# Copyright lowRISC contributors (OpenTitan project).
# Licensed under the Apache License, Version 2.0, see LICENSE for details.
# SPDX-License-Identifier: Apache-2.0
#
# This file was derived by lowRISC contributors (OpenTitan project) from the
# IHP Open PDK SRAM abstract RM_IHPSG13_1P_8192x32_c4.lef
# (https://github.com/IHP-GmbH/IHP-Open-PDK, ihp-sg13g2/libs.ref/sg13g2_sram/lef).
# It is a synthetic abstract, not an IHP release: the macro size and pins come
# from the Liberty view, the pin shapes, power straps and antenna values from
# the IHP abstract. IHP's original notice follows:
#
#   Copyright 2023 IHP PDK Authors
#
#   Licensed under the Apache License, Version 2.0 (the "License");
#   you may not use this file except in compliance with the License.
#   You may obtain a copy of the License at
#
#      https://www.apache.org/licenses/LICENSE-2.0
#
#   Unless required by applicable law or agreed to in writing, software
#   distributed under the License is distributed on an "AS IS" BASIS,
#   WITHOUT WARRANTIES OR CONDITIONS OF ANY KIND, either express or implied.
#   See the License for the specific language governing permissions and
#   limitations under the License.
#
#   Generated on Mon Apr  7 14:15:46 2025
#
# Generated by gen_synthetic_lef.py from the Liberty view. Do not edit.
# Synthetic abstract: no physical layout exists behind this macro.

VERSION 5.7 ;
BUSBITCHARS "[]" ;
DIVIDERCHAR "/" ;

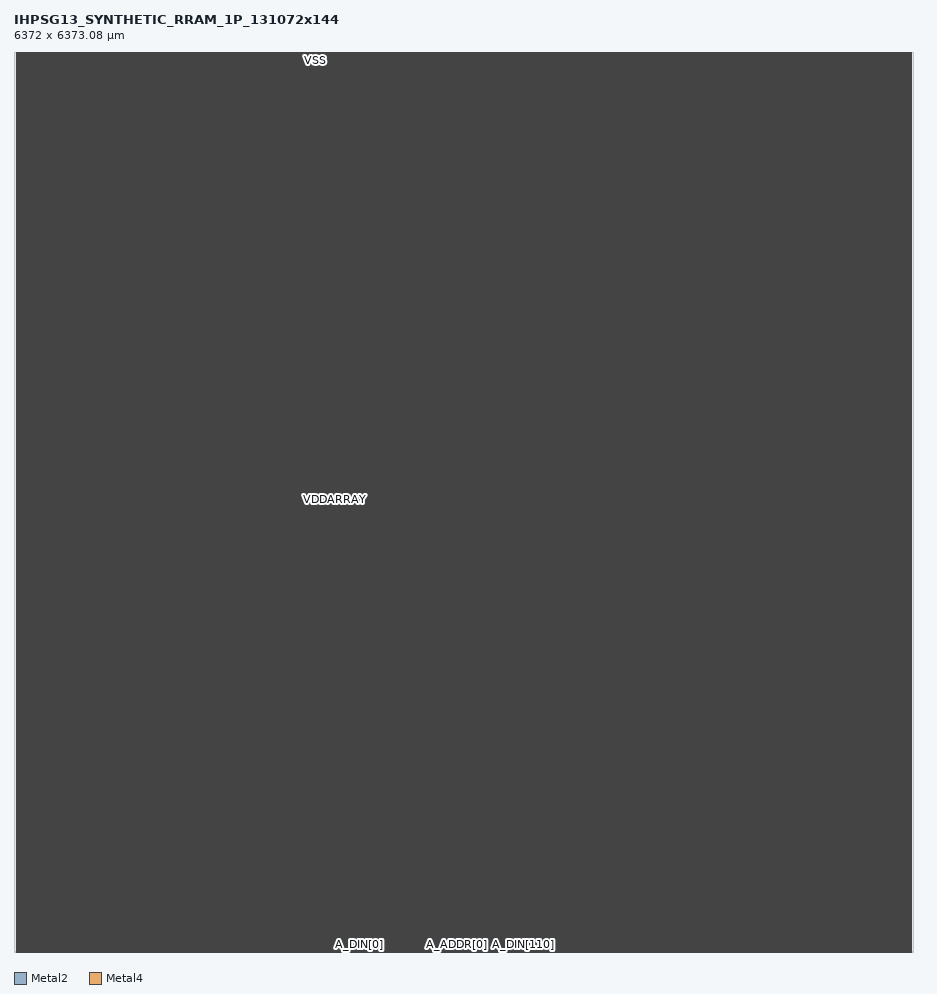
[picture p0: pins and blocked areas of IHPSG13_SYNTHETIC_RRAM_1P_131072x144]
MACRO IHPSG13_SYNTHETIC_RRAM_1P_131072x144
  CLASS BLOCK ;
  ORIGIN 0 0 ;
  FOREIGN IHPSG13_SYNTHETIC_RRAM_1P_131072x144 0 0 ;
  SIZE 6372 BY 6373.08 ;
  SYMMETRY X Y R90 ;
  PIN A_DIN[0]
    DIRECTION INPUT ;
    USE SIGNAL ;
    ANTENNAMODEL OXIDE1 ;
      ANTENNAGATEAREA 0.20085 LAYER Metal2 ;
    PORT
      LAYER Metal2 ;
        RECT 2444.03 0 2444.29 0.26 ;
    END
  END A_DIN[0]
  PIN A_DOUT[0]
    DIRECTION OUTPUT ;
    USE SIGNAL ;
    ANTENNADIFFAREA 0.988 LAYER Metal2 ;
    PORT
      LAYER Metal2 ;
        RECT 2448.83 0 2449.09 0.26 ;
    END
  END A_DOUT[0]
  PIN A_DIN[1]
    DIRECTION INPUT ;
    USE SIGNAL ;
    ANTENNAMODEL OXIDE1 ;
      ANTENNAGATEAREA 0.20085 LAYER Metal2 ;
    PORT
      LAYER Metal2 ;
        RECT 2453.63 0 2453.89 0.26 ;
    END
  END A_DIN[1]
  PIN A_DOUT[1]
    DIRECTION OUTPUT ;
    USE SIGNAL ;
    ANTENNADIFFAREA 0.988 LAYER Metal2 ;
    PORT
      LAYER Metal2 ;
        RECT 2458.43 0 2458.69 0.26 ;
    END
  END A_DOUT[1]
  PIN A_DIN[2]
    DIRECTION INPUT ;
    USE SIGNAL ;
    ANTENNAMODEL OXIDE1 ;
      ANTENNAGATEAREA 0.20085 LAYER Metal2 ;
    PORT
      LAYER Metal2 ;
        RECT 2463.23 0 2463.49 0.26 ;
    END
  END A_DIN[2]
  PIN A_DOUT[2]
    DIRECTION OUTPUT ;
    USE SIGNAL ;
    ANTENNADIFFAREA 0.988 LAYER Metal2 ;
    PORT
      LAYER Metal2 ;
        RECT 2468.03 0 2468.29 0.26 ;
    END
  END A_DOUT[2]
  PIN A_DIN[3]
    DIRECTION INPUT ;
    USE SIGNAL ;
    ANTENNAMODEL OXIDE1 ;
      ANTENNAGATEAREA 0.20085 LAYER Metal2 ;
    PORT
      LAYER Metal2 ;
        RECT 2472.83 0 2473.09 0.26 ;
    END
  END A_DIN[3]
  PIN A_DOUT[3]
    DIRECTION OUTPUT ;
    USE SIGNAL ;
    ANTENNADIFFAREA 0.988 LAYER Metal2 ;
    PORT
      LAYER Metal2 ;
        RECT 2477.63 0 2477.89 0.26 ;
    END
  END A_DOUT[3]
  PIN A_DIN[4]
    DIRECTION INPUT ;
    USE SIGNAL ;
    ANTENNAMODEL OXIDE1 ;
      ANTENNAGATEAREA 0.20085 LAYER Metal2 ;
    PORT
      LAYER Metal2 ;
        RECT 2482.43 0 2482.69 0.26 ;
    END
  END A_DIN[4]
  PIN A_DOUT[4]
    DIRECTION OUTPUT ;
    USE SIGNAL ;
    ANTENNADIFFAREA 0.988 LAYER Metal2 ;
    PORT
      LAYER Metal2 ;
        RECT 2487.23 0 2487.49 0.26 ;
    END
  END A_DOUT[4]
  PIN A_DIN[5]
    DIRECTION INPUT ;
    USE SIGNAL ;
    ANTENNAMODEL OXIDE1 ;
      ANTENNAGATEAREA 0.20085 LAYER Metal2 ;
    PORT
      LAYER Metal2 ;
        RECT 2492.03 0 2492.29 0.26 ;
    END
  END A_DIN[5]
  PIN A_DOUT[5]
    DIRECTION OUTPUT ;
    USE SIGNAL ;
    ANTENNADIFFAREA 0.988 LAYER Metal2 ;
    PORT
      LAYER Metal2 ;
        RECT 2496.83 0 2497.09 0.26 ;
    END
  END A_DOUT[5]
  PIN A_DIN[6]
    DIRECTION INPUT ;
    USE SIGNAL ;
    ANTENNAMODEL OXIDE1 ;
      ANTENNAGATEAREA 0.20085 LAYER Metal2 ;
    PORT
      LAYER Metal2 ;
        RECT 2501.63 0 2501.89 0.26 ;
    END
  END A_DIN[6]
  PIN A_DOUT[6]
    DIRECTION OUTPUT ;
    USE SIGNAL ;
    ANTENNADIFFAREA 0.988 LAYER Metal2 ;
    PORT
      LAYER Metal2 ;
        RECT 2506.43 0 2506.69 0.26 ;
    END
  END A_DOUT[6]
  PIN A_DIN[7]
    DIRECTION INPUT ;
    USE SIGNAL ;
    ANTENNAMODEL OXIDE1 ;
      ANTENNAGATEAREA 0.20085 LAYER Metal2 ;
    PORT
      LAYER Metal2 ;
        RECT 2511.23 0 2511.49 0.26 ;
    END
  END A_DIN[7]
  PIN A_DOUT[7]
    DIRECTION OUTPUT ;
    USE SIGNAL ;
    ANTENNADIFFAREA 0.988 LAYER Metal2 ;
    PORT
      LAYER Metal2 ;
        RECT 2516.03 0 2516.29 0.26 ;
    END
  END A_DOUT[7]
  PIN A_DIN[8]
    DIRECTION INPUT ;
    USE SIGNAL ;
    ANTENNAMODEL OXIDE1 ;
      ANTENNAGATEAREA 0.20085 LAYER Metal2 ;
    PORT
      LAYER Metal2 ;
        RECT 2520.83 0 2521.09 0.26 ;
    END
  END A_DIN[8]
  PIN A_DOUT[8]
    DIRECTION OUTPUT ;
    USE SIGNAL ;
    ANTENNADIFFAREA 0.988 LAYER Metal2 ;
    PORT
      LAYER Metal2 ;
        RECT 2525.63 0 2525.89 0.26 ;
    END
  END A_DOUT[8]
  PIN A_DIN[9]
    DIRECTION INPUT ;
    USE SIGNAL ;
    ANTENNAMODEL OXIDE1 ;
      ANTENNAGATEAREA 0.20085 LAYER Metal2 ;
    PORT
      LAYER Metal2 ;
        RECT 2530.43 0 2530.69 0.26 ;
    END
  END A_DIN[9]
  PIN A_DOUT[9]
    DIRECTION OUTPUT ;
    USE SIGNAL ;
    ANTENNADIFFAREA 0.988 LAYER Metal2 ;
    PORT
      LAYER Metal2 ;
        RECT 2535.23 0 2535.49 0.26 ;
    END
  END A_DOUT[9]
  PIN A_DIN[10]
    DIRECTION INPUT ;
    USE SIGNAL ;
    ANTENNAMODEL OXIDE1 ;
      ANTENNAGATEAREA 0.20085 LAYER Metal2 ;
    PORT
      LAYER Metal2 ;
        RECT 2540.03 0 2540.29 0.26 ;
    END
  END A_DIN[10]
  PIN A_DOUT[10]
    DIRECTION OUTPUT ;
    USE SIGNAL ;
    ANTENNADIFFAREA 0.988 LAYER Metal2 ;
    PORT
      LAYER Metal2 ;
        RECT 2544.83 0 2545.09 0.26 ;
    END
  END A_DOUT[10]
  PIN A_DIN[11]
    DIRECTION INPUT ;
    USE SIGNAL ;
    ANTENNAMODEL OXIDE1 ;
      ANTENNAGATEAREA 0.20085 LAYER Metal2 ;
    PORT
      LAYER Metal2 ;
        RECT 2549.63 0 2549.89 0.26 ;
    END
  END A_DIN[11]
  PIN A_DOUT[11]
    DIRECTION OUTPUT ;
    USE SIGNAL ;
    ANTENNADIFFAREA 0.988 LAYER Metal2 ;
    PORT
      LAYER Metal2 ;
        RECT 2554.43 0 2554.69 0.26 ;
    END
  END A_DOUT[11]
  PIN A_DIN[12]
    DIRECTION INPUT ;
    USE SIGNAL ;
    ANTENNAMODEL OXIDE1 ;
      ANTENNAGATEAREA 0.20085 LAYER Metal2 ;
    PORT
      LAYER Metal2 ;
        RECT 2559.23 0 2559.49 0.26 ;
    END
  END A_DIN[12]
  PIN A_DOUT[12]
    DIRECTION OUTPUT ;
    USE SIGNAL ;
    ANTENNADIFFAREA 0.988 LAYER Metal2 ;
    PORT
      LAYER Metal2 ;
        RECT 2564.03 0 2564.29 0.26 ;
    END
  END A_DOUT[12]
  PIN A_DIN[13]
    DIRECTION INPUT ;
    USE SIGNAL ;
    ANTENNAMODEL OXIDE1 ;
      ANTENNAGATEAREA 0.20085 LAYER Metal2 ;
    PORT
      LAYER Metal2 ;
        RECT 2568.83 0 2569.09 0.26 ;
    END
  END A_DIN[13]
  PIN A_DOUT[13]
    DIRECTION OUTPUT ;
    USE SIGNAL ;
    ANTENNADIFFAREA 0.988 LAYER Metal2 ;
    PORT
      LAYER Metal2 ;
        RECT 2573.63 0 2573.89 0.26 ;
    END
  END A_DOUT[13]
  PIN A_DIN[14]
    DIRECTION INPUT ;
    USE SIGNAL ;
    ANTENNAMODEL OXIDE1 ;
      ANTENNAGATEAREA 0.20085 LAYER Metal2 ;
    PORT
      LAYER Metal2 ;
        RECT 2578.43 0 2578.69 0.26 ;
    END
  END A_DIN[14]
  PIN A_DOUT[14]
    DIRECTION OUTPUT ;
    USE SIGNAL ;
    ANTENNADIFFAREA 0.988 LAYER Metal2 ;
    PORT
      LAYER Metal2 ;
        RECT 2583.23 0 2583.49 0.26 ;
    END
  END A_DOUT[14]
  PIN A_DIN[15]
    DIRECTION INPUT ;
    USE SIGNAL ;
    ANTENNAMODEL OXIDE1 ;
      ANTENNAGATEAREA 0.20085 LAYER Metal2 ;
    PORT
      LAYER Metal2 ;
        RECT 2588.03 0 2588.29 0.26 ;
    END
  END A_DIN[15]
  PIN A_DOUT[15]
    DIRECTION OUTPUT ;
    USE SIGNAL ;
    ANTENNADIFFAREA 0.988 LAYER Metal2 ;
    PORT
      LAYER Metal2 ;
        RECT 2592.83 0 2593.09 0.26 ;
    END
  END A_DOUT[15]
  PIN A_DIN[16]
    DIRECTION INPUT ;
    USE SIGNAL ;
    ANTENNAMODEL OXIDE1 ;
      ANTENNAGATEAREA 0.20085 LAYER Metal2 ;
    PORT
      LAYER Metal2 ;
        RECT 2597.63 0 2597.89 0.26 ;
    END
  END A_DIN[16]
  PIN A_DOUT[16]
    DIRECTION OUTPUT ;
    USE SIGNAL ;
    ANTENNADIFFAREA 0.988 LAYER Metal2 ;
    PORT
      LAYER Metal2 ;
        RECT 2602.43 0 2602.69 0.26 ;
    END
  END A_DOUT[16]
  PIN A_DIN[17]
    DIRECTION INPUT ;
    USE SIGNAL ;
    ANTENNAMODEL OXIDE1 ;
      ANTENNAGATEAREA 0.20085 LAYER Metal2 ;
    PORT
      LAYER Metal2 ;
        RECT 2607.23 0 2607.49 0.26 ;
    END
  END A_DIN[17]
  PIN A_DOUT[17]
    DIRECTION OUTPUT ;
    USE SIGNAL ;
    ANTENNADIFFAREA 0.988 LAYER Metal2 ;
    PORT
      LAYER Metal2 ;
        RECT 2612.03 0 2612.29 0.26 ;
    END
  END A_DOUT[17]
  PIN A_DIN[18]
    DIRECTION INPUT ;
    USE SIGNAL ;
    ANTENNAMODEL OXIDE1 ;
      ANTENNAGATEAREA 0.20085 LAYER Metal2 ;
    PORT
      LAYER Metal2 ;
        RECT 2616.83 0 2617.09 0.26 ;
    END
  END A_DIN[18]
  PIN A_DOUT[18]
    DIRECTION OUTPUT ;
    USE SIGNAL ;
    ANTENNADIFFAREA 0.988 LAYER Metal2 ;
    PORT
      LAYER Metal2 ;
        RECT 2621.63 0 2621.89 0.26 ;
    END
  END A_DOUT[18]
  PIN A_DIN[19]
    DIRECTION INPUT ;
    USE SIGNAL ;
    ANTENNAMODEL OXIDE1 ;
      ANTENNAGATEAREA 0.20085 LAYER Metal2 ;
    PORT
      LAYER Metal2 ;
        RECT 2626.43 0 2626.69 0.26 ;
    END
  END A_DIN[19]
  PIN A_DOUT[19]
    DIRECTION OUTPUT ;
    USE SIGNAL ;
    ANTENNADIFFAREA 0.988 LAYER Metal2 ;
    PORT
      LAYER Metal2 ;
        RECT 2631.23 0 2631.49 0.26 ;
    END
  END A_DOUT[19]
  PIN A_DIN[20]
    DIRECTION INPUT ;
    USE SIGNAL ;
    ANTENNAMODEL OXIDE1 ;
      ANTENNAGATEAREA 0.20085 LAYER Metal2 ;
    PORT
      LAYER Metal2 ;
        RECT 2636.03 0 2636.29 0.26 ;
    END
  END A_DIN[20]
  PIN A_DOUT[20]
    DIRECTION OUTPUT ;
    USE SIGNAL ;
    ANTENNADIFFAREA 0.988 LAYER Metal2 ;
    PORT
      LAYER Metal2 ;
        RECT 2640.83 0 2641.09 0.26 ;
    END
  END A_DOUT[20]
  PIN A_DIN[21]
    DIRECTION INPUT ;
    USE SIGNAL ;
    ANTENNAMODEL OXIDE1 ;
      ANTENNAGATEAREA 0.20085 LAYER Metal2 ;
    PORT
      LAYER Metal2 ;
        RECT 2645.63 0 2645.89 0.26 ;
    END
  END A_DIN[21]
  PIN A_DOUT[21]
    DIRECTION OUTPUT ;
    USE SIGNAL ;
    ANTENNADIFFAREA 0.988 LAYER Metal2 ;
    PORT
      LAYER Metal2 ;
        RECT 2650.43 0 2650.69 0.26 ;
    END
  END A_DOUT[21]
  PIN A_DIN[22]
    DIRECTION INPUT ;
    USE SIGNAL ;
    ANTENNAMODEL OXIDE1 ;
      ANTENNAGATEAREA 0.20085 LAYER Metal2 ;
    PORT
      LAYER Metal2 ;
        RECT 2655.23 0 2655.49 0.26 ;
    END
  END A_DIN[22]
  PIN A_DOUT[22]
    DIRECTION OUTPUT ;
    USE SIGNAL ;
    ANTENNADIFFAREA 0.988 LAYER Metal2 ;
    PORT
      LAYER Metal2 ;
        RECT 2660.03 0 2660.29 0.26 ;
    END
  END A_DOUT[22]
  PIN A_DIN[23]
    DIRECTION INPUT ;
    USE SIGNAL ;
    ANTENNAMODEL OXIDE1 ;
      ANTENNAGATEAREA 0.20085 LAYER Metal2 ;
    PORT
      LAYER Metal2 ;
        RECT 2664.83 0 2665.09 0.26 ;
    END
  END A_DIN[23]
  PIN A_DOUT[23]
    DIRECTION OUTPUT ;
    USE SIGNAL ;
    ANTENNADIFFAREA 0.988 LAYER Metal2 ;
    PORT
      LAYER Metal2 ;
        RECT 2669.63 0 2669.89 0.26 ;
    END
  END A_DOUT[23]
  PIN A_DIN[24]
    DIRECTION INPUT ;
    USE SIGNAL ;
    ANTENNAMODEL OXIDE1 ;
      ANTENNAGATEAREA 0.20085 LAYER Metal2 ;
    PORT
      LAYER Metal2 ;
        RECT 2674.43 0 2674.69 0.26 ;
    END
  END A_DIN[24]
  PIN A_DOUT[24]
    DIRECTION OUTPUT ;
    USE SIGNAL ;
    ANTENNADIFFAREA 0.988 LAYER Metal2 ;
    PORT
      LAYER Metal2 ;
        RECT 2679.23 0 2679.49 0.26 ;
    END
  END A_DOUT[24]
  PIN A_DIN[25]
    DIRECTION INPUT ;
    USE SIGNAL ;
    ANTENNAMODEL OXIDE1 ;
      ANTENNAGATEAREA 0.20085 LAYER Metal2 ;
    PORT
      LAYER Metal2 ;
        RECT 2684.03 0 2684.29 0.26 ;
    END
  END A_DIN[25]
  PIN A_DOUT[25]
    DIRECTION OUTPUT ;
    USE SIGNAL ;
    ANTENNADIFFAREA 0.988 LAYER Metal2 ;
    PORT
      LAYER Metal2 ;
        RECT 2688.83 0 2689.09 0.26 ;
    END
  END A_DOUT[25]
  PIN A_DIN[26]
    DIRECTION INPUT ;
    USE SIGNAL ;
    ANTENNAMODEL OXIDE1 ;
      ANTENNAGATEAREA 0.20085 LAYER Metal2 ;
    PORT
      LAYER Metal2 ;
        RECT 2693.63 0 2693.89 0.26 ;
    END
  END A_DIN[26]
  PIN A_DOUT[26]
    DIRECTION OUTPUT ;
    USE SIGNAL ;
    ANTENNADIFFAREA 0.988 LAYER Metal2 ;
    PORT
      LAYER Metal2 ;
        RECT 2698.43 0 2698.69 0.26 ;
    END
  END A_DOUT[26]
  PIN A_DIN[27]
    DIRECTION INPUT ;
    USE SIGNAL ;
    ANTENNAMODEL OXIDE1 ;
      ANTENNAGATEAREA 0.20085 LAYER Metal2 ;
    PORT
      LAYER Metal2 ;
        RECT 2703.23 0 2703.49 0.26 ;
    END
  END A_DIN[27]
  PIN A_DOUT[27]
    DIRECTION OUTPUT ;
    USE SIGNAL ;
    ANTENNADIFFAREA 0.988 LAYER Metal2 ;
    PORT
      LAYER Metal2 ;
        RECT 2708.03 0 2708.29 0.26 ;
    END
  END A_DOUT[27]
  PIN A_DIN[28]
    DIRECTION INPUT ;
    USE SIGNAL ;
    ANTENNAMODEL OXIDE1 ;
      ANTENNAGATEAREA 0.20085 LAYER Metal2 ;
    PORT
      LAYER Metal2 ;
        RECT 2712.83 0 2713.09 0.26 ;
    END
  END A_DIN[28]
  PIN A_DOUT[28]
    DIRECTION OUTPUT ;
    USE SIGNAL ;
    ANTENNADIFFAREA 0.988 LAYER Metal2 ;
    PORT
      LAYER Metal2 ;
        RECT 2717.63 0 2717.89 0.26 ;
    END
  END A_DOUT[28]
  PIN A_DIN[29]
    DIRECTION INPUT ;
    USE SIGNAL ;
    ANTENNAMODEL OXIDE1 ;
      ANTENNAGATEAREA 0.20085 LAYER Metal2 ;
    PORT
      LAYER Metal2 ;
        RECT 2722.43 0 2722.69 0.26 ;
    END
  END A_DIN[29]
  PIN A_DOUT[29]
    DIRECTION OUTPUT ;
    USE SIGNAL ;
    ANTENNADIFFAREA 0.988 LAYER Metal2 ;
    PORT
      LAYER Metal2 ;
        RECT 2727.23 0 2727.49 0.26 ;
    END
  END A_DOUT[29]
  PIN A_DIN[30]
    DIRECTION INPUT ;
    USE SIGNAL ;
    ANTENNAMODEL OXIDE1 ;
      ANTENNAGATEAREA 0.20085 LAYER Metal2 ;
    PORT
      LAYER Metal2 ;
        RECT 2732.03 0 2732.29 0.26 ;
    END
  END A_DIN[30]
  PIN A_DOUT[30]
    DIRECTION OUTPUT ;
    USE SIGNAL ;
    ANTENNADIFFAREA 0.988 LAYER Metal2 ;
    PORT
      LAYER Metal2 ;
        RECT 2736.83 0 2737.09 0.26 ;
    END
  END A_DOUT[30]
  PIN A_DIN[31]
    DIRECTION INPUT ;
    USE SIGNAL ;
    ANTENNAMODEL OXIDE1 ;
      ANTENNAGATEAREA 0.20085 LAYER Metal2 ;
    PORT
      LAYER Metal2 ;
        RECT 2741.63 0 2741.89 0.26 ;
    END
  END A_DIN[31]
  PIN A_DOUT[31]
    DIRECTION OUTPUT ;
    USE SIGNAL ;
    ANTENNADIFFAREA 0.988 LAYER Metal2 ;
    PORT
      LAYER Metal2 ;
        RECT 2746.43 0 2746.69 0.26 ;
    END
  END A_DOUT[31]
  PIN A_DIN[32]
    DIRECTION INPUT ;
    USE SIGNAL ;
    ANTENNAMODEL OXIDE1 ;
      ANTENNAGATEAREA 0.20085 LAYER Metal2 ;
    PORT
      LAYER Metal2 ;
        RECT 2751.23 0 2751.49 0.26 ;
    END
  END A_DIN[32]
  PIN A_DOUT[32]
    DIRECTION OUTPUT ;
    USE SIGNAL ;
    ANTENNADIFFAREA 0.988 LAYER Metal2 ;
    PORT
      LAYER Metal2 ;
        RECT 2756.03 0 2756.29 0.26 ;
    END
  END A_DOUT[32]
  PIN A_DIN[33]
    DIRECTION INPUT ;
    USE SIGNAL ;
    ANTENNAMODEL OXIDE1 ;
      ANTENNAGATEAREA 0.20085 LAYER Metal2 ;
    PORT
      LAYER Metal2 ;
        RECT 2760.83 0 2761.09 0.26 ;
    END
  END A_DIN[33]
  PIN A_DOUT[33]
    DIRECTION OUTPUT ;
    USE SIGNAL ;
    ANTENNADIFFAREA 0.988 LAYER Metal2 ;
    PORT
      LAYER Metal2 ;
        RECT 2765.63 0 2765.89 0.26 ;
    END
  END A_DOUT[33]
  PIN A_DIN[34]
    DIRECTION INPUT ;
    USE SIGNAL ;
    ANTENNAMODEL OXIDE1 ;
      ANTENNAGATEAREA 0.20085 LAYER Metal2 ;
    PORT
      LAYER Metal2 ;
        RECT 2770.43 0 2770.69 0.26 ;
    END
  END A_DIN[34]
  PIN A_DOUT[34]
    DIRECTION OUTPUT ;
    USE SIGNAL ;
    ANTENNADIFFAREA 0.988 LAYER Metal2 ;
    PORT
      LAYER Metal2 ;
        RECT 2775.23 0 2775.49 0.26 ;
    END
  END A_DOUT[34]
  PIN A_DIN[35]
    DIRECTION INPUT ;
    USE SIGNAL ;
    ANTENNAMODEL OXIDE1 ;
      ANTENNAGATEAREA 0.20085 LAYER Metal2 ;
    PORT
      LAYER Metal2 ;
        RECT 2780.03 0 2780.29 0.26 ;
    END
  END A_DIN[35]
  PIN A_DOUT[35]
    DIRECTION OUTPUT ;
    USE SIGNAL ;
    ANTENNADIFFAREA 0.988 LAYER Metal2 ;
    PORT
      LAYER Metal2 ;
        RECT 2784.83 0 2785.09 0.26 ;
    END
  END A_DOUT[35]
  PIN A_DIN[36]
    DIRECTION INPUT ;
    USE SIGNAL ;
    ANTENNAMODEL OXIDE1 ;
      ANTENNAGATEAREA 0.20085 LAYER Metal2 ;
    PORT
      LAYER Metal2 ;
        RECT 2789.63 0 2789.89 0.26 ;
    END
  END A_DIN[36]
  PIN A_DOUT[36]
    DIRECTION OUTPUT ;
    USE SIGNAL ;
    ANTENNADIFFAREA 0.988 LAYER Metal2 ;
    PORT
      LAYER Metal2 ;
        RECT 2794.43 0 2794.69 0.26 ;
    END
  END A_DOUT[36]
  PIN A_DIN[37]
    DIRECTION INPUT ;
    USE SIGNAL ;
    ANTENNAMODEL OXIDE1 ;
      ANTENNAGATEAREA 0.20085 LAYER Metal2 ;
    PORT
      LAYER Metal2 ;
        RECT 2799.23 0 2799.49 0.26 ;
    END
  END A_DIN[37]
  PIN A_DOUT[37]
    DIRECTION OUTPUT ;
    USE SIGNAL ;
    ANTENNADIFFAREA 0.988 LAYER Metal2 ;
    PORT
      LAYER Metal2 ;
        RECT 2804.03 0 2804.29 0.26 ;
    END
  END A_DOUT[37]
  PIN A_DIN[38]
    DIRECTION INPUT ;
    USE SIGNAL ;
    ANTENNAMODEL OXIDE1 ;
      ANTENNAGATEAREA 0.20085 LAYER Metal2 ;
    PORT
      LAYER Metal2 ;
        RECT 2808.83 0 2809.09 0.26 ;
    END
  END A_DIN[38]
  PIN A_DOUT[38]
    DIRECTION OUTPUT ;
    USE SIGNAL ;
    ANTENNADIFFAREA 0.988 LAYER Metal2 ;
    PORT
      LAYER Metal2 ;
        RECT 2813.63 0 2813.89 0.26 ;
    END
  END A_DOUT[38]
  PIN A_DIN[39]
    DIRECTION INPUT ;
    USE SIGNAL ;
    ANTENNAMODEL OXIDE1 ;
      ANTENNAGATEAREA 0.20085 LAYER Metal2 ;
    PORT
      LAYER Metal2 ;
        RECT 2818.43 0 2818.69 0.26 ;
    END
  END A_DIN[39]
  PIN A_DOUT[39]
    DIRECTION OUTPUT ;
    USE SIGNAL ;
    ANTENNADIFFAREA 0.988 LAYER Metal2 ;
    PORT
      LAYER Metal2 ;
        RECT 2823.23 0 2823.49 0.26 ;
    END
  END A_DOUT[39]
  PIN A_DIN[40]
    DIRECTION INPUT ;
    USE SIGNAL ;
    ANTENNAMODEL OXIDE1 ;
      ANTENNAGATEAREA 0.20085 LAYER Metal2 ;
    PORT
      LAYER Metal2 ;
        RECT 2828.03 0 2828.29 0.26 ;
    END
  END A_DIN[40]
  PIN A_DOUT[40]
    DIRECTION OUTPUT ;
    USE SIGNAL ;
    ANTENNADIFFAREA 0.988 LAYER Metal2 ;
    PORT
      LAYER Metal2 ;
        RECT 2832.83 0 2833.09 0.26 ;
    END
  END A_DOUT[40]
  PIN A_DIN[41]
    DIRECTION INPUT ;
    USE SIGNAL ;
    ANTENNAMODEL OXIDE1 ;
      ANTENNAGATEAREA 0.20085 LAYER Metal2 ;
    PORT
      LAYER Metal2 ;
        RECT 2837.63 0 2837.89 0.26 ;
    END
  END A_DIN[41]
  PIN A_DOUT[41]
    DIRECTION OUTPUT ;
    USE SIGNAL ;
    ANTENNADIFFAREA 0.988 LAYER Metal2 ;
    PORT
      LAYER Metal2 ;
        RECT 2842.43 0 2842.69 0.26 ;
    END
  END A_DOUT[41]
  PIN A_DIN[42]
    DIRECTION INPUT ;
    USE SIGNAL ;
    ANTENNAMODEL OXIDE1 ;
      ANTENNAGATEAREA 0.20085 LAYER Metal2 ;
    PORT
      LAYER Metal2 ;
        RECT 2847.23 0 2847.49 0.26 ;
    END
  END A_DIN[42]
  PIN A_DOUT[42]
    DIRECTION OUTPUT ;
    USE SIGNAL ;
    ANTENNADIFFAREA 0.988 LAYER Metal2 ;
    PORT
      LAYER Metal2 ;
        RECT 2852.03 0 2852.29 0.26 ;
    END
  END A_DOUT[42]
  PIN A_DIN[43]
    DIRECTION INPUT ;
    USE SIGNAL ;
    ANTENNAMODEL OXIDE1 ;
      ANTENNAGATEAREA 0.20085 LAYER Metal2 ;
    PORT
      LAYER Metal2 ;
        RECT 2856.83 0 2857.09 0.26 ;
    END
  END A_DIN[43]
  PIN A_DOUT[43]
    DIRECTION OUTPUT ;
    USE SIGNAL ;
    ANTENNADIFFAREA 0.988 LAYER Metal2 ;
    PORT
      LAYER Metal2 ;
        RECT 2861.63 0 2861.89 0.26 ;
    END
  END A_DOUT[43]
  PIN A_DIN[44]
    DIRECTION INPUT ;
    USE SIGNAL ;
    ANTENNAMODEL OXIDE1 ;
      ANTENNAGATEAREA 0.20085 LAYER Metal2 ;
    PORT
      LAYER Metal2 ;
        RECT 2866.43 0 2866.69 0.26 ;
    END
  END A_DIN[44]
  PIN A_DOUT[44]
    DIRECTION OUTPUT ;
    USE SIGNAL ;
    ANTENNADIFFAREA 0.988 LAYER Metal2 ;
    PORT
      LAYER Metal2 ;
        RECT 2871.23 0 2871.49 0.26 ;
    END
  END A_DOUT[44]
  PIN A_DIN[45]
    DIRECTION INPUT ;
    USE SIGNAL ;
    ANTENNAMODEL OXIDE1 ;
      ANTENNAGATEAREA 0.20085 LAYER Metal2 ;
    PORT
      LAYER Metal2 ;
        RECT 2876.03 0 2876.29 0.26 ;
    END
  END A_DIN[45]
  PIN A_DOUT[45]
    DIRECTION OUTPUT ;
    USE SIGNAL ;
    ANTENNADIFFAREA 0.988 LAYER Metal2 ;
    PORT
      LAYER Metal2 ;
        RECT 2880.83 0 2881.09 0.26 ;
    END
  END A_DOUT[45]
  PIN A_DIN[46]
    DIRECTION INPUT ;
    USE SIGNAL ;
    ANTENNAMODEL OXIDE1 ;
      ANTENNAGATEAREA 0.20085 LAYER Metal2 ;
    PORT
      LAYER Metal2 ;
        RECT 2885.63 0 2885.89 0.26 ;
    END
  END A_DIN[46]
  PIN A_DOUT[46]
    DIRECTION OUTPUT ;
    USE SIGNAL ;
    ANTENNADIFFAREA 0.988 LAYER Metal2 ;
    PORT
      LAYER Metal2 ;
        RECT 2890.43 0 2890.69 0.26 ;
    END
  END A_DOUT[46]
  PIN A_DIN[47]
    DIRECTION INPUT ;
    USE SIGNAL ;
    ANTENNAMODEL OXIDE1 ;
      ANTENNAGATEAREA 0.20085 LAYER Metal2 ;
    PORT
      LAYER Metal2 ;
        RECT 2895.23 0 2895.49 0.26 ;
    END
  END A_DIN[47]
  PIN A_DOUT[47]
    DIRECTION OUTPUT ;
    USE SIGNAL ;
    ANTENNADIFFAREA 0.988 LAYER Metal2 ;
    PORT
      LAYER Metal2 ;
        RECT 2900.03 0 2900.29 0.26 ;
    END
  END A_DOUT[47]
  PIN A_DIN[48]
    DIRECTION INPUT ;
    USE SIGNAL ;
    ANTENNAMODEL OXIDE1 ;
      ANTENNAGATEAREA 0.20085 LAYER Metal2 ;
    PORT
      LAYER Metal2 ;
        RECT 2904.83 0 2905.09 0.26 ;
    END
  END A_DIN[48]
  PIN A_DOUT[48]
    DIRECTION OUTPUT ;
    USE SIGNAL ;
    ANTENNADIFFAREA 0.988 LAYER Metal2 ;
    PORT
      LAYER Metal2 ;
        RECT 2909.63 0 2909.89 0.26 ;
    END
  END A_DOUT[48]
  PIN A_DIN[49]
    DIRECTION INPUT ;
    USE SIGNAL ;
    ANTENNAMODEL OXIDE1 ;
      ANTENNAGATEAREA 0.20085 LAYER Metal2 ;
    PORT
      LAYER Metal2 ;
        RECT 2914.43 0 2914.69 0.26 ;
    END
  END A_DIN[49]
  PIN A_DOUT[49]
    DIRECTION OUTPUT ;
    USE SIGNAL ;
    ANTENNADIFFAREA 0.988 LAYER Metal2 ;
    PORT
      LAYER Metal2 ;
        RECT 2919.23 0 2919.49 0.26 ;
    END
  END A_DOUT[49]
  PIN A_DIN[50]
    DIRECTION INPUT ;
    USE SIGNAL ;
    ANTENNAMODEL OXIDE1 ;
      ANTENNAGATEAREA 0.20085 LAYER Metal2 ;
    PORT
      LAYER Metal2 ;
        RECT 2924.03 0 2924.29 0.26 ;
    END
  END A_DIN[50]
  PIN A_DOUT[50]
    DIRECTION OUTPUT ;
    USE SIGNAL ;
    ANTENNADIFFAREA 0.988 LAYER Metal2 ;
    PORT
      LAYER Metal2 ;
        RECT 2928.83 0 2929.09 0.26 ;
    END
  END A_DOUT[50]
  PIN A_DIN[51]
    DIRECTION INPUT ;
    USE SIGNAL ;
    ANTENNAMODEL OXIDE1 ;
      ANTENNAGATEAREA 0.20085 LAYER Metal2 ;
    PORT
      LAYER Metal2 ;
        RECT 2933.63 0 2933.89 0.26 ;
    END
  END A_DIN[51]
  PIN A_DOUT[51]
    DIRECTION OUTPUT ;
    USE SIGNAL ;
    ANTENNADIFFAREA 0.988 LAYER Metal2 ;
    PORT
      LAYER Metal2 ;
        RECT 2938.43 0 2938.69 0.26 ;
    END
  END A_DOUT[51]
  PIN A_DIN[52]
    DIRECTION INPUT ;
    USE SIGNAL ;
    ANTENNAMODEL OXIDE1 ;
      ANTENNAGATEAREA 0.20085 LAYER Metal2 ;
    PORT
      LAYER Metal2 ;
        RECT 2943.23 0 2943.49 0.26 ;
    END
  END A_DIN[52]
  PIN A_DOUT[52]
    DIRECTION OUTPUT ;
    USE SIGNAL ;
    ANTENNADIFFAREA 0.988 LAYER Metal2 ;
    PORT
      LAYER Metal2 ;
        RECT 2948.03 0 2948.29 0.26 ;
    END
  END A_DOUT[52]
  PIN A_DIN[53]
    DIRECTION INPUT ;
    USE SIGNAL ;
    ANTENNAMODEL OXIDE1 ;
      ANTENNAGATEAREA 0.20085 LAYER Metal2 ;
    PORT
      LAYER Metal2 ;
        RECT 2952.83 0 2953.09 0.26 ;
    END
  END A_DIN[53]
  PIN A_DOUT[53]
    DIRECTION OUTPUT ;
    USE SIGNAL ;
    ANTENNADIFFAREA 0.988 LAYER Metal2 ;
    PORT
      LAYER Metal2 ;
        RECT 2957.63 0 2957.89 0.26 ;
    END
  END A_DOUT[53]
  PIN A_DIN[54]
    DIRECTION INPUT ;
    USE SIGNAL ;
    ANTENNAMODEL OXIDE1 ;
      ANTENNAGATEAREA 0.20085 LAYER Metal2 ;
    PORT
      LAYER Metal2 ;
        RECT 2962.43 0 2962.69 0.26 ;
    END
  END A_DIN[54]
  PIN A_DOUT[54]
    DIRECTION OUTPUT ;
    USE SIGNAL ;
    ANTENNADIFFAREA 0.988 LAYER Metal2 ;
    PORT
      LAYER Metal2 ;
        RECT 2967.23 0 2967.49 0.26 ;
    END
  END A_DOUT[54]
  PIN A_DIN[55]
    DIRECTION INPUT ;
    USE SIGNAL ;
    ANTENNAMODEL OXIDE1 ;
      ANTENNAGATEAREA 0.20085 LAYER Metal2 ;
    PORT
      LAYER Metal2 ;
        RECT 2972.03 0 2972.29 0.26 ;
    END
  END A_DIN[55]
  PIN A_DOUT[55]
    DIRECTION OUTPUT ;
    USE SIGNAL ;
    ANTENNADIFFAREA 0.988 LAYER Metal2 ;
    PORT
      LAYER Metal2 ;
        RECT 2976.83 0 2977.09 0.26 ;
    END
  END A_DOUT[55]
  PIN A_DIN[56]
    DIRECTION INPUT ;
    USE SIGNAL ;
    ANTENNAMODEL OXIDE1 ;
      ANTENNAGATEAREA 0.20085 LAYER Metal2 ;
    PORT
      LAYER Metal2 ;
        RECT 2981.63 0 2981.89 0.26 ;
    END
  END A_DIN[56]
  PIN A_DOUT[56]
    DIRECTION OUTPUT ;
    USE SIGNAL ;
    ANTENNADIFFAREA 0.988 LAYER Metal2 ;
    PORT
      LAYER Metal2 ;
        RECT 2986.43 0 2986.69 0.26 ;
    END
  END A_DOUT[56]
  PIN A_DIN[57]
    DIRECTION INPUT ;
    USE SIGNAL ;
    ANTENNAMODEL OXIDE1 ;
      ANTENNAGATEAREA 0.20085 LAYER Metal2 ;
    PORT
      LAYER Metal2 ;
        RECT 2991.23 0 2991.49 0.26 ;
    END
  END A_DIN[57]
  PIN A_DOUT[57]
    DIRECTION OUTPUT ;
    USE SIGNAL ;
    ANTENNADIFFAREA 0.988 LAYER Metal2 ;
    PORT
      LAYER Metal2 ;
        RECT 2996.03 0 2996.29 0.26 ;
    END
  END A_DOUT[57]
  PIN A_DIN[58]
    DIRECTION INPUT ;
    USE SIGNAL ;
    ANTENNAMODEL OXIDE1 ;
      ANTENNAGATEAREA 0.20085 LAYER Metal2 ;
    PORT
      LAYER Metal2 ;
        RECT 3000.83 0 3001.09 0.26 ;
    END
  END A_DIN[58]
  PIN A_DOUT[58]
    DIRECTION OUTPUT ;
    USE SIGNAL ;
    ANTENNADIFFAREA 0.988 LAYER Metal2 ;
    PORT
      LAYER Metal2 ;
        RECT 3005.63 0 3005.89 0.26 ;
    END
  END A_DOUT[58]
  PIN A_DIN[59]
    DIRECTION INPUT ;
    USE SIGNAL ;
    ANTENNAMODEL OXIDE1 ;
      ANTENNAGATEAREA 0.20085 LAYER Metal2 ;
    PORT
      LAYER Metal2 ;
        RECT 3010.43 0 3010.69 0.26 ;
    END
  END A_DIN[59]
  PIN A_DOUT[59]
    DIRECTION OUTPUT ;
    USE SIGNAL ;
    ANTENNADIFFAREA 0.988 LAYER Metal2 ;
    PORT
      LAYER Metal2 ;
        RECT 3015.23 0 3015.49 0.26 ;
    END
  END A_DOUT[59]
  PIN A_DIN[60]
    DIRECTION INPUT ;
    USE SIGNAL ;
    ANTENNAMODEL OXIDE1 ;
      ANTENNAGATEAREA 0.20085 LAYER Metal2 ;
    PORT
      LAYER Metal2 ;
        RECT 3020.03 0 3020.29 0.26 ;
    END
  END A_DIN[60]
  PIN A_DOUT[60]
    DIRECTION OUTPUT ;
    USE SIGNAL ;
    ANTENNADIFFAREA 0.988 LAYER Metal2 ;
    PORT
      LAYER Metal2 ;
        RECT 3024.83 0 3025.09 0.26 ;
    END
  END A_DOUT[60]
  PIN A_DIN[61]
    DIRECTION INPUT ;
    USE SIGNAL ;
    ANTENNAMODEL OXIDE1 ;
      ANTENNAGATEAREA 0.20085 LAYER Metal2 ;
    PORT
      LAYER Metal2 ;
        RECT 3029.63 0 3029.89 0.26 ;
    END
  END A_DIN[61]
  PIN A_DOUT[61]
    DIRECTION OUTPUT ;
    USE SIGNAL ;
    ANTENNADIFFAREA 0.988 LAYER Metal2 ;
    PORT
      LAYER Metal2 ;
        RECT 3034.43 0 3034.69 0.26 ;
    END
  END A_DOUT[61]
  PIN A_DIN[62]
    DIRECTION INPUT ;
    USE SIGNAL ;
    ANTENNAMODEL OXIDE1 ;
      ANTENNAGATEAREA 0.20085 LAYER Metal2 ;
    PORT
      LAYER Metal2 ;
        RECT 3039.23 0 3039.49 0.26 ;
    END
  END A_DIN[62]
  PIN A_DOUT[62]
    DIRECTION OUTPUT ;
    USE SIGNAL ;
    ANTENNADIFFAREA 0.988 LAYER Metal2 ;
    PORT
      LAYER Metal2 ;
        RECT 3044.03 0 3044.29 0.26 ;
    END
  END A_DOUT[62]
  PIN A_DIN[63]
    DIRECTION INPUT ;
    USE SIGNAL ;
    ANTENNAMODEL OXIDE1 ;
      ANTENNAGATEAREA 0.20085 LAYER Metal2 ;
    PORT
      LAYER Metal2 ;
        RECT 3048.83 0 3049.09 0.26 ;
    END
  END A_DIN[63]
  PIN A_DOUT[63]
    DIRECTION OUTPUT ;
    USE SIGNAL ;
    ANTENNADIFFAREA 0.988 LAYER Metal2 ;
    PORT
      LAYER Metal2 ;
        RECT 3053.63 0 3053.89 0.26 ;
    END
  END A_DOUT[63]
  PIN A_DIN[64]
    DIRECTION INPUT ;
    USE SIGNAL ;
    ANTENNAMODEL OXIDE1 ;
      ANTENNAGATEAREA 0.20085 LAYER Metal2 ;
    PORT
      LAYER Metal2 ;
        RECT 3058.43 0 3058.69 0.26 ;
    END
  END A_DIN[64]
  PIN A_DOUT[64]
    DIRECTION OUTPUT ;
    USE SIGNAL ;
    ANTENNADIFFAREA 0.988 LAYER Metal2 ;
    PORT
      LAYER Metal2 ;
        RECT 3063.23 0 3063.49 0.26 ;
    END
  END A_DOUT[64]
  PIN A_DIN[65]
    DIRECTION INPUT ;
    USE SIGNAL ;
    ANTENNAMODEL OXIDE1 ;
      ANTENNAGATEAREA 0.20085 LAYER Metal2 ;
    PORT
      LAYER Metal2 ;
        RECT 3068.03 0 3068.29 0.26 ;
    END
  END A_DIN[65]
  PIN A_DOUT[65]
    DIRECTION OUTPUT ;
    USE SIGNAL ;
    ANTENNADIFFAREA 0.988 LAYER Metal2 ;
    PORT
      LAYER Metal2 ;
        RECT 3072.83 0 3073.09 0.26 ;
    END
  END A_DOUT[65]
  PIN A_DIN[66]
    DIRECTION INPUT ;
    USE SIGNAL ;
    ANTENNAMODEL OXIDE1 ;
      ANTENNAGATEAREA 0.20085 LAYER Metal2 ;
    PORT
      LAYER Metal2 ;
        RECT 3077.63 0 3077.89 0.26 ;
    END
  END A_DIN[66]
  PIN A_DOUT[66]
    DIRECTION OUTPUT ;
    USE SIGNAL ;
    ANTENNADIFFAREA 0.988 LAYER Metal2 ;
    PORT
      LAYER Metal2 ;
        RECT 3082.43 0 3082.69 0.26 ;
    END
  END A_DOUT[66]
  PIN A_DIN[67]
    DIRECTION INPUT ;
    USE SIGNAL ;
    ANTENNAMODEL OXIDE1 ;
      ANTENNAGATEAREA 0.20085 LAYER Metal2 ;
    PORT
      LAYER Metal2 ;
        RECT 3087.23 0 3087.49 0.26 ;
    END
  END A_DIN[67]
  PIN A_DOUT[67]
    DIRECTION OUTPUT ;
    USE SIGNAL ;
    ANTENNADIFFAREA 0.988 LAYER Metal2 ;
    PORT
      LAYER Metal2 ;
        RECT 3092.03 0 3092.29 0.26 ;
    END
  END A_DOUT[67]
  PIN A_DIN[68]
    DIRECTION INPUT ;
    USE SIGNAL ;
    ANTENNAMODEL OXIDE1 ;
      ANTENNAGATEAREA 0.20085 LAYER Metal2 ;
    PORT
      LAYER Metal2 ;
        RECT 3096.83 0 3097.09 0.26 ;
    END
  END A_DIN[68]
  PIN A_DOUT[68]
    DIRECTION OUTPUT ;
    USE SIGNAL ;
    ANTENNADIFFAREA 0.988 LAYER Metal2 ;
    PORT
      LAYER Metal2 ;
        RECT 3101.63 0 3101.89 0.26 ;
    END
  END A_DOUT[68]
  PIN A_DIN[69]
    DIRECTION INPUT ;
    USE SIGNAL ;
    ANTENNAMODEL OXIDE1 ;
      ANTENNAGATEAREA 0.20085 LAYER Metal2 ;
    PORT
      LAYER Metal2 ;
        RECT 3106.43 0 3106.69 0.26 ;
    END
  END A_DIN[69]
  PIN A_DOUT[69]
    DIRECTION OUTPUT ;
    USE SIGNAL ;
    ANTENNADIFFAREA 0.988 LAYER Metal2 ;
    PORT
      LAYER Metal2 ;
        RECT 3111.23 0 3111.49 0.26 ;
    END
  END A_DOUT[69]
  PIN A_DIN[70]
    DIRECTION INPUT ;
    USE SIGNAL ;
    ANTENNAMODEL OXIDE1 ;
      ANTENNAGATEAREA 0.20085 LAYER Metal2 ;
    PORT
      LAYER Metal2 ;
        RECT 3116.03 0 3116.29 0.26 ;
    END
  END A_DIN[70]
  PIN A_DOUT[70]
    DIRECTION OUTPUT ;
    USE SIGNAL ;
    ANTENNADIFFAREA 0.988 LAYER Metal2 ;
    PORT
      LAYER Metal2 ;
        RECT 3120.83 0 3121.09 0.26 ;
    END
  END A_DOUT[70]
  PIN A_DIN[71]
    DIRECTION INPUT ;
    USE SIGNAL ;
    ANTENNAMODEL OXIDE1 ;
      ANTENNAGATEAREA 0.20085 LAYER Metal2 ;
    PORT
      LAYER Metal2 ;
        RECT 3125.63 0 3125.89 0.26 ;
    END
  END A_DIN[71]
  PIN A_DOUT[71]
    DIRECTION OUTPUT ;
    USE SIGNAL ;
    ANTENNADIFFAREA 0.988 LAYER Metal2 ;
    PORT
      LAYER Metal2 ;
        RECT 3130.43 0 3130.69 0.26 ;
    END
  END A_DOUT[71]
  PIN A_DLY
    DIRECTION INPUT ;
    USE SIGNAL ;
    ANTENNAMODEL OXIDE1 ;
      ANTENNAGATEAREA 0.20085 LAYER Metal2 ;
    PORT
      LAYER Metal2 ;
        RECT 3135.23 0 3135.49 0.26 ;
    END
  END A_DLY
  PIN A_ADDR[0]
    DIRECTION INPUT ;
    USE SIGNAL ;
    ANTENNAMODEL OXIDE1 ;
      ANTENNAGATEAREA 0.20085 LAYER Metal2 ;
    PORT
      LAYER Metal2 ;
        RECT 3140.03 0 3140.29 0.26 ;
    END
  END A_ADDR[0]
  PIN A_ADDR[1]
    DIRECTION INPUT ;
    USE SIGNAL ;
    ANTENNAMODEL OXIDE1 ;
      ANTENNAGATEAREA 0.20085 LAYER Metal2 ;
    PORT
      LAYER Metal2 ;
        RECT 3144.83 0 3145.09 0.26 ;
    END
  END A_ADDR[1]
  PIN A_ADDR[2]
    DIRECTION INPUT ;
    USE SIGNAL ;
    ANTENNAMODEL OXIDE1 ;
      ANTENNAGATEAREA 0.20085 LAYER Metal2 ;
    PORT
      LAYER Metal2 ;
        RECT 3149.63 0 3149.89 0.26 ;
    END
  END A_ADDR[2]
  PIN A_ADDR[3]
    DIRECTION INPUT ;
    USE SIGNAL ;
    ANTENNAMODEL OXIDE1 ;
      ANTENNAGATEAREA 0.20085 LAYER Metal2 ;
    PORT
      LAYER Metal2 ;
        RECT 3154.43 0 3154.69 0.26 ;
    END
  END A_ADDR[3]
  PIN A_ADDR[4]
    DIRECTION INPUT ;
    USE SIGNAL ;
    ANTENNAMODEL OXIDE1 ;
      ANTENNAGATEAREA 0.20085 LAYER Metal2 ;
    PORT
      LAYER Metal2 ;
        RECT 3159.23 0 3159.49 0.26 ;
    END
  END A_ADDR[4]
  PIN A_ADDR[5]
    DIRECTION INPUT ;
    USE SIGNAL ;
    ANTENNAMODEL OXIDE1 ;
      ANTENNAGATEAREA 0.20085 LAYER Metal2 ;
    PORT
      LAYER Metal2 ;
        RECT 3164.03 0 3164.29 0.26 ;
    END
  END A_ADDR[5]
  PIN A_ADDR[6]
    DIRECTION INPUT ;
    USE SIGNAL ;
    ANTENNAMODEL OXIDE1 ;
      ANTENNAGATEAREA 0.20085 LAYER Metal2 ;
    PORT
      LAYER Metal2 ;
        RECT 3168.83 0 3169.09 0.26 ;
    END
  END A_ADDR[6]
  PIN A_ADDR[7]
    DIRECTION INPUT ;
    USE SIGNAL ;
    ANTENNAMODEL OXIDE1 ;
      ANTENNAGATEAREA 0.20085 LAYER Metal2 ;
    PORT
      LAYER Metal2 ;
        RECT 3173.63 0 3173.89 0.26 ;
    END
  END A_ADDR[7]
  PIN A_ADDR[8]
    DIRECTION INPUT ;
    USE SIGNAL ;
    ANTENNAMODEL OXIDE1 ;
      ANTENNAGATEAREA 0.20085 LAYER Metal2 ;
    PORT
      LAYER Metal2 ;
        RECT 3178.43 0 3178.69 0.26 ;
    END
  END A_ADDR[8]
  PIN A_ADDR[9]
    DIRECTION INPUT ;
    USE SIGNAL ;
    ANTENNAMODEL OXIDE1 ;
      ANTENNAGATEAREA 0.20085 LAYER Metal2 ;
    PORT
      LAYER Metal2 ;
        RECT 3183.23 0 3183.49 0.26 ;
    END
  END A_ADDR[9]
  PIN A_ADDR[10]
    DIRECTION INPUT ;
    USE SIGNAL ;
    ANTENNAMODEL OXIDE1 ;
      ANTENNAGATEAREA 0.20085 LAYER Metal2 ;
    PORT
      LAYER Metal2 ;
        RECT 3188.03 0 3188.29 0.26 ;
    END
  END A_ADDR[10]
  PIN A_ADDR[11]
    DIRECTION INPUT ;
    USE SIGNAL ;
    ANTENNAMODEL OXIDE1 ;
      ANTENNAGATEAREA 0.20085 LAYER Metal2 ;
    PORT
      LAYER Metal2 ;
        RECT 3192.83 0 3193.09 0.26 ;
    END
  END A_ADDR[11]
  PIN A_ADDR[12]
    DIRECTION INPUT ;
    USE SIGNAL ;
    ANTENNAMODEL OXIDE1 ;
      ANTENNAGATEAREA 0.20085 LAYER Metal2 ;
    PORT
      LAYER Metal2 ;
        RECT 3197.63 0 3197.89 0.26 ;
    END
  END A_ADDR[12]
  PIN A_ADDR[13]
    DIRECTION INPUT ;
    USE SIGNAL ;
    ANTENNAMODEL OXIDE1 ;
      ANTENNAGATEAREA 0.20085 LAYER Metal2 ;
    PORT
      LAYER Metal2 ;
        RECT 3202.43 0 3202.69 0.26 ;
    END
  END A_ADDR[13]
  PIN A_ADDR[14]
    DIRECTION INPUT ;
    USE SIGNAL ;
    ANTENNAMODEL OXIDE1 ;
      ANTENNAGATEAREA 0.20085 LAYER Metal2 ;
    PORT
      LAYER Metal2 ;
        RECT 3207.23 0 3207.49 0.26 ;
    END
  END A_ADDR[14]
  PIN A_ADDR[15]
    DIRECTION INPUT ;
    USE SIGNAL ;
    ANTENNAMODEL OXIDE1 ;
      ANTENNAGATEAREA 0.20085 LAYER Metal2 ;
    PORT
      LAYER Metal2 ;
        RECT 3212.03 0 3212.29 0.26 ;
    END
  END A_ADDR[15]
  PIN A_ADDR[16]
    DIRECTION INPUT ;
    USE SIGNAL ;
    ANTENNAMODEL OXIDE1 ;
      ANTENNAGATEAREA 0.20085 LAYER Metal2 ;
    PORT
      LAYER Metal2 ;
        RECT 3216.83 0 3217.09 0.26 ;
    END
  END A_ADDR[16]
  PIN A_WEN
    DIRECTION INPUT ;
    USE SIGNAL ;
    ANTENNAMODEL OXIDE1 ;
      ANTENNAGATEAREA 0.20085 LAYER Metal2 ;
    PORT
      LAYER Metal2 ;
        RECT 3221.63 0 3221.89 0.26 ;
    END
  END A_WEN
  PIN A_REN
    DIRECTION INPUT ;
    USE SIGNAL ;
    ANTENNAMODEL OXIDE1 ;
      ANTENNAGATEAREA 0.20085 LAYER Metal2 ;
    PORT
      LAYER Metal2 ;
        RECT 3226.43 0 3226.69 0.26 ;
    END
  END A_REN
  PIN A_MEN
    DIRECTION INPUT ;
    USE SIGNAL ;
    ANTENNAMODEL OXIDE1 ;
      ANTENNAGATEAREA 0.20085 LAYER Metal2 ;
    PORT
      LAYER Metal2 ;
        RECT 3231.23 0 3231.49 0.26 ;
    END
  END A_MEN
  PIN A_CLK
    DIRECTION INPUT ;
    USE SIGNAL ;
    ANTENNAMODEL OXIDE1 ;
      ANTENNAGATEAREA 0.20085 LAYER Metal2 ;
    PORT
      LAYER Metal2 ;
        RECT 3236.03 0 3236.29 0.26 ;
    END
  END A_CLK
  PIN A_DIN[72]
    DIRECTION INPUT ;
    USE SIGNAL ;
    ANTENNAMODEL OXIDE1 ;
      ANTENNAGATEAREA 0.20085 LAYER Metal2 ;
    PORT
      LAYER Metal2 ;
        RECT 3240.83 0 3241.09 0.26 ;
    END
  END A_DIN[72]
  PIN A_DOUT[72]
    DIRECTION OUTPUT ;
    USE SIGNAL ;
    ANTENNADIFFAREA 0.988 LAYER Metal2 ;
    PORT
      LAYER Metal2 ;
        RECT 3245.63 0 3245.89 0.26 ;
    END
  END A_DOUT[72]
  PIN A_DIN[73]
    DIRECTION INPUT ;
    USE SIGNAL ;
    ANTENNAMODEL OXIDE1 ;
      ANTENNAGATEAREA 0.20085 LAYER Metal2 ;
    PORT
      LAYER Metal2 ;
        RECT 3250.43 0 3250.69 0.26 ;
    END
  END A_DIN[73]
  PIN A_DOUT[73]
    DIRECTION OUTPUT ;
    USE SIGNAL ;
    ANTENNADIFFAREA 0.988 LAYER Metal2 ;
    PORT
      LAYER Metal2 ;
        RECT 3255.23 0 3255.49 0.26 ;
    END
  END A_DOUT[73]
  PIN A_DIN[74]
    DIRECTION INPUT ;
    USE SIGNAL ;
    ANTENNAMODEL OXIDE1 ;
      ANTENNAGATEAREA 0.20085 LAYER Metal2 ;
    PORT
      LAYER Metal2 ;
        RECT 3260.03 0 3260.29 0.26 ;
    END
  END A_DIN[74]
  PIN A_DOUT[74]
    DIRECTION OUTPUT ;
    USE SIGNAL ;
    ANTENNADIFFAREA 0.988 LAYER Metal2 ;
    PORT
      LAYER Metal2 ;
        RECT 3264.83 0 3265.09 0.26 ;
    END
  END A_DOUT[74]
  PIN A_DIN[75]
    DIRECTION INPUT ;
    USE SIGNAL ;
    ANTENNAMODEL OXIDE1 ;
      ANTENNAGATEAREA 0.20085 LAYER Metal2 ;
    PORT
      LAYER Metal2 ;
        RECT 3269.63 0 3269.89 0.26 ;
    END
  END A_DIN[75]
  PIN A_DOUT[75]
    DIRECTION OUTPUT ;
    USE SIGNAL ;
    ANTENNADIFFAREA 0.988 LAYER Metal2 ;
    PORT
      LAYER Metal2 ;
        RECT 3274.43 0 3274.69 0.26 ;
    END
  END A_DOUT[75]
  PIN A_DIN[76]
    DIRECTION INPUT ;
    USE SIGNAL ;
    ANTENNAMODEL OXIDE1 ;
      ANTENNAGATEAREA 0.20085 LAYER Metal2 ;
    PORT
      LAYER Metal2 ;
        RECT 3279.23 0 3279.49 0.26 ;
    END
  END A_DIN[76]
  PIN A_DOUT[76]
    DIRECTION OUTPUT ;
    USE SIGNAL ;
    ANTENNADIFFAREA 0.988 LAYER Metal2 ;
    PORT
      LAYER Metal2 ;
        RECT 3284.03 0 3284.29 0.26 ;
    END
  END A_DOUT[76]
  PIN A_DIN[77]
    DIRECTION INPUT ;
    USE SIGNAL ;
    ANTENNAMODEL OXIDE1 ;
      ANTENNAGATEAREA 0.20085 LAYER Metal2 ;
    PORT
      LAYER Metal2 ;
        RECT 3288.83 0 3289.09 0.26 ;
    END
  END A_DIN[77]
  PIN A_DOUT[77]
    DIRECTION OUTPUT ;
    USE SIGNAL ;
    ANTENNADIFFAREA 0.988 LAYER Metal2 ;
    PORT
      LAYER Metal2 ;
        RECT 3293.63 0 3293.89 0.26 ;
    END
  END A_DOUT[77]
  PIN A_DIN[78]
    DIRECTION INPUT ;
    USE SIGNAL ;
    ANTENNAMODEL OXIDE1 ;
      ANTENNAGATEAREA 0.20085 LAYER Metal2 ;
    PORT
      LAYER Metal2 ;
        RECT 3298.43 0 3298.69 0.26 ;
    END
  END A_DIN[78]
  PIN A_DOUT[78]
    DIRECTION OUTPUT ;
    USE SIGNAL ;
    ANTENNADIFFAREA 0.988 LAYER Metal2 ;
    PORT
      LAYER Metal2 ;
        RECT 3303.23 0 3303.49 0.26 ;
    END
  END A_DOUT[78]
  PIN A_DIN[79]
    DIRECTION INPUT ;
    USE SIGNAL ;
    ANTENNAMODEL OXIDE1 ;
      ANTENNAGATEAREA 0.20085 LAYER Metal2 ;
    PORT
      LAYER Metal2 ;
        RECT 3308.03 0 3308.29 0.26 ;
    END
  END A_DIN[79]
  PIN A_DOUT[79]
    DIRECTION OUTPUT ;
    USE SIGNAL ;
    ANTENNADIFFAREA 0.988 LAYER Metal2 ;
    PORT
      LAYER Metal2 ;
        RECT 3312.83 0 3313.09 0.26 ;
    END
  END A_DOUT[79]
  PIN A_DIN[80]
    DIRECTION INPUT ;
    USE SIGNAL ;
    ANTENNAMODEL OXIDE1 ;
      ANTENNAGATEAREA 0.20085 LAYER Metal2 ;
    PORT
      LAYER Metal2 ;
        RECT 3317.63 0 3317.89 0.26 ;
    END
  END A_DIN[80]
  PIN A_DOUT[80]
    DIRECTION OUTPUT ;
    USE SIGNAL ;
    ANTENNADIFFAREA 0.988 LAYER Metal2 ;
    PORT
      LAYER Metal2 ;
        RECT 3322.43 0 3322.69 0.26 ;
    END
  END A_DOUT[80]
  PIN A_DIN[81]
    DIRECTION INPUT ;
    USE SIGNAL ;
    ANTENNAMODEL OXIDE1 ;
      ANTENNAGATEAREA 0.20085 LAYER Metal2 ;
    PORT
      LAYER Metal2 ;
        RECT 3327.23 0 3327.49 0.26 ;
    END
  END A_DIN[81]
  PIN A_DOUT[81]
    DIRECTION OUTPUT ;
    USE SIGNAL ;
    ANTENNADIFFAREA 0.988 LAYER Metal2 ;
    PORT
      LAYER Metal2 ;
        RECT 3332.03 0 3332.29 0.26 ;
    END
  END A_DOUT[81]
  PIN A_DIN[82]
    DIRECTION INPUT ;
    USE SIGNAL ;
    ANTENNAMODEL OXIDE1 ;
      ANTENNAGATEAREA 0.20085 LAYER Metal2 ;
    PORT
      LAYER Metal2 ;
        RECT 3336.83 0 3337.09 0.26 ;
    END
  END A_DIN[82]
  PIN A_DOUT[82]
    DIRECTION OUTPUT ;
    USE SIGNAL ;
    ANTENNADIFFAREA 0.988 LAYER Metal2 ;
    PORT
      LAYER Metal2 ;
        RECT 3341.63 0 3341.89 0.26 ;
    END
  END A_DOUT[82]
  PIN A_DIN[83]
    DIRECTION INPUT ;
    USE SIGNAL ;
    ANTENNAMODEL OXIDE1 ;
      ANTENNAGATEAREA 0.20085 LAYER Metal2 ;
    PORT
      LAYER Metal2 ;
        RECT 3346.43 0 3346.69 0.26 ;
    END
  END A_DIN[83]
  PIN A_DOUT[83]
    DIRECTION OUTPUT ;
    USE SIGNAL ;
    ANTENNADIFFAREA 0.988 LAYER Metal2 ;
    PORT
      LAYER Metal2 ;
        RECT 3351.23 0 3351.49 0.26 ;
    END
  END A_DOUT[83]
  PIN A_DIN[84]
    DIRECTION INPUT ;
    USE SIGNAL ;
    ANTENNAMODEL OXIDE1 ;
      ANTENNAGATEAREA 0.20085 LAYER Metal2 ;
    PORT
      LAYER Metal2 ;
        RECT 3356.03 0 3356.29 0.26 ;
    END
  END A_DIN[84]
  PIN A_DOUT[84]
    DIRECTION OUTPUT ;
    USE SIGNAL ;
    ANTENNADIFFAREA 0.988 LAYER Metal2 ;
    PORT
      LAYER Metal2 ;
        RECT 3360.83 0 3361.09 0.26 ;
    END
  END A_DOUT[84]
  PIN A_DIN[85]
    DIRECTION INPUT ;
    USE SIGNAL ;
    ANTENNAMODEL OXIDE1 ;
      ANTENNAGATEAREA 0.20085 LAYER Metal2 ;
    PORT
      LAYER Metal2 ;
        RECT 3365.63 0 3365.89 0.26 ;
    END
  END A_DIN[85]
  PIN A_DOUT[85]
    DIRECTION OUTPUT ;
    USE SIGNAL ;
    ANTENNADIFFAREA 0.988 LAYER Metal2 ;
    PORT
      LAYER Metal2 ;
        RECT 3370.43 0 3370.69 0.26 ;
    END
  END A_DOUT[85]
  PIN A_DIN[86]
    DIRECTION INPUT ;
    USE SIGNAL ;
    ANTENNAMODEL OXIDE1 ;
      ANTENNAGATEAREA 0.20085 LAYER Metal2 ;
    PORT
      LAYER Metal2 ;
        RECT 3375.23 0 3375.49 0.26 ;
    END
  END A_DIN[86]
  PIN A_DOUT[86]
    DIRECTION OUTPUT ;
    USE SIGNAL ;
    ANTENNADIFFAREA 0.988 LAYER Metal2 ;
    PORT
      LAYER Metal2 ;
        RECT 3380.03 0 3380.29 0.26 ;
    END
  END A_DOUT[86]
  PIN A_DIN[87]
    DIRECTION INPUT ;
    USE SIGNAL ;
    ANTENNAMODEL OXIDE1 ;
      ANTENNAGATEAREA 0.20085 LAYER Metal2 ;
    PORT
      LAYER Metal2 ;
        RECT 3384.83 0 3385.09 0.26 ;
    END
  END A_DIN[87]
  PIN A_DOUT[87]
    DIRECTION OUTPUT ;
    USE SIGNAL ;
    ANTENNADIFFAREA 0.988 LAYER Metal2 ;
    PORT
      LAYER Metal2 ;
        RECT 3389.63 0 3389.89 0.26 ;
    END
  END A_DOUT[87]
  PIN A_DIN[88]
    DIRECTION INPUT ;
    USE SIGNAL ;
    ANTENNAMODEL OXIDE1 ;
      ANTENNAGATEAREA 0.20085 LAYER Metal2 ;
    PORT
      LAYER Metal2 ;
        RECT 3394.43 0 3394.69 0.26 ;
    END
  END A_DIN[88]
  PIN A_DOUT[88]
    DIRECTION OUTPUT ;
    USE SIGNAL ;
    ANTENNADIFFAREA 0.988 LAYER Metal2 ;
    PORT
      LAYER Metal2 ;
        RECT 3399.23 0 3399.49 0.26 ;
    END
  END A_DOUT[88]
  PIN A_DIN[89]
    DIRECTION INPUT ;
    USE SIGNAL ;
    ANTENNAMODEL OXIDE1 ;
      ANTENNAGATEAREA 0.20085 LAYER Metal2 ;
    PORT
      LAYER Metal2 ;
        RECT 3404.03 0 3404.29 0.26 ;
    END
  END A_DIN[89]
  PIN A_DOUT[89]
    DIRECTION OUTPUT ;
    USE SIGNAL ;
    ANTENNADIFFAREA 0.988 LAYER Metal2 ;
    PORT
      LAYER Metal2 ;
        RECT 3408.83 0 3409.09 0.26 ;
    END
  END A_DOUT[89]
  PIN A_DIN[90]
    DIRECTION INPUT ;
    USE SIGNAL ;
    ANTENNAMODEL OXIDE1 ;
      ANTENNAGATEAREA 0.20085 LAYER Metal2 ;
    PORT
      LAYER Metal2 ;
        RECT 3413.63 0 3413.89 0.26 ;
    END
  END A_DIN[90]
  PIN A_DOUT[90]
    DIRECTION OUTPUT ;
    USE SIGNAL ;
    ANTENNADIFFAREA 0.988 LAYER Metal2 ;
    PORT
      LAYER Metal2 ;
        RECT 3418.43 0 3418.69 0.26 ;
    END
  END A_DOUT[90]
  PIN A_DIN[91]
    DIRECTION INPUT ;
    USE SIGNAL ;
    ANTENNAMODEL OXIDE1 ;
      ANTENNAGATEAREA 0.20085 LAYER Metal2 ;
    PORT
      LAYER Metal2 ;
        RECT 3423.23 0 3423.49 0.26 ;
    END
  END A_DIN[91]
  PIN A_DOUT[91]
    DIRECTION OUTPUT ;
    USE SIGNAL ;
    ANTENNADIFFAREA 0.988 LAYER Metal2 ;
    PORT
      LAYER Metal2 ;
        RECT 3428.03 0 3428.29 0.26 ;
    END
  END A_DOUT[91]
  PIN A_DIN[92]
    DIRECTION INPUT ;
    USE SIGNAL ;
    ANTENNAMODEL OXIDE1 ;
      ANTENNAGATEAREA 0.20085 LAYER Metal2 ;
    PORT
      LAYER Metal2 ;
        RECT 3432.83 0 3433.09 0.26 ;
    END
  END A_DIN[92]
  PIN A_DOUT[92]
    DIRECTION OUTPUT ;
    USE SIGNAL ;
    ANTENNADIFFAREA 0.988 LAYER Metal2 ;
    PORT
      LAYER Metal2 ;
        RECT 3437.63 0 3437.89 0.26 ;
    END
  END A_DOUT[92]
  PIN A_DIN[93]
    DIRECTION INPUT ;
    USE SIGNAL ;
    ANTENNAMODEL OXIDE1 ;
      ANTENNAGATEAREA 0.20085 LAYER Metal2 ;
    PORT
      LAYER Metal2 ;
        RECT 3442.43 0 3442.69 0.26 ;
    END
  END A_DIN[93]
  PIN A_DOUT[93]
    DIRECTION OUTPUT ;
    USE SIGNAL ;
    ANTENNADIFFAREA 0.988 LAYER Metal2 ;
    PORT
      LAYER Metal2 ;
        RECT 3447.23 0 3447.49 0.26 ;
    END
  END A_DOUT[93]
  PIN A_DIN[94]
    DIRECTION INPUT ;
    USE SIGNAL ;
    ANTENNAMODEL OXIDE1 ;
      ANTENNAGATEAREA 0.20085 LAYER Metal2 ;
    PORT
      LAYER Metal2 ;
        RECT 3452.03 0 3452.29 0.26 ;
    END
  END A_DIN[94]
  PIN A_DOUT[94]
    DIRECTION OUTPUT ;
    USE SIGNAL ;
    ANTENNADIFFAREA 0.988 LAYER Metal2 ;
    PORT
      LAYER Metal2 ;
        RECT 3456.83 0 3457.09 0.26 ;
    END
  END A_DOUT[94]
  PIN A_DIN[95]
    DIRECTION INPUT ;
    USE SIGNAL ;
    ANTENNAMODEL OXIDE1 ;
      ANTENNAGATEAREA 0.20085 LAYER Metal2 ;
    PORT
      LAYER Metal2 ;
        RECT 3461.63 0 3461.89 0.26 ;
    END
  END A_DIN[95]
  PIN A_DOUT[95]
    DIRECTION OUTPUT ;
    USE SIGNAL ;
    ANTENNADIFFAREA 0.988 LAYER Metal2 ;
    PORT
      LAYER Metal2 ;
        RECT 3466.43 0 3466.69 0.26 ;
    END
  END A_DOUT[95]
  PIN A_DIN[96]
    DIRECTION INPUT ;
    USE SIGNAL ;
    ANTENNAMODEL OXIDE1 ;
      ANTENNAGATEAREA 0.20085 LAYER Metal2 ;
    PORT
      LAYER Metal2 ;
        RECT 3471.23 0 3471.49 0.26 ;
    END
  END A_DIN[96]
  PIN A_DOUT[96]
    DIRECTION OUTPUT ;
    USE SIGNAL ;
    ANTENNADIFFAREA 0.988 LAYER Metal2 ;
    PORT
      LAYER Metal2 ;
        RECT 3476.03 0 3476.29 0.26 ;
    END
  END A_DOUT[96]
  PIN A_DIN[97]
    DIRECTION INPUT ;
    USE SIGNAL ;
    ANTENNAMODEL OXIDE1 ;
      ANTENNAGATEAREA 0.20085 LAYER Metal2 ;
    PORT
      LAYER Metal2 ;
        RECT 3480.83 0 3481.09 0.26 ;
    END
  END A_DIN[97]
  PIN A_DOUT[97]
    DIRECTION OUTPUT ;
    USE SIGNAL ;
    ANTENNADIFFAREA 0.988 LAYER Metal2 ;
    PORT
      LAYER Metal2 ;
        RECT 3485.63 0 3485.89 0.26 ;
    END
  END A_DOUT[97]
  PIN A_DIN[98]
    DIRECTION INPUT ;
    USE SIGNAL ;
    ANTENNAMODEL OXIDE1 ;
      ANTENNAGATEAREA 0.20085 LAYER Metal2 ;
    PORT
      LAYER Metal2 ;
        RECT 3490.43 0 3490.69 0.26 ;
    END
  END A_DIN[98]
  PIN A_DOUT[98]
    DIRECTION OUTPUT ;
    USE SIGNAL ;
    ANTENNADIFFAREA 0.988 LAYER Metal2 ;
    PORT
      LAYER Metal2 ;
        RECT 3495.23 0 3495.49 0.26 ;
    END
  END A_DOUT[98]
  PIN A_DIN[99]
    DIRECTION INPUT ;
    USE SIGNAL ;
    ANTENNAMODEL OXIDE1 ;
      ANTENNAGATEAREA 0.20085 LAYER Metal2 ;
    PORT
      LAYER Metal2 ;
        RECT 3500.03 0 3500.29 0.26 ;
    END
  END A_DIN[99]
  PIN A_DOUT[99]
    DIRECTION OUTPUT ;
    USE SIGNAL ;
    ANTENNADIFFAREA 0.988 LAYER Metal2 ;
    PORT
      LAYER Metal2 ;
        RECT 3504.83 0 3505.09 0.26 ;
    END
  END A_DOUT[99]
  PIN A_DIN[100]
    DIRECTION INPUT ;
    USE SIGNAL ;
    ANTENNAMODEL OXIDE1 ;
      ANTENNAGATEAREA 0.20085 LAYER Metal2 ;
    PORT
      LAYER Metal2 ;
        RECT 3509.63 0 3509.89 0.26 ;
    END
  END A_DIN[100]
  PIN A_DOUT[100]
    DIRECTION OUTPUT ;
    USE SIGNAL ;
    ANTENNADIFFAREA 0.988 LAYER Metal2 ;
    PORT
      LAYER Metal2 ;
        RECT 3514.43 0 3514.69 0.26 ;
    END
  END A_DOUT[100]
  PIN A_DIN[101]
    DIRECTION INPUT ;
    USE SIGNAL ;
    ANTENNAMODEL OXIDE1 ;
      ANTENNAGATEAREA 0.20085 LAYER Metal2 ;
    PORT
      LAYER Metal2 ;
        RECT 3519.23 0 3519.49 0.26 ;
    END
  END A_DIN[101]
  PIN A_DOUT[101]
    DIRECTION OUTPUT ;
    USE SIGNAL ;
    ANTENNADIFFAREA 0.988 LAYER Metal2 ;
    PORT
      LAYER Metal2 ;
        RECT 3524.03 0 3524.29 0.26 ;
    END
  END A_DOUT[101]
  PIN A_DIN[102]
    DIRECTION INPUT ;
    USE SIGNAL ;
    ANTENNAMODEL OXIDE1 ;
      ANTENNAGATEAREA 0.20085 LAYER Metal2 ;
    PORT
      LAYER Metal2 ;
        RECT 3528.83 0 3529.09 0.26 ;
    END
  END A_DIN[102]
  PIN A_DOUT[102]
    DIRECTION OUTPUT ;
    USE SIGNAL ;
    ANTENNADIFFAREA 0.988 LAYER Metal2 ;
    PORT
      LAYER Metal2 ;
        RECT 3533.63 0 3533.89 0.26 ;
    END
  END A_DOUT[102]
  PIN A_DIN[103]
    DIRECTION INPUT ;
    USE SIGNAL ;
    ANTENNAMODEL OXIDE1 ;
      ANTENNAGATEAREA 0.20085 LAYER Metal2 ;
    PORT
      LAYER Metal2 ;
        RECT 3538.43 0 3538.69 0.26 ;
    END
  END A_DIN[103]
  PIN A_DOUT[103]
    DIRECTION OUTPUT ;
    USE SIGNAL ;
    ANTENNADIFFAREA 0.988 LAYER Metal2 ;
    PORT
      LAYER Metal2 ;
        RECT 3543.23 0 3543.49 0.26 ;
    END
  END A_DOUT[103]
  PIN A_DIN[104]
    DIRECTION INPUT ;
    USE SIGNAL ;
    ANTENNAMODEL OXIDE1 ;
      ANTENNAGATEAREA 0.20085 LAYER Metal2 ;
    PORT
      LAYER Metal2 ;
        RECT 3548.03 0 3548.29 0.26 ;
    END
  END A_DIN[104]
  PIN A_DOUT[104]
    DIRECTION OUTPUT ;
    USE SIGNAL ;
    ANTENNADIFFAREA 0.988 LAYER Metal2 ;
    PORT
      LAYER Metal2 ;
        RECT 3552.83 0 3553.09 0.26 ;
    END
  END A_DOUT[104]
  PIN A_DIN[105]
    DIRECTION INPUT ;
    USE SIGNAL ;
    ANTENNAMODEL OXIDE1 ;
      ANTENNAGATEAREA 0.20085 LAYER Metal2 ;
    PORT
      LAYER Metal2 ;
        RECT 3557.63 0 3557.89 0.26 ;
    END
  END A_DIN[105]
  PIN A_DOUT[105]
    DIRECTION OUTPUT ;
    USE SIGNAL ;
    ANTENNADIFFAREA 0.988 LAYER Metal2 ;
    PORT
      LAYER Metal2 ;
        RECT 3562.43 0 3562.69 0.26 ;
    END
  END A_DOUT[105]
  PIN A_DIN[106]
    DIRECTION INPUT ;
    USE SIGNAL ;
    ANTENNAMODEL OXIDE1 ;
      ANTENNAGATEAREA 0.20085 LAYER Metal2 ;
    PORT
      LAYER Metal2 ;
        RECT 3567.23 0 3567.49 0.26 ;
    END
  END A_DIN[106]
  PIN A_DOUT[106]
    DIRECTION OUTPUT ;
    USE SIGNAL ;
    ANTENNADIFFAREA 0.988 LAYER Metal2 ;
    PORT
      LAYER Metal2 ;
        RECT 3572.03 0 3572.29 0.26 ;
    END
  END A_DOUT[106]
  PIN A_DIN[107]
    DIRECTION INPUT ;
    USE SIGNAL ;
    ANTENNAMODEL OXIDE1 ;
      ANTENNAGATEAREA 0.20085 LAYER Metal2 ;
    PORT
      LAYER Metal2 ;
        RECT 3576.83 0 3577.09 0.26 ;
    END
  END A_DIN[107]
  PIN A_DOUT[107]
    DIRECTION OUTPUT ;
    USE SIGNAL ;
    ANTENNADIFFAREA 0.988 LAYER Metal2 ;
    PORT
      LAYER Metal2 ;
        RECT 3581.63 0 3581.89 0.26 ;
    END
  END A_DOUT[107]
  PIN A_DIN[108]
    DIRECTION INPUT ;
    USE SIGNAL ;
    ANTENNAMODEL OXIDE1 ;
      ANTENNAGATEAREA 0.20085 LAYER Metal2 ;
    PORT
      LAYER Metal2 ;
        RECT 3586.43 0 3586.69 0.26 ;
    END
  END A_DIN[108]
  PIN A_DOUT[108]
    DIRECTION OUTPUT ;
    USE SIGNAL ;
    ANTENNADIFFAREA 0.988 LAYER Metal2 ;
    PORT
      LAYER Metal2 ;
        RECT 3591.23 0 3591.49 0.26 ;
    END
  END A_DOUT[108]
  PIN A_DIN[109]
    DIRECTION INPUT ;
    USE SIGNAL ;
    ANTENNAMODEL OXIDE1 ;
      ANTENNAGATEAREA 0.20085 LAYER Metal2 ;
    PORT
      LAYER Metal2 ;
        RECT 3596.03 0 3596.29 0.26 ;
    END
  END A_DIN[109]
  PIN A_DOUT[109]
    DIRECTION OUTPUT ;
    USE SIGNAL ;
    ANTENNADIFFAREA 0.988 LAYER Metal2 ;
    PORT
      LAYER Metal2 ;
        RECT 3600.83 0 3601.09 0.26 ;
    END
  END A_DOUT[109]
  PIN A_DIN[110]
    DIRECTION INPUT ;
    USE SIGNAL ;
    ANTENNAMODEL OXIDE1 ;
      ANTENNAGATEAREA 0.20085 LAYER Metal2 ;
    PORT
      LAYER Metal2 ;
        RECT 3605.63 0 3605.89 0.26 ;
    END
  END A_DIN[110]
  PIN A_DOUT[110]
    DIRECTION OUTPUT ;
    USE SIGNAL ;
    ANTENNADIFFAREA 0.988 LAYER Metal2 ;
    PORT
      LAYER Metal2 ;
        RECT 3610.43 0 3610.69 0.26 ;
    END
  END A_DOUT[110]
  PIN A_DIN[111]
    DIRECTION INPUT ;
    USE SIGNAL ;
    ANTENNAMODEL OXIDE1 ;
      ANTENNAGATEAREA 0.20085 LAYER Metal2 ;
    PORT
      LAYER Metal2 ;
        RECT 3615.23 0 3615.49 0.26 ;
    END
  END A_DIN[111]
  PIN A_DOUT[111]
    DIRECTION OUTPUT ;
    USE SIGNAL ;
    ANTENNADIFFAREA 0.988 LAYER Metal2 ;
    PORT
      LAYER Metal2 ;
        RECT 3620.03 0 3620.29 0.26 ;
    END
  END A_DOUT[111]
  PIN A_DIN[112]
    DIRECTION INPUT ;
    USE SIGNAL ;
    ANTENNAMODEL OXIDE1 ;
      ANTENNAGATEAREA 0.20085 LAYER Metal2 ;
    PORT
      LAYER Metal2 ;
        RECT 3624.83 0 3625.09 0.26 ;
    END
  END A_DIN[112]
  PIN A_DOUT[112]
    DIRECTION OUTPUT ;
    USE SIGNAL ;
    ANTENNADIFFAREA 0.988 LAYER Metal2 ;
    PORT
      LAYER Metal2 ;
        RECT 3629.63 0 3629.89 0.26 ;
    END
  END A_DOUT[112]
  PIN A_DIN[113]
    DIRECTION INPUT ;
    USE SIGNAL ;
    ANTENNAMODEL OXIDE1 ;
      ANTENNAGATEAREA 0.20085 LAYER Metal2 ;
    PORT
      LAYER Metal2 ;
        RECT 3634.43 0 3634.69 0.26 ;
    END
  END A_DIN[113]
  PIN A_DOUT[113]
    DIRECTION OUTPUT ;
    USE SIGNAL ;
    ANTENNADIFFAREA 0.988 LAYER Metal2 ;
    PORT
      LAYER Metal2 ;
        RECT 3639.23 0 3639.49 0.26 ;
    END
  END A_DOUT[113]
  PIN A_DIN[114]
    DIRECTION INPUT ;
    USE SIGNAL ;
    ANTENNAMODEL OXIDE1 ;
      ANTENNAGATEAREA 0.20085 LAYER Metal2 ;
    PORT
      LAYER Metal2 ;
        RECT 3644.03 0 3644.29 0.26 ;
    END
  END A_DIN[114]
  PIN A_DOUT[114]
    DIRECTION OUTPUT ;
    USE SIGNAL ;
    ANTENNADIFFAREA 0.988 LAYER Metal2 ;
    PORT
      LAYER Metal2 ;
        RECT 3648.83 0 3649.09 0.26 ;
    END
  END A_DOUT[114]
  PIN A_DIN[115]
    DIRECTION INPUT ;
    USE SIGNAL ;
    ANTENNAMODEL OXIDE1 ;
      ANTENNAGATEAREA 0.20085 LAYER Metal2 ;
    PORT
      LAYER Metal2 ;
        RECT 3653.63 0 3653.89 0.26 ;
    END
  END A_DIN[115]
  PIN A_DOUT[115]
    DIRECTION OUTPUT ;
    USE SIGNAL ;
    ANTENNADIFFAREA 0.988 LAYER Metal2 ;
    PORT
      LAYER Metal2 ;
        RECT 3658.43 0 3658.69 0.26 ;
    END
  END A_DOUT[115]
  PIN A_DIN[116]
    DIRECTION INPUT ;
    USE SIGNAL ;
    ANTENNAMODEL OXIDE1 ;
      ANTENNAGATEAREA 0.20085 LAYER Metal2 ;
    PORT
      LAYER Metal2 ;
        RECT 3663.23 0 3663.49 0.26 ;
    END
  END A_DIN[116]
  PIN A_DOUT[116]
    DIRECTION OUTPUT ;
    USE SIGNAL ;
    ANTENNADIFFAREA 0.988 LAYER Metal2 ;
    PORT
      LAYER Metal2 ;
        RECT 3668.03 0 3668.29 0.26 ;
    END
  END A_DOUT[116]
  PIN A_DIN[117]
    DIRECTION INPUT ;
    USE SIGNAL ;
    ANTENNAMODEL OXIDE1 ;
      ANTENNAGATEAREA 0.20085 LAYER Metal2 ;
    PORT
      LAYER Metal2 ;
        RECT 3672.83 0 3673.09 0.26 ;
    END
  END A_DIN[117]
  PIN A_DOUT[117]
    DIRECTION OUTPUT ;
    USE SIGNAL ;
    ANTENNADIFFAREA 0.988 LAYER Metal2 ;
    PORT
      LAYER Metal2 ;
        RECT 3677.63 0 3677.89 0.26 ;
    END
  END A_DOUT[117]
  PIN A_DIN[118]
    DIRECTION INPUT ;
    USE SIGNAL ;
    ANTENNAMODEL OXIDE1 ;
      ANTENNAGATEAREA 0.20085 LAYER Metal2 ;
    PORT
      LAYER Metal2 ;
        RECT 3682.43 0 3682.69 0.26 ;
    END
  END A_DIN[118]
  PIN A_DOUT[118]
    DIRECTION OUTPUT ;
    USE SIGNAL ;
    ANTENNADIFFAREA 0.988 LAYER Metal2 ;
    PORT
      LAYER Metal2 ;
        RECT 3687.23 0 3687.49 0.26 ;
    END
  END A_DOUT[118]
  PIN A_DIN[119]
    DIRECTION INPUT ;
    USE SIGNAL ;
    ANTENNAMODEL OXIDE1 ;
      ANTENNAGATEAREA 0.20085 LAYER Metal2 ;
    PORT
      LAYER Metal2 ;
        RECT 3692.03 0 3692.29 0.26 ;
    END
  END A_DIN[119]
  PIN A_DOUT[119]
    DIRECTION OUTPUT ;
    USE SIGNAL ;
    ANTENNADIFFAREA 0.988 LAYER Metal2 ;
    PORT
      LAYER Metal2 ;
        RECT 3696.83 0 3697.09 0.26 ;
    END
  END A_DOUT[119]
  PIN A_DIN[120]
    DIRECTION INPUT ;
    USE SIGNAL ;
    ANTENNAMODEL OXIDE1 ;
      ANTENNAGATEAREA 0.20085 LAYER Metal2 ;
    PORT
      LAYER Metal2 ;
        RECT 3701.63 0 3701.89 0.26 ;
    END
  END A_DIN[120]
  PIN A_DOUT[120]
    DIRECTION OUTPUT ;
    USE SIGNAL ;
    ANTENNADIFFAREA 0.988 LAYER Metal2 ;
    PORT
      LAYER Metal2 ;
        RECT 3706.43 0 3706.69 0.26 ;
    END
  END A_DOUT[120]
  PIN A_DIN[121]
    DIRECTION INPUT ;
    USE SIGNAL ;
    ANTENNAMODEL OXIDE1 ;
      ANTENNAGATEAREA 0.20085 LAYER Metal2 ;
    PORT
      LAYER Metal2 ;
        RECT 3711.23 0 3711.49 0.26 ;
    END
  END A_DIN[121]
  PIN A_DOUT[121]
    DIRECTION OUTPUT ;
    USE SIGNAL ;
    ANTENNADIFFAREA 0.988 LAYER Metal2 ;
    PORT
      LAYER Metal2 ;
        RECT 3716.03 0 3716.29 0.26 ;
    END
  END A_DOUT[121]
  PIN A_DIN[122]
    DIRECTION INPUT ;
    USE SIGNAL ;
    ANTENNAMODEL OXIDE1 ;
      ANTENNAGATEAREA 0.20085 LAYER Metal2 ;
    PORT
      LAYER Metal2 ;
        RECT 3720.83 0 3721.09 0.26 ;
    END
  END A_DIN[122]
  PIN A_DOUT[122]
    DIRECTION OUTPUT ;
    USE SIGNAL ;
    ANTENNADIFFAREA 0.988 LAYER Metal2 ;
    PORT
      LAYER Metal2 ;
        RECT 3725.63 0 3725.89 0.26 ;
    END
  END A_DOUT[122]
  PIN A_DIN[123]
    DIRECTION INPUT ;
    USE SIGNAL ;
    ANTENNAMODEL OXIDE1 ;
      ANTENNAGATEAREA 0.20085 LAYER Metal2 ;
    PORT
      LAYER Metal2 ;
        RECT 3730.43 0 3730.69 0.26 ;
    END
  END A_DIN[123]
  PIN A_DOUT[123]
    DIRECTION OUTPUT ;
    USE SIGNAL ;
    ANTENNADIFFAREA 0.988 LAYER Metal2 ;
    PORT
      LAYER Metal2 ;
        RECT 3735.23 0 3735.49 0.26 ;
    END
  END A_DOUT[123]
  PIN A_DIN[124]
    DIRECTION INPUT ;
    USE SIGNAL ;
    ANTENNAMODEL OXIDE1 ;
      ANTENNAGATEAREA 0.20085 LAYER Metal2 ;
    PORT
      LAYER Metal2 ;
        RECT 3740.03 0 3740.29 0.26 ;
    END
  END A_DIN[124]
  PIN A_DOUT[124]
    DIRECTION OUTPUT ;
    USE SIGNAL ;
    ANTENNADIFFAREA 0.988 LAYER Metal2 ;
    PORT
      LAYER Metal2 ;
        RECT 3744.83 0 3745.09 0.26 ;
    END
  END A_DOUT[124]
  PIN A_DIN[125]
    DIRECTION INPUT ;
    USE SIGNAL ;
    ANTENNAMODEL OXIDE1 ;
      ANTENNAGATEAREA 0.20085 LAYER Metal2 ;
    PORT
      LAYER Metal2 ;
        RECT 3749.63 0 3749.89 0.26 ;
    END
  END A_DIN[125]
  PIN A_DOUT[125]
    DIRECTION OUTPUT ;
    USE SIGNAL ;
    ANTENNADIFFAREA 0.988 LAYER Metal2 ;
    PORT
      LAYER Metal2 ;
        RECT 3754.43 0 3754.69 0.26 ;
    END
  END A_DOUT[125]
  PIN A_DIN[126]
    DIRECTION INPUT ;
    USE SIGNAL ;
    ANTENNAMODEL OXIDE1 ;
      ANTENNAGATEAREA 0.20085 LAYER Metal2 ;
    PORT
      LAYER Metal2 ;
        RECT 3759.23 0 3759.49 0.26 ;
    END
  END A_DIN[126]
  PIN A_DOUT[126]
    DIRECTION OUTPUT ;
    USE SIGNAL ;
    ANTENNADIFFAREA 0.988 LAYER Metal2 ;
    PORT
      LAYER Metal2 ;
        RECT 3764.03 0 3764.29 0.26 ;
    END
  END A_DOUT[126]
  PIN A_DIN[127]
    DIRECTION INPUT ;
    USE SIGNAL ;
    ANTENNAMODEL OXIDE1 ;
      ANTENNAGATEAREA 0.20085 LAYER Metal2 ;
    PORT
      LAYER Metal2 ;
        RECT 3768.83 0 3769.09 0.26 ;
    END
  END A_DIN[127]
  PIN A_DOUT[127]
    DIRECTION OUTPUT ;
    USE SIGNAL ;
    ANTENNADIFFAREA 0.988 LAYER Metal2 ;
    PORT
      LAYER Metal2 ;
        RECT 3773.63 0 3773.89 0.26 ;
    END
  END A_DOUT[127]
  PIN A_DIN[128]
    DIRECTION INPUT ;
    USE SIGNAL ;
    ANTENNAMODEL OXIDE1 ;
      ANTENNAGATEAREA 0.20085 LAYER Metal2 ;
    PORT
      LAYER Metal2 ;
        RECT 3778.43 0 3778.69 0.26 ;
    END
  END A_DIN[128]
  PIN A_DOUT[128]
    DIRECTION OUTPUT ;
    USE SIGNAL ;
    ANTENNADIFFAREA 0.988 LAYER Metal2 ;
    PORT
      LAYER Metal2 ;
        RECT 3783.23 0 3783.49 0.26 ;
    END
  END A_DOUT[128]
  PIN A_DIN[129]
    DIRECTION INPUT ;
    USE SIGNAL ;
    ANTENNAMODEL OXIDE1 ;
      ANTENNAGATEAREA 0.20085 LAYER Metal2 ;
    PORT
      LAYER Metal2 ;
        RECT 3788.03 0 3788.29 0.26 ;
    END
  END A_DIN[129]
  PIN A_DOUT[129]
    DIRECTION OUTPUT ;
    USE SIGNAL ;
    ANTENNADIFFAREA 0.988 LAYER Metal2 ;
    PORT
      LAYER Metal2 ;
        RECT 3792.83 0 3793.09 0.26 ;
    END
  END A_DOUT[129]
  PIN A_DIN[130]
    DIRECTION INPUT ;
    USE SIGNAL ;
    ANTENNAMODEL OXIDE1 ;
      ANTENNAGATEAREA 0.20085 LAYER Metal2 ;
    PORT
      LAYER Metal2 ;
        RECT 3797.63 0 3797.89 0.26 ;
    END
  END A_DIN[130]
  PIN A_DOUT[130]
    DIRECTION OUTPUT ;
    USE SIGNAL ;
    ANTENNADIFFAREA 0.988 LAYER Metal2 ;
    PORT
      LAYER Metal2 ;
        RECT 3802.43 0 3802.69 0.26 ;
    END
  END A_DOUT[130]
  PIN A_DIN[131]
    DIRECTION INPUT ;
    USE SIGNAL ;
    ANTENNAMODEL OXIDE1 ;
      ANTENNAGATEAREA 0.20085 LAYER Metal2 ;
    PORT
      LAYER Metal2 ;
        RECT 3807.23 0 3807.49 0.26 ;
    END
  END A_DIN[131]
  PIN A_DOUT[131]
    DIRECTION OUTPUT ;
    USE SIGNAL ;
    ANTENNADIFFAREA 0.988 LAYER Metal2 ;
    PORT
      LAYER Metal2 ;
        RECT 3812.03 0 3812.29 0.26 ;
    END
  END A_DOUT[131]
  PIN A_DIN[132]
    DIRECTION INPUT ;
    USE SIGNAL ;
    ANTENNAMODEL OXIDE1 ;
      ANTENNAGATEAREA 0.20085 LAYER Metal2 ;
    PORT
      LAYER Metal2 ;
        RECT 3816.83 0 3817.09 0.26 ;
    END
  END A_DIN[132]
  PIN A_DOUT[132]
    DIRECTION OUTPUT ;
    USE SIGNAL ;
    ANTENNADIFFAREA 0.988 LAYER Metal2 ;
    PORT
      LAYER Metal2 ;
        RECT 3821.63 0 3821.89 0.26 ;
    END
  END A_DOUT[132]
  PIN A_DIN[133]
    DIRECTION INPUT ;
    USE SIGNAL ;
    ANTENNAMODEL OXIDE1 ;
      ANTENNAGATEAREA 0.20085 LAYER Metal2 ;
    PORT
      LAYER Metal2 ;
        RECT 3826.43 0 3826.69 0.26 ;
    END
  END A_DIN[133]
  PIN A_DOUT[133]
    DIRECTION OUTPUT ;
    USE SIGNAL ;
    ANTENNADIFFAREA 0.988 LAYER Metal2 ;
    PORT
      LAYER Metal2 ;
        RECT 3831.23 0 3831.49 0.26 ;
    END
  END A_DOUT[133]
  PIN A_DIN[134]
    DIRECTION INPUT ;
    USE SIGNAL ;
    ANTENNAMODEL OXIDE1 ;
      ANTENNAGATEAREA 0.20085 LAYER Metal2 ;
    PORT
      LAYER Metal2 ;
        RECT 3836.03 0 3836.29 0.26 ;
    END
  END A_DIN[134]
  PIN A_DOUT[134]
    DIRECTION OUTPUT ;
    USE SIGNAL ;
    ANTENNADIFFAREA 0.988 LAYER Metal2 ;
    PORT
      LAYER Metal2 ;
        RECT 3840.83 0 3841.09 0.26 ;
    END
  END A_DOUT[134]
  PIN A_DIN[135]
    DIRECTION INPUT ;
    USE SIGNAL ;
    ANTENNAMODEL OXIDE1 ;
      ANTENNAGATEAREA 0.20085 LAYER Metal2 ;
    PORT
      LAYER Metal2 ;
        RECT 3845.63 0 3845.89 0.26 ;
    END
  END A_DIN[135]
  PIN A_DOUT[135]
    DIRECTION OUTPUT ;
    USE SIGNAL ;
    ANTENNADIFFAREA 0.988 LAYER Metal2 ;
    PORT
      LAYER Metal2 ;
        RECT 3850.43 0 3850.69 0.26 ;
    END
  END A_DOUT[135]
  PIN A_DIN[136]
    DIRECTION INPUT ;
    USE SIGNAL ;
    ANTENNAMODEL OXIDE1 ;
      ANTENNAGATEAREA 0.20085 LAYER Metal2 ;
    PORT
      LAYER Metal2 ;
        RECT 3855.23 0 3855.49 0.26 ;
    END
  END A_DIN[136]
  PIN A_DOUT[136]
    DIRECTION OUTPUT ;
    USE SIGNAL ;
    ANTENNADIFFAREA 0.988 LAYER Metal2 ;
    PORT
      LAYER Metal2 ;
        RECT 3860.03 0 3860.29 0.26 ;
    END
  END A_DOUT[136]
  PIN A_DIN[137]
    DIRECTION INPUT ;
    USE SIGNAL ;
    ANTENNAMODEL OXIDE1 ;
      ANTENNAGATEAREA 0.20085 LAYER Metal2 ;
    PORT
      LAYER Metal2 ;
        RECT 3864.83 0 3865.09 0.26 ;
    END
  END A_DIN[137]
  PIN A_DOUT[137]
    DIRECTION OUTPUT ;
    USE SIGNAL ;
    ANTENNADIFFAREA 0.988 LAYER Metal2 ;
    PORT
      LAYER Metal2 ;
        RECT 3869.63 0 3869.89 0.26 ;
    END
  END A_DOUT[137]
  PIN A_DIN[138]
    DIRECTION INPUT ;
    USE SIGNAL ;
    ANTENNAMODEL OXIDE1 ;
      ANTENNAGATEAREA 0.20085 LAYER Metal2 ;
    PORT
      LAYER Metal2 ;
        RECT 3874.43 0 3874.69 0.26 ;
    END
  END A_DIN[138]
  PIN A_DOUT[138]
    DIRECTION OUTPUT ;
    USE SIGNAL ;
    ANTENNADIFFAREA 0.988 LAYER Metal2 ;
    PORT
      LAYER Metal2 ;
        RECT 3879.23 0 3879.49 0.26 ;
    END
  END A_DOUT[138]
  PIN A_DIN[139]
    DIRECTION INPUT ;
    USE SIGNAL ;
    ANTENNAMODEL OXIDE1 ;
      ANTENNAGATEAREA 0.20085 LAYER Metal2 ;
    PORT
      LAYER Metal2 ;
        RECT 3884.03 0 3884.29 0.26 ;
    END
  END A_DIN[139]
  PIN A_DOUT[139]
    DIRECTION OUTPUT ;
    USE SIGNAL ;
    ANTENNADIFFAREA 0.988 LAYER Metal2 ;
    PORT
      LAYER Metal2 ;
        RECT 3888.83 0 3889.09 0.26 ;
    END
  END A_DOUT[139]
  PIN A_DIN[140]
    DIRECTION INPUT ;
    USE SIGNAL ;
    ANTENNAMODEL OXIDE1 ;
      ANTENNAGATEAREA 0.20085 LAYER Metal2 ;
    PORT
      LAYER Metal2 ;
        RECT 3893.63 0 3893.89 0.26 ;
    END
  END A_DIN[140]
  PIN A_DOUT[140]
    DIRECTION OUTPUT ;
    USE SIGNAL ;
    ANTENNADIFFAREA 0.988 LAYER Metal2 ;
    PORT
      LAYER Metal2 ;
        RECT 3898.43 0 3898.69 0.26 ;
    END
  END A_DOUT[140]
  PIN A_DIN[141]
    DIRECTION INPUT ;
    USE SIGNAL ;
    ANTENNAMODEL OXIDE1 ;
      ANTENNAGATEAREA 0.20085 LAYER Metal2 ;
    PORT
      LAYER Metal2 ;
        RECT 3903.23 0 3903.49 0.26 ;
    END
  END A_DIN[141]
  PIN A_DOUT[141]
    DIRECTION OUTPUT ;
    USE SIGNAL ;
    ANTENNADIFFAREA 0.988 LAYER Metal2 ;
    PORT
      LAYER Metal2 ;
        RECT 3908.03 0 3908.29 0.26 ;
    END
  END A_DOUT[141]
  PIN A_DIN[142]
    DIRECTION INPUT ;
    USE SIGNAL ;
    ANTENNAMODEL OXIDE1 ;
      ANTENNAGATEAREA 0.20085 LAYER Metal2 ;
    PORT
      LAYER Metal2 ;
        RECT 3912.83 0 3913.09 0.26 ;
    END
  END A_DIN[142]
  PIN A_DOUT[142]
    DIRECTION OUTPUT ;
    USE SIGNAL ;
    ANTENNADIFFAREA 0.988 LAYER Metal2 ;
    PORT
      LAYER Metal2 ;
        RECT 3917.63 0 3917.89 0.26 ;
    END
  END A_DOUT[142]
  PIN A_DIN[143]
    DIRECTION INPUT ;
    USE SIGNAL ;
    ANTENNAMODEL OXIDE1 ;
      ANTENNAGATEAREA 0.20085 LAYER Metal2 ;
    PORT
      LAYER Metal2 ;
        RECT 3922.43 0 3922.69 0.26 ;
    END
  END A_DIN[143]
  PIN A_DOUT[143]
    DIRECTION OUTPUT ;
    USE SIGNAL ;
    ANTENNADIFFAREA 0.988 LAYER Metal2 ;
    PORT
      LAYER Metal2 ;
        RECT 3927.23 0 3927.49 0.26 ;
    END
  END A_DOUT[143]
  PIN VDD
    DIRECTION INOUT ;
    USE POWER ;
    PORT
      LAYER Metal4 ;
        RECT 15.5 0 18.31 30.425 ;
    END
    PORT
      LAYER Metal4 ;
        RECT 26.74 0 29.55 30.425 ;
    END
    PORT
      LAYER Metal4 ;
        RECT 37.98 0 40.79 30.425 ;
    END
    PORT
      LAYER Metal4 ;
        RECT 49.22 0 52.03 30.425 ;
    END
    PORT
      LAYER Metal4 ;
        RECT 60.46 0 63.27 30.425 ;
    END
    PORT
      LAYER Metal4 ;
        RECT 71.7 0 74.51 30.425 ;
    END
    PORT
      LAYER Metal4 ;
        RECT 82.94 0 85.75 30.425 ;
    END
    PORT
      LAYER Metal4 ;
        RECT 94.18 0 96.99 30.425 ;
    END
    PORT
      LAYER Metal4 ;
        RECT 105.42 0 108.23 30.425 ;
    END
    PORT
      LAYER Metal4 ;
        RECT 116.66 0 119.47 30.425 ;
    END
    PORT
      LAYER Metal4 ;
        RECT 127.9 0 130.71 30.425 ;
    END
    PORT
      LAYER Metal4 ;
        RECT 139.14 0 141.95 30.425 ;
    END
    PORT
      LAYER Metal4 ;
        RECT 150.38 0 153.19 30.425 ;
    END
    PORT
      LAYER Metal4 ;
        RECT 161.62 0 164.43 30.425 ;
    END
    PORT
      LAYER Metal4 ;
        RECT 172.86 0 175.67 30.425 ;
    END
    PORT
      LAYER Metal4 ;
        RECT 184.1 0 186.91 30.425 ;
    END
    PORT
      LAYER Metal4 ;
        RECT 195.34 0 198.15 30.425 ;
    END
    PORT
      LAYER Metal4 ;
        RECT 206.58 0 209.39 30.425 ;
    END
    PORT
      LAYER Metal4 ;
        RECT 217.82 0 220.63 30.425 ;
    END
    PORT
      LAYER Metal4 ;
        RECT 229.06 0 231.87 30.425 ;
    END
    PORT
      LAYER Metal4 ;
        RECT 240.3 0 243.11 30.425 ;
    END
    PORT
      LAYER Metal4 ;
        RECT 251.54 0 254.35 30.425 ;
    END
    PORT
      LAYER Metal4 ;
        RECT 262.78 0 265.59 30.425 ;
    END
    PORT
      LAYER Metal4 ;
        RECT 274.02 0 276.83 30.425 ;
    END
    PORT
      LAYER Metal4 ;
        RECT 285.26 0 288.07 30.425 ;
    END
    PORT
      LAYER Metal4 ;
        RECT 296.5 0 299.31 30.425 ;
    END
    PORT
      LAYER Metal4 ;
        RECT 307.74 0 310.55 30.425 ;
    END
    PORT
      LAYER Metal4 ;
        RECT 318.98 0 321.79 30.425 ;
    END
    PORT
      LAYER Metal4 ;
        RECT 330.22 0 333.03 30.425 ;
    END
    PORT
      LAYER Metal4 ;
        RECT 341.46 0 344.27 30.425 ;
    END
    PORT
      LAYER Metal4 ;
        RECT 352.7 0 355.51 30.425 ;
    END
    PORT
      LAYER Metal4 ;
        RECT 363.94 0 366.75 30.425 ;
    END
    PORT
      LAYER Metal4 ;
        RECT 375.18 0 377.99 30.425 ;
    END
    PORT
      LAYER Metal4 ;
        RECT 386.42 0 389.23 30.425 ;
    END
    PORT
      LAYER Metal4 ;
        RECT 397.66 0 400.47 30.425 ;
    END
    PORT
      LAYER Metal4 ;
        RECT 408.9 0 411.71 30.425 ;
    END
    PORT
      LAYER Metal4 ;
        RECT 420.14 0 422.95 30.425 ;
    END
    PORT
      LAYER Metal4 ;
        RECT 431.38 0 434.19 30.425 ;
    END
    PORT
      LAYER Metal4 ;
        RECT 442.62 0 445.43 30.425 ;
    END
    PORT
      LAYER Metal4 ;
        RECT 453.86 0 456.67 30.425 ;
    END
    PORT
      LAYER Metal4 ;
        RECT 465.1 0 467.91 30.425 ;
    END
    PORT
      LAYER Metal4 ;
        RECT 476.34 0 479.15 30.425 ;
    END
    PORT
      LAYER Metal4 ;
        RECT 487.58 0 490.39 30.425 ;
    END
    PORT
      LAYER Metal4 ;
        RECT 498.82 0 501.63 30.425 ;
    END
    PORT
      LAYER Metal4 ;
        RECT 510.06 0 512.87 30.425 ;
    END
    PORT
      LAYER Metal4 ;
        RECT 521.3 0 524.11 30.425 ;
    END
    PORT
      LAYER Metal4 ;
        RECT 532.54 0 535.35 30.425 ;
    END
    PORT
      LAYER Metal4 ;
        RECT 543.78 0 546.59 30.425 ;
    END
    PORT
      LAYER Metal4 ;
        RECT 555.02 0 557.83 30.425 ;
    END
    PORT
      LAYER Metal4 ;
        RECT 566.26 0 569.07 30.425 ;
    END
    PORT
      LAYER Metal4 ;
        RECT 577.5 0 580.31 30.425 ;
    END
    PORT
      LAYER Metal4 ;
        RECT 588.74 0 591.55 30.425 ;
    END
    PORT
      LAYER Metal4 ;
        RECT 599.98 0 602.79 30.425 ;
    END
    PORT
      LAYER Metal4 ;
        RECT 611.22 0 614.03 30.425 ;
    END
    PORT
      LAYER Metal4 ;
        RECT 622.46 0 625.27 30.425 ;
    END
    PORT
      LAYER Metal4 ;
        RECT 633.7 0 636.51 30.425 ;
    END
    PORT
      LAYER Metal4 ;
        RECT 644.94 0 647.75 30.425 ;
    END
    PORT
      LAYER Metal4 ;
        RECT 656.18 0 658.99 30.425 ;
    END
    PORT
      LAYER Metal4 ;
        RECT 667.42 0 670.23 30.425 ;
    END
    PORT
      LAYER Metal4 ;
        RECT 678.66 0 681.47 30.425 ;
    END
    PORT
      LAYER Metal4 ;
        RECT 689.9 0 692.71 30.425 ;
    END
    PORT
      LAYER Metal4 ;
        RECT 701.14 0 703.95 30.425 ;
    END
    PORT
      LAYER Metal4 ;
        RECT 712.38 0 715.19 30.425 ;
    END
    PORT
      LAYER Metal4 ;
        RECT 723.62 0 726.43 30.425 ;
    END
    PORT
      LAYER Metal4 ;
        RECT 734.86 0 737.67 30.425 ;
    END
    PORT
      LAYER Metal4 ;
        RECT 746.1 0 748.91 30.425 ;
    END
    PORT
      LAYER Metal4 ;
        RECT 757.34 0 760.15 30.425 ;
    END
    PORT
      LAYER Metal4 ;
        RECT 768.58 0 771.39 30.425 ;
    END
    PORT
      LAYER Metal4 ;
        RECT 779.82 0 782.63 30.425 ;
    END
    PORT
      LAYER Metal4 ;
        RECT 791.06 0 793.87 30.425 ;
    END
    PORT
      LAYER Metal4 ;
        RECT 802.3 0 805.11 30.425 ;
    END
    PORT
      LAYER Metal4 ;
        RECT 813.54 0 816.35 30.425 ;
    END
    PORT
      LAYER Metal4 ;
        RECT 824.78 0 827.59 30.425 ;
    END
    PORT
      LAYER Metal4 ;
        RECT 836.02 0 838.83 30.425 ;
    END
    PORT
      LAYER Metal4 ;
        RECT 847.26 0 850.07 30.425 ;
    END
    PORT
      LAYER Metal4 ;
        RECT 858.5 0 861.31 30.425 ;
    END
    PORT
      LAYER Metal4 ;
        RECT 869.74 0 872.55 30.425 ;
    END
    PORT
      LAYER Metal4 ;
        RECT 880.98 0 883.79 30.425 ;
    END
    PORT
      LAYER Metal4 ;
        RECT 892.22 0 895.03 30.425 ;
    END
    PORT
      LAYER Metal4 ;
        RECT 903.46 0 906.27 30.425 ;
    END
    PORT
      LAYER Metal4 ;
        RECT 914.7 0 917.51 30.425 ;
    END
    PORT
      LAYER Metal4 ;
        RECT 925.94 0 928.75 30.425 ;
    END
    PORT
      LAYER Metal4 ;
        RECT 937.18 0 939.99 30.425 ;
    END
    PORT
      LAYER Metal4 ;
        RECT 948.42 0 951.23 30.425 ;
    END
    PORT
      LAYER Metal4 ;
        RECT 959.66 0 962.47 30.425 ;
    END
    PORT
      LAYER Metal4 ;
        RECT 970.9 0 973.71 30.425 ;
    END
    PORT
      LAYER Metal4 ;
        RECT 982.14 0 984.95 30.425 ;
    END
    PORT
      LAYER Metal4 ;
        RECT 993.38 0 996.19 30.425 ;
    END
    PORT
      LAYER Metal4 ;
        RECT 1004.62 0 1007.43 30.425 ;
    END
    PORT
      LAYER Metal4 ;
        RECT 1015.86 0 1018.67 30.425 ;
    END
    PORT
      LAYER Metal4 ;
        RECT 1027.1 0 1029.91 30.425 ;
    END
    PORT
      LAYER Metal4 ;
        RECT 1038.34 0 1041.15 30.425 ;
    END
    PORT
      LAYER Metal4 ;
        RECT 1049.58 0 1052.39 30.425 ;
    END
    PORT
      LAYER Metal4 ;
        RECT 1060.82 0 1063.63 30.425 ;
    END
    PORT
      LAYER Metal4 ;
        RECT 1072.06 0 1074.87 30.425 ;
    END
    PORT
      LAYER Metal4 ;
        RECT 1083.3 0 1086.11 30.425 ;
    END
    PORT
      LAYER Metal4 ;
        RECT 1094.54 0 1097.35 30.425 ;
    END
    PORT
      LAYER Metal4 ;
        RECT 1105.78 0 1108.59 30.425 ;
    END
    PORT
      LAYER Metal4 ;
        RECT 1117.02 0 1119.83 30.425 ;
    END
    PORT
      LAYER Metal4 ;
        RECT 1128.26 0 1131.07 30.425 ;
    END
    PORT
      LAYER Metal4 ;
        RECT 1139.5 0 1142.31 30.425 ;
    END
    PORT
      LAYER Metal4 ;
        RECT 1150.74 0 1153.55 30.425 ;
    END
    PORT
      LAYER Metal4 ;
        RECT 1161.98 0 1164.79 30.425 ;
    END
    PORT
      LAYER Metal4 ;
        RECT 1173.22 0 1176.03 30.425 ;
    END
    PORT
      LAYER Metal4 ;
        RECT 1184.46 0 1187.27 30.425 ;
    END
    PORT
      LAYER Metal4 ;
        RECT 1195.7 0 1198.51 30.425 ;
    END
    PORT
      LAYER Metal4 ;
        RECT 1206.94 0 1209.75 30.425 ;
    END
    PORT
      LAYER Metal4 ;
        RECT 1218.18 0 1220.99 30.425 ;
    END
    PORT
      LAYER Metal4 ;
        RECT 1229.42 0 1232.23 30.425 ;
    END
    PORT
      LAYER Metal4 ;
        RECT 1240.66 0 1243.47 30.425 ;
    END
    PORT
      LAYER Metal4 ;
        RECT 1251.9 0 1254.71 30.425 ;
    END
    PORT
      LAYER Metal4 ;
        RECT 1263.14 0 1265.95 30.425 ;
    END
    PORT
      LAYER Metal4 ;
        RECT 1274.38 0 1277.19 30.425 ;
    END
    PORT
      LAYER Metal4 ;
        RECT 1285.62 0 1288.43 30.425 ;
    END
    PORT
      LAYER Metal4 ;
        RECT 1296.86 0 1299.67 30.425 ;
    END
    PORT
      LAYER Metal4 ;
        RECT 1308.1 0 1310.91 30.425 ;
    END
    PORT
      LAYER Metal4 ;
        RECT 1319.34 0 1322.15 30.425 ;
    END
    PORT
      LAYER Metal4 ;
        RECT 1330.58 0 1333.39 30.425 ;
    END
    PORT
      LAYER Metal4 ;
        RECT 1341.82 0 1344.63 30.425 ;
    END
    PORT
      LAYER Metal4 ;
        RECT 1353.06 0 1355.87 30.425 ;
    END
    PORT
      LAYER Metal4 ;
        RECT 1364.3 0 1367.11 30.425 ;
    END
    PORT
      LAYER Metal4 ;
        RECT 1375.54 0 1378.35 30.425 ;
    END
    PORT
      LAYER Metal4 ;
        RECT 1386.78 0 1389.59 30.425 ;
    END
    PORT
      LAYER Metal4 ;
        RECT 1398.02 0 1400.83 30.425 ;
    END
    PORT
      LAYER Metal4 ;
        RECT 1409.26 0 1412.07 30.425 ;
    END
    PORT
      LAYER Metal4 ;
        RECT 1420.5 0 1423.31 30.425 ;
    END
    PORT
      LAYER Metal4 ;
        RECT 1431.74 0 1434.55 30.425 ;
    END
    PORT
      LAYER Metal4 ;
        RECT 1442.98 0 1445.79 30.425 ;
    END
    PORT
      LAYER Metal4 ;
        RECT 1454.22 0 1457.03 30.425 ;
    END
    PORT
      LAYER Metal4 ;
        RECT 1465.46 0 1468.27 30.425 ;
    END
    PORT
      LAYER Metal4 ;
        RECT 1476.7 0 1479.51 30.425 ;
    END
    PORT
      LAYER Metal4 ;
        RECT 1487.94 0 1490.75 30.425 ;
    END
    PORT
      LAYER Metal4 ;
        RECT 1499.18 0 1501.99 30.425 ;
    END
    PORT
      LAYER Metal4 ;
        RECT 1510.42 0 1513.23 30.425 ;
    END
    PORT
      LAYER Metal4 ;
        RECT 1521.66 0 1524.47 30.425 ;
    END
    PORT
      LAYER Metal4 ;
        RECT 1532.9 0 1535.71 30.425 ;
    END
    PORT
      LAYER Metal4 ;
        RECT 1544.14 0 1546.95 30.425 ;
    END
    PORT
      LAYER Metal4 ;
        RECT 1555.38 0 1558.19 30.425 ;
    END
    PORT
      LAYER Metal4 ;
        RECT 1566.62 0 1569.43 30.425 ;
    END
    PORT
      LAYER Metal4 ;
        RECT 1577.86 0 1580.67 30.425 ;
    END
    PORT
      LAYER Metal4 ;
        RECT 1589.1 0 1591.91 30.425 ;
    END
    PORT
      LAYER Metal4 ;
        RECT 1600.34 0 1603.15 30.425 ;
    END
    PORT
      LAYER Metal4 ;
        RECT 1611.58 0 1614.39 30.425 ;
    END
    PORT
      LAYER Metal4 ;
        RECT 1622.82 0 1625.63 30.425 ;
    END
    PORT
      LAYER Metal4 ;
        RECT 1634.06 0 1636.87 30.425 ;
    END
    PORT
      LAYER Metal4 ;
        RECT 1645.3 0 1648.11 30.425 ;
    END
    PORT
      LAYER Metal4 ;
        RECT 1656.54 0 1659.35 30.425 ;
    END
    PORT
      LAYER Metal4 ;
        RECT 1667.78 0 1670.59 30.425 ;
    END
    PORT
      LAYER Metal4 ;
        RECT 1679.02 0 1681.83 30.425 ;
    END
    PORT
      LAYER Metal4 ;
        RECT 1690.26 0 1693.07 30.425 ;
    END
    PORT
      LAYER Metal4 ;
        RECT 1701.5 0 1704.31 30.425 ;
    END
    PORT
      LAYER Metal4 ;
        RECT 1712.74 0 1715.55 30.425 ;
    END
    PORT
      LAYER Metal4 ;
        RECT 1723.98 0 1726.79 30.425 ;
    END
    PORT
      LAYER Metal4 ;
        RECT 1735.22 0 1738.03 30.425 ;
    END
    PORT
      LAYER Metal4 ;
        RECT 1746.46 0 1749.27 30.425 ;
    END
    PORT
      LAYER Metal4 ;
        RECT 1757.7 0 1760.51 30.425 ;
    END
    PORT
      LAYER Metal4 ;
        RECT 1768.94 0 1771.75 30.425 ;
    END
    PORT
      LAYER Metal4 ;
        RECT 1780.18 0 1782.99 30.425 ;
    END
    PORT
      LAYER Metal4 ;
        RECT 1791.42 0 1794.23 30.425 ;
    END
    PORT
      LAYER Metal4 ;
        RECT 1802.66 0 1805.47 30.425 ;
    END
    PORT
      LAYER Metal4 ;
        RECT 1813.9 0 1816.71 30.425 ;
    END
    PORT
      LAYER Metal4 ;
        RECT 1825.14 0 1827.95 30.425 ;
    END
    PORT
      LAYER Metal4 ;
        RECT 1836.38 0 1839.19 30.425 ;
    END
    PORT
      LAYER Metal4 ;
        RECT 1847.62 0 1850.43 30.425 ;
    END
    PORT
      LAYER Metal4 ;
        RECT 1858.86 0 1861.67 30.425 ;
    END
    PORT
      LAYER Metal4 ;
        RECT 1870.1 0 1872.91 30.425 ;
    END
    PORT
      LAYER Metal4 ;
        RECT 1881.34 0 1884.15 30.425 ;
    END
    PORT
      LAYER Metal4 ;
        RECT 1892.58 0 1895.39 30.425 ;
    END
    PORT
      LAYER Metal4 ;
        RECT 1903.82 0 1906.63 30.425 ;
    END
    PORT
      LAYER Metal4 ;
        RECT 1915.06 0 1917.87 30.425 ;
    END
    PORT
      LAYER Metal4 ;
        RECT 1926.3 0 1929.11 30.425 ;
    END
    PORT
      LAYER Metal4 ;
        RECT 1937.54 0 1940.35 30.425 ;
    END
    PORT
      LAYER Metal4 ;
        RECT 1948.78 0 1951.59 30.425 ;
    END
    PORT
      LAYER Metal4 ;
        RECT 1960.02 0 1962.83 30.425 ;
    END
    PORT
      LAYER Metal4 ;
        RECT 1971.26 0 1974.07 30.425 ;
    END
    PORT
      LAYER Metal4 ;
        RECT 1982.5 0 1985.31 30.425 ;
    END
    PORT
      LAYER Metal4 ;
        RECT 1993.74 0 1996.55 30.425 ;
    END
    PORT
      LAYER Metal4 ;
        RECT 2004.98 0 2007.79 30.425 ;
    END
    PORT
      LAYER Metal4 ;
        RECT 2016.22 0 2019.03 30.425 ;
    END
    PORT
      LAYER Metal4 ;
        RECT 2027.46 0 2030.27 30.425 ;
    END
    PORT
      LAYER Metal4 ;
        RECT 2038.7 0 2041.51 30.425 ;
    END
    PORT
      LAYER Metal4 ;
        RECT 2049.94 0 2052.75 30.425 ;
    END
    PORT
      LAYER Metal4 ;
        RECT 2061.18 0 2063.99 30.425 ;
    END
    PORT
      LAYER Metal4 ;
        RECT 2072.42 0 2075.23 30.425 ;
    END
    PORT
      LAYER Metal4 ;
        RECT 2083.66 0 2086.47 30.425 ;
    END
    PORT
      LAYER Metal4 ;
        RECT 2094.9 0 2097.71 30.425 ;
    END
    PORT
      LAYER Metal4 ;
        RECT 2106.14 0 2108.95 30.425 ;
    END
    PORT
      LAYER Metal4 ;
        RECT 2117.38 0 2120.19 30.425 ;
    END
    PORT
      LAYER Metal4 ;
        RECT 2128.62 0 2131.43 30.425 ;
    END
    PORT
      LAYER Metal4 ;
        RECT 2139.86 0 2142.67 30.425 ;
    END
    PORT
      LAYER Metal4 ;
        RECT 2151.1 0 2153.91 30.425 ;
    END
    PORT
      LAYER Metal4 ;
        RECT 2162.34 0 2165.15 30.425 ;
    END
    PORT
      LAYER Metal4 ;
        RECT 2173.58 0 2176.39 30.425 ;
    END
    PORT
      LAYER Metal4 ;
        RECT 2184.82 0 2187.63 30.425 ;
    END
    PORT
      LAYER Metal4 ;
        RECT 2196.06 0 2198.87 30.425 ;
    END
    PORT
      LAYER Metal4 ;
        RECT 2207.3 0 2210.11 30.425 ;
    END
    PORT
      LAYER Metal4 ;
        RECT 2218.54 0 2221.35 30.425 ;
    END
    PORT
      LAYER Metal4 ;
        RECT 2229.78 0 2232.59 30.425 ;
    END
    PORT
      LAYER Metal4 ;
        RECT 2241.02 0 2243.83 30.425 ;
    END
    PORT
      LAYER Metal4 ;
        RECT 2252.26 0 2255.07 30.425 ;
    END
    PORT
      LAYER Metal4 ;
        RECT 2263.5 0 2266.31 30.425 ;
    END
    PORT
      LAYER Metal4 ;
        RECT 2274.74 0 2277.55 30.425 ;
    END
    PORT
      LAYER Metal4 ;
        RECT 2285.98 0 2288.79 30.425 ;
    END
    PORT
      LAYER Metal4 ;
        RECT 2297.22 0 2300.03 30.425 ;
    END
    PORT
      LAYER Metal4 ;
        RECT 2308.46 0 2311.27 30.425 ;
    END
    PORT
      LAYER Metal4 ;
        RECT 2319.7 0 2322.51 30.425 ;
    END
    PORT
      LAYER Metal4 ;
        RECT 2330.94 0 2333.75 30.425 ;
    END
    PORT
      LAYER Metal4 ;
        RECT 2342.18 0 2344.99 30.425 ;
    END
    PORT
      LAYER Metal4 ;
        RECT 2353.42 0 2356.23 30.425 ;
    END
    PORT
      LAYER Metal4 ;
        RECT 2364.66 0 2367.47 30.425 ;
    END
    PORT
      LAYER Metal4 ;
        RECT 2375.9 0 2378.71 30.425 ;
    END
    PORT
      LAYER Metal4 ;
        RECT 2387.14 0 2389.95 30.425 ;
    END
    PORT
      LAYER Metal4 ;
        RECT 2398.38 0 2401.19 30.425 ;
    END
    PORT
      LAYER Metal4 ;
        RECT 2409.62 0 2412.43 30.425 ;
    END
    PORT
      LAYER Metal4 ;
        RECT 2420.86 0 2423.67 30.425 ;
    END
    PORT
      LAYER Metal4 ;
        RECT 2432.1 0 2434.91 30.425 ;
    END
    PORT
      LAYER Metal4 ;
        RECT 2443.34 0 2446.15 30.425 ;
    END
    PORT
      LAYER Metal4 ;
        RECT 2454.58 0 2457.39 30.425 ;
    END
    PORT
      LAYER Metal4 ;
        RECT 2465.82 0 2468.63 30.425 ;
    END
    PORT
      LAYER Metal4 ;
        RECT 2477.06 0 2479.87 30.425 ;
    END
    PORT
      LAYER Metal4 ;
        RECT 2488.3 0 2491.11 30.425 ;
    END
    PORT
      LAYER Metal4 ;
        RECT 2499.54 0 2502.35 30.425 ;
    END
    PORT
      LAYER Metal4 ;
        RECT 2510.78 0 2513.59 30.425 ;
    END
    PORT
      LAYER Metal4 ;
        RECT 2522.02 0 2524.83 30.425 ;
    END
    PORT
      LAYER Metal4 ;
        RECT 2533.26 0 2536.07 30.425 ;
    END
    PORT
      LAYER Metal4 ;
        RECT 2544.5 0 2547.31 30.425 ;
    END
    PORT
      LAYER Metal4 ;
        RECT 2555.74 0 2558.55 30.425 ;
    END
    PORT
      LAYER Metal4 ;
        RECT 2566.98 0 2569.79 30.425 ;
    END
    PORT
      LAYER Metal4 ;
        RECT 2578.22 0 2581.03 30.425 ;
    END
    PORT
      LAYER Metal4 ;
        RECT 2589.46 0 2592.27 30.425 ;
    END
    PORT
      LAYER Metal4 ;
        RECT 2600.7 0 2603.51 30.425 ;
    END
    PORT
      LAYER Metal4 ;
        RECT 2611.94 0 2614.75 30.425 ;
    END
    PORT
      LAYER Metal4 ;
        RECT 2623.18 0 2625.99 30.425 ;
    END
    PORT
      LAYER Metal4 ;
        RECT 2634.42 0 2637.23 30.425 ;
    END
    PORT
      LAYER Metal4 ;
        RECT 2645.66 0 2648.47 30.425 ;
    END
    PORT
      LAYER Metal4 ;
        RECT 2656.9 0 2659.71 30.425 ;
    END
    PORT
      LAYER Metal4 ;
        RECT 2668.14 0 2670.95 30.425 ;
    END
    PORT
      LAYER Metal4 ;
        RECT 2679.38 0 2682.19 30.425 ;
    END
    PORT
      LAYER Metal4 ;
        RECT 2690.62 0 2693.43 30.425 ;
    END
    PORT
      LAYER Metal4 ;
        RECT 2701.86 0 2704.67 30.425 ;
    END
    PORT
      LAYER Metal4 ;
        RECT 2713.1 0 2715.91 30.425 ;
    END
    PORT
      LAYER Metal4 ;
        RECT 2724.34 0 2727.15 30.425 ;
    END
    PORT
      LAYER Metal4 ;
        RECT 2735.58 0 2738.39 30.425 ;
    END
    PORT
      LAYER Metal4 ;
        RECT 2746.82 0 2749.63 30.425 ;
    END
    PORT
      LAYER Metal4 ;
        RECT 2758.06 0 2760.87 30.425 ;
    END
    PORT
      LAYER Metal4 ;
        RECT 2769.3 0 2772.11 30.425 ;
    END
    PORT
      LAYER Metal4 ;
        RECT 2780.54 0 2783.35 30.425 ;
    END
    PORT
      LAYER Metal4 ;
        RECT 2791.78 0 2794.59 30.425 ;
    END
    PORT
      LAYER Metal4 ;
        RECT 2803.02 0 2805.83 30.425 ;
    END
    PORT
      LAYER Metal4 ;
        RECT 2814.26 0 2817.07 30.425 ;
    END
    PORT
      LAYER Metal4 ;
        RECT 2825.5 0 2828.31 30.425 ;
    END
    PORT
      LAYER Metal4 ;
        RECT 2836.74 0 2839.55 30.425 ;
    END
    PORT
      LAYER Metal4 ;
        RECT 2847.98 0 2850.79 30.425 ;
    END
    PORT
      LAYER Metal4 ;
        RECT 2859.22 0 2862.03 30.425 ;
    END
    PORT
      LAYER Metal4 ;
        RECT 2870.46 0 2873.27 30.425 ;
    END
    PORT
      LAYER Metal4 ;
        RECT 2881.7 0 2884.51 30.425 ;
    END
    PORT
      LAYER Metal4 ;
        RECT 2892.94 0 2895.75 30.425 ;
    END
    PORT
      LAYER Metal4 ;
        RECT 2904.18 0 2906.99 30.425 ;
    END
    PORT
      LAYER Metal4 ;
        RECT 2915.42 0 2918.23 30.425 ;
    END
    PORT
      LAYER Metal4 ;
        RECT 2926.66 0 2929.47 30.425 ;
    END
    PORT
      LAYER Metal4 ;
        RECT 2937.9 0 2940.71 30.425 ;
    END
    PORT
      LAYER Metal4 ;
        RECT 2949.14 0 2951.95 30.425 ;
    END
    PORT
      LAYER Metal4 ;
        RECT 2960.38 0 2963.19 30.425 ;
    END
    PORT
      LAYER Metal4 ;
        RECT 2971.62 0 2974.43 30.425 ;
    END
    PORT
      LAYER Metal4 ;
        RECT 2982.86 0 2985.67 30.425 ;
    END
    PORT
      LAYER Metal4 ;
        RECT 2994.1 0 2996.91 30.425 ;
    END
    PORT
      LAYER Metal4 ;
        RECT 3005.34 0 3008.15 30.425 ;
    END
    PORT
      LAYER Metal4 ;
        RECT 3016.58 0 3019.39 30.425 ;
    END
    PORT
      LAYER Metal4 ;
        RECT 3027.82 0 3030.63 30.425 ;
    END
    PORT
      LAYER Metal4 ;
        RECT 3039.06 0 3041.87 30.425 ;
    END
    PORT
      LAYER Metal4 ;
        RECT 3050.3 0 3053.11 30.425 ;
    END
    PORT
      LAYER Metal4 ;
        RECT 3061.54 0 3064.35 30.425 ;
    END
    PORT
      LAYER Metal4 ;
        RECT 3072.78 0 3075.59 30.425 ;
    END
    PORT
      LAYER Metal4 ;
        RECT 3084.02 0 3086.83 30.425 ;
    END
    PORT
      LAYER Metal4 ;
        RECT 3095.26 0 3098.07 30.425 ;
    END
    PORT
      LAYER Metal4 ;
        RECT 3106.5 0 3109.31 30.425 ;
    END
    PORT
      LAYER Metal4 ;
        RECT 3117.74 0 3120.55 30.425 ;
    END
    PORT
      LAYER Metal4 ;
        RECT 3128.98 0 3131.79 30.425 ;
    END
    PORT
      LAYER Metal4 ;
        RECT 3140.22 0 3143.03 30.425 ;
    END
    PORT
      LAYER Metal4 ;
        RECT 3151.46 0 3154.27 30.425 ;
    END
    PORT
      LAYER Metal4 ;
        RECT 3162.7 0 3165.51 30.425 ;
    END
    PORT
      LAYER Metal4 ;
        RECT 3173.94 0 3176.75 30.425 ;
    END
    PORT
      LAYER Metal4 ;
        RECT 3185.18 0 3187.99 30.425 ;
    END
    PORT
      LAYER Metal4 ;
        RECT 3196.42 0 3199.23 30.425 ;
    END
    PORT
      LAYER Metal4 ;
        RECT 3207.66 0 3210.47 30.425 ;
    END
    PORT
      LAYER Metal4 ;
        RECT 3218.9 0 3221.71 30.425 ;
    END
    PORT
      LAYER Metal4 ;
        RECT 3230.14 0 3232.95 30.425 ;
    END
    PORT
      LAYER Metal4 ;
        RECT 3241.38 0 3244.19 30.425 ;
    END
    PORT
      LAYER Metal4 ;
        RECT 3252.62 0 3255.43 30.425 ;
    END
    PORT
      LAYER Metal4 ;
        RECT 3263.86 0 3266.67 30.425 ;
    END
    PORT
      LAYER Metal4 ;
        RECT 3275.1 0 3277.91 30.425 ;
    END
    PORT
      LAYER Metal4 ;
        RECT 3286.34 0 3289.15 30.425 ;
    END
    PORT
      LAYER Metal4 ;
        RECT 3297.58 0 3300.39 30.425 ;
    END
    PORT
      LAYER Metal4 ;
        RECT 3308.82 0 3311.63 30.425 ;
    END
    PORT
      LAYER Metal4 ;
        RECT 3320.06 0 3322.87 30.425 ;
    END
    PORT
      LAYER Metal4 ;
        RECT 3331.3 0 3334.11 30.425 ;
    END
    PORT
      LAYER Metal4 ;
        RECT 3342.54 0 3345.35 30.425 ;
    END
    PORT
      LAYER Metal4 ;
        RECT 3353.78 0 3356.59 30.425 ;
    END
    PORT
      LAYER Metal4 ;
        RECT 3365.02 0 3367.83 30.425 ;
    END
    PORT
      LAYER Metal4 ;
        RECT 3376.26 0 3379.07 30.425 ;
    END
    PORT
      LAYER Metal4 ;
        RECT 3387.5 0 3390.31 30.425 ;
    END
    PORT
      LAYER Metal4 ;
        RECT 3398.74 0 3401.55 30.425 ;
    END
    PORT
      LAYER Metal4 ;
        RECT 3409.98 0 3412.79 30.425 ;
    END
    PORT
      LAYER Metal4 ;
        RECT 3421.22 0 3424.03 30.425 ;
    END
    PORT
      LAYER Metal4 ;
        RECT 3432.46 0 3435.27 30.425 ;
    END
    PORT
      LAYER Metal4 ;
        RECT 3443.7 0 3446.51 30.425 ;
    END
    PORT
      LAYER Metal4 ;
        RECT 3454.94 0 3457.75 30.425 ;
    END
    PORT
      LAYER Metal4 ;
        RECT 3466.18 0 3468.99 30.425 ;
    END
    PORT
      LAYER Metal4 ;
        RECT 3477.42 0 3480.23 30.425 ;
    END
    PORT
      LAYER Metal4 ;
        RECT 3488.66 0 3491.47 30.425 ;
    END
    PORT
      LAYER Metal4 ;
        RECT 3499.9 0 3502.71 30.425 ;
    END
    PORT
      LAYER Metal4 ;
        RECT 3511.14 0 3513.95 30.425 ;
    END
    PORT
      LAYER Metal4 ;
        RECT 3522.38 0 3525.19 30.425 ;
    END
    PORT
      LAYER Metal4 ;
        RECT 3533.62 0 3536.43 30.425 ;
    END
    PORT
      LAYER Metal4 ;
        RECT 3544.86 0 3547.67 30.425 ;
    END
    PORT
      LAYER Metal4 ;
        RECT 3556.1 0 3558.91 30.425 ;
    END
    PORT
      LAYER Metal4 ;
        RECT 3567.34 0 3570.15 30.425 ;
    END
    PORT
      LAYER Metal4 ;
        RECT 3578.58 0 3581.39 30.425 ;
    END
    PORT
      LAYER Metal4 ;
        RECT 3589.82 0 3592.63 30.425 ;
    END
    PORT
      LAYER Metal4 ;
        RECT 3601.06 0 3603.87 30.425 ;
    END
    PORT
      LAYER Metal4 ;
        RECT 3612.3 0 3615.11 30.425 ;
    END
    PORT
      LAYER Metal4 ;
        RECT 3623.54 0 3626.35 30.425 ;
    END
    PORT
      LAYER Metal4 ;
        RECT 3634.78 0 3637.59 30.425 ;
    END
    PORT
      LAYER Metal4 ;
        RECT 3646.02 0 3648.83 30.425 ;
    END
    PORT
      LAYER Metal4 ;
        RECT 3657.26 0 3660.07 30.425 ;
    END
    PORT
      LAYER Metal4 ;
        RECT 3668.5 0 3671.31 30.425 ;
    END
    PORT
      LAYER Metal4 ;
        RECT 3679.74 0 3682.55 30.425 ;
    END
    PORT
      LAYER Metal4 ;
        RECT 3690.98 0 3693.79 30.425 ;
    END
    PORT
      LAYER Metal4 ;
        RECT 3702.22 0 3705.03 30.425 ;
    END
    PORT
      LAYER Metal4 ;
        RECT 3713.46 0 3716.27 30.425 ;
    END
    PORT
      LAYER Metal4 ;
        RECT 3724.7 0 3727.51 30.425 ;
    END
    PORT
      LAYER Metal4 ;
        RECT 3735.94 0 3738.75 30.425 ;
    END
    PORT
      LAYER Metal4 ;
        RECT 3747.18 0 3749.99 30.425 ;
    END
    PORT
      LAYER Metal4 ;
        RECT 3758.42 0 3761.23 30.425 ;
    END
    PORT
      LAYER Metal4 ;
        RECT 3769.66 0 3772.47 30.425 ;
    END
    PORT
      LAYER Metal4 ;
        RECT 3780.9 0 3783.71 30.425 ;
    END
    PORT
      LAYER Metal4 ;
        RECT 3792.14 0 3794.95 30.425 ;
    END
    PORT
      LAYER Metal4 ;
        RECT 3803.38 0 3806.19 30.425 ;
    END
    PORT
      LAYER Metal4 ;
        RECT 3814.62 0 3817.43 30.425 ;
    END
    PORT
      LAYER Metal4 ;
        RECT 3825.86 0 3828.67 30.425 ;
    END
    PORT
      LAYER Metal4 ;
        RECT 3837.1 0 3839.91 30.425 ;
    END
    PORT
      LAYER Metal4 ;
        RECT 3848.34 0 3851.15 30.425 ;
    END
    PORT
      LAYER Metal4 ;
        RECT 3859.58 0 3862.39 30.425 ;
    END
    PORT
      LAYER Metal4 ;
        RECT 3870.82 0 3873.63 30.425 ;
    END
    PORT
      LAYER Metal4 ;
        RECT 3882.06 0 3884.87 30.425 ;
    END
    PORT
      LAYER Metal4 ;
        RECT 3893.3 0 3896.11 30.425 ;
    END
    PORT
      LAYER Metal4 ;
        RECT 3904.54 0 3907.35 30.425 ;
    END
    PORT
      LAYER Metal4 ;
        RECT 3915.78 0 3918.59 30.425 ;
    END
    PORT
      LAYER Metal4 ;
        RECT 3927.02 0 3929.83 30.425 ;
    END
    PORT
      LAYER Metal4 ;
        RECT 3938.26 0 3941.07 30.425 ;
    END
    PORT
      LAYER Metal4 ;
        RECT 3949.5 0 3952.31 30.425 ;
    END
    PORT
      LAYER Metal4 ;
        RECT 3960.74 0 3963.55 30.425 ;
    END
    PORT
      LAYER Metal4 ;
        RECT 3971.98 0 3974.79 30.425 ;
    END
    PORT
      LAYER Metal4 ;
        RECT 3983.22 0 3986.03 30.425 ;
    END
    PORT
      LAYER Metal4 ;
        RECT 3994.46 0 3997.27 30.425 ;
    END
    PORT
      LAYER Metal4 ;
        RECT 4005.7 0 4008.51 30.425 ;
    END
    PORT
      LAYER Metal4 ;
        RECT 4016.94 0 4019.75 30.425 ;
    END
    PORT
      LAYER Metal4 ;
        RECT 4028.18 0 4030.99 30.425 ;
    END
    PORT
      LAYER Metal4 ;
        RECT 4039.42 0 4042.23 30.425 ;
    END
    PORT
      LAYER Metal4 ;
        RECT 4050.66 0 4053.47 30.425 ;
    END
    PORT
      LAYER Metal4 ;
        RECT 4061.9 0 4064.71 30.425 ;
    END
    PORT
      LAYER Metal4 ;
        RECT 4073.14 0 4075.95 30.425 ;
    END
    PORT
      LAYER Metal4 ;
        RECT 4084.38 0 4087.19 30.425 ;
    END
    PORT
      LAYER Metal4 ;
        RECT 4095.62 0 4098.43 30.425 ;
    END
    PORT
      LAYER Metal4 ;
        RECT 4106.86 0 4109.67 30.425 ;
    END
    PORT
      LAYER Metal4 ;
        RECT 4118.1 0 4120.91 30.425 ;
    END
    PORT
      LAYER Metal4 ;
        RECT 4129.34 0 4132.15 30.425 ;
    END
    PORT
      LAYER Metal4 ;
        RECT 4140.58 0 4143.39 30.425 ;
    END
    PORT
      LAYER Metal4 ;
        RECT 4151.82 0 4154.63 30.425 ;
    END
    PORT
      LAYER Metal4 ;
        RECT 4163.06 0 4165.87 30.425 ;
    END
    PORT
      LAYER Metal4 ;
        RECT 4174.3 0 4177.11 30.425 ;
    END
    PORT
      LAYER Metal4 ;
        RECT 4185.54 0 4188.35 30.425 ;
    END
    PORT
      LAYER Metal4 ;
        RECT 4196.78 0 4199.59 30.425 ;
    END
    PORT
      LAYER Metal4 ;
        RECT 4208.02 0 4210.83 30.425 ;
    END
    PORT
      LAYER Metal4 ;
        RECT 4219.26 0 4222.07 30.425 ;
    END
    PORT
      LAYER Metal4 ;
        RECT 4230.5 0 4233.31 30.425 ;
    END
    PORT
      LAYER Metal4 ;
        RECT 4241.74 0 4244.55 30.425 ;
    END
    PORT
      LAYER Metal4 ;
        RECT 4252.98 0 4255.79 30.425 ;
    END
    PORT
      LAYER Metal4 ;
        RECT 4264.22 0 4267.03 30.425 ;
    END
    PORT
      LAYER Metal4 ;
        RECT 4275.46 0 4278.27 30.425 ;
    END
    PORT
      LAYER Metal4 ;
        RECT 4286.7 0 4289.51 30.425 ;
    END
    PORT
      LAYER Metal4 ;
        RECT 4297.94 0 4300.75 30.425 ;
    END
    PORT
      LAYER Metal4 ;
        RECT 4309.18 0 4311.99 30.425 ;
    END
    PORT
      LAYER Metal4 ;
        RECT 4320.42 0 4323.23 30.425 ;
    END
    PORT
      LAYER Metal4 ;
        RECT 4331.66 0 4334.47 30.425 ;
    END
    PORT
      LAYER Metal4 ;
        RECT 4342.9 0 4345.71 30.425 ;
    END
    PORT
      LAYER Metal4 ;
        RECT 4354.14 0 4356.95 30.425 ;
    END
    PORT
      LAYER Metal4 ;
        RECT 4365.38 0 4368.19 30.425 ;
    END
    PORT
      LAYER Metal4 ;
        RECT 4376.62 0 4379.43 30.425 ;
    END
    PORT
      LAYER Metal4 ;
        RECT 4387.86 0 4390.67 30.425 ;
    END
    PORT
      LAYER Metal4 ;
        RECT 4399.1 0 4401.91 30.425 ;
    END
    PORT
      LAYER Metal4 ;
        RECT 4410.34 0 4413.15 30.425 ;
    END
    PORT
      LAYER Metal4 ;
        RECT 4421.58 0 4424.39 30.425 ;
    END
    PORT
      LAYER Metal4 ;
        RECT 4432.82 0 4435.63 30.425 ;
    END
    PORT
      LAYER Metal4 ;
        RECT 4444.06 0 4446.87 30.425 ;
    END
    PORT
      LAYER Metal4 ;
        RECT 4455.3 0 4458.11 30.425 ;
    END
    PORT
      LAYER Metal4 ;
        RECT 4466.54 0 4469.35 30.425 ;
    END
    PORT
      LAYER Metal4 ;
        RECT 4477.78 0 4480.59 30.425 ;
    END
    PORT
      LAYER Metal4 ;
        RECT 4489.02 0 4491.83 30.425 ;
    END
    PORT
      LAYER Metal4 ;
        RECT 4500.26 0 4503.07 30.425 ;
    END
    PORT
      LAYER Metal4 ;
        RECT 4511.5 0 4514.31 30.425 ;
    END
    PORT
      LAYER Metal4 ;
        RECT 4522.74 0 4525.55 30.425 ;
    END
    PORT
      LAYER Metal4 ;
        RECT 4533.98 0 4536.79 30.425 ;
    END
    PORT
      LAYER Metal4 ;
        RECT 4545.22 0 4548.03 30.425 ;
    END
    PORT
      LAYER Metal4 ;
        RECT 4556.46 0 4559.27 30.425 ;
    END
    PORT
      LAYER Metal4 ;
        RECT 4567.7 0 4570.51 30.425 ;
    END
    PORT
      LAYER Metal4 ;
        RECT 4578.94 0 4581.75 30.425 ;
    END
    PORT
      LAYER Metal4 ;
        RECT 4590.18 0 4592.99 30.425 ;
    END
    PORT
      LAYER Metal4 ;
        RECT 4601.42 0 4604.23 30.425 ;
    END
    PORT
      LAYER Metal4 ;
        RECT 4612.66 0 4615.47 30.425 ;
    END
    PORT
      LAYER Metal4 ;
        RECT 4623.9 0 4626.71 30.425 ;
    END
    PORT
      LAYER Metal4 ;
        RECT 4635.14 0 4637.95 30.425 ;
    END
    PORT
      LAYER Metal4 ;
        RECT 4646.38 0 4649.19 30.425 ;
    END
    PORT
      LAYER Metal4 ;
        RECT 4657.62 0 4660.43 30.425 ;
    END
    PORT
      LAYER Metal4 ;
        RECT 4668.86 0 4671.67 30.425 ;
    END
    PORT
      LAYER Metal4 ;
        RECT 4680.1 0 4682.91 30.425 ;
    END
    PORT
      LAYER Metal4 ;
        RECT 4691.34 0 4694.15 30.425 ;
    END
    PORT
      LAYER Metal4 ;
        RECT 4702.58 0 4705.39 30.425 ;
    END
    PORT
      LAYER Metal4 ;
        RECT 4713.82 0 4716.63 30.425 ;
    END
    PORT
      LAYER Metal4 ;
        RECT 4725.06 0 4727.87 30.425 ;
    END
    PORT
      LAYER Metal4 ;
        RECT 4736.3 0 4739.11 30.425 ;
    END
    PORT
      LAYER Metal4 ;
        RECT 4747.54 0 4750.35 30.425 ;
    END
    PORT
      LAYER Metal4 ;
        RECT 4758.78 0 4761.59 30.425 ;
    END
    PORT
      LAYER Metal4 ;
        RECT 4770.02 0 4772.83 30.425 ;
    END
    PORT
      LAYER Metal4 ;
        RECT 4781.26 0 4784.07 30.425 ;
    END
    PORT
      LAYER Metal4 ;
        RECT 4792.5 0 4795.31 30.425 ;
    END
    PORT
      LAYER Metal4 ;
        RECT 4803.74 0 4806.55 30.425 ;
    END
    PORT
      LAYER Metal4 ;
        RECT 4814.98 0 4817.79 30.425 ;
    END
    PORT
      LAYER Metal4 ;
        RECT 4826.22 0 4829.03 30.425 ;
    END
    PORT
      LAYER Metal4 ;
        RECT 4837.46 0 4840.27 30.425 ;
    END
    PORT
      LAYER Metal4 ;
        RECT 4848.7 0 4851.51 30.425 ;
    END
    PORT
      LAYER Metal4 ;
        RECT 4859.94 0 4862.75 30.425 ;
    END
    PORT
      LAYER Metal4 ;
        RECT 4871.18 0 4873.99 30.425 ;
    END
    PORT
      LAYER Metal4 ;
        RECT 4882.42 0 4885.23 30.425 ;
    END
    PORT
      LAYER Metal4 ;
        RECT 4893.66 0 4896.47 30.425 ;
    END
    PORT
      LAYER Metal4 ;
        RECT 4904.9 0 4907.71 30.425 ;
    END
    PORT
      LAYER Metal4 ;
        RECT 4916.14 0 4918.95 30.425 ;
    END
    PORT
      LAYER Metal4 ;
        RECT 4927.38 0 4930.19 30.425 ;
    END
    PORT
      LAYER Metal4 ;
        RECT 4938.62 0 4941.43 30.425 ;
    END
    PORT
      LAYER Metal4 ;
        RECT 4949.86 0 4952.67 30.425 ;
    END
    PORT
      LAYER Metal4 ;
        RECT 4961.1 0 4963.91 30.425 ;
    END
    PORT
      LAYER Metal4 ;
        RECT 4972.34 0 4975.15 30.425 ;
    END
    PORT
      LAYER Metal4 ;
        RECT 4983.58 0 4986.39 30.425 ;
    END
    PORT
      LAYER Metal4 ;
        RECT 4994.82 0 4997.63 30.425 ;
    END
    PORT
      LAYER Metal4 ;
        RECT 5006.06 0 5008.87 30.425 ;
    END
    PORT
      LAYER Metal4 ;
        RECT 5017.3 0 5020.11 30.425 ;
    END
    PORT
      LAYER Metal4 ;
        RECT 5028.54 0 5031.35 30.425 ;
    END
    PORT
      LAYER Metal4 ;
        RECT 5039.78 0 5042.59 30.425 ;
    END
    PORT
      LAYER Metal4 ;
        RECT 5051.02 0 5053.83 30.425 ;
    END
    PORT
      LAYER Metal4 ;
        RECT 5062.26 0 5065.07 30.425 ;
    END
    PORT
      LAYER Metal4 ;
        RECT 5073.5 0 5076.31 30.425 ;
    END
    PORT
      LAYER Metal4 ;
        RECT 5084.74 0 5087.55 30.425 ;
    END
    PORT
      LAYER Metal4 ;
        RECT 5095.98 0 5098.79 30.425 ;
    END
    PORT
      LAYER Metal4 ;
        RECT 5107.22 0 5110.03 30.425 ;
    END
    PORT
      LAYER Metal4 ;
        RECT 5118.46 0 5121.27 30.425 ;
    END
    PORT
      LAYER Metal4 ;
        RECT 5129.7 0 5132.51 30.425 ;
    END
    PORT
      LAYER Metal4 ;
        RECT 5140.94 0 5143.75 30.425 ;
    END
    PORT
      LAYER Metal4 ;
        RECT 5152.18 0 5154.99 30.425 ;
    END
    PORT
      LAYER Metal4 ;
        RECT 5163.42 0 5166.23 30.425 ;
    END
    PORT
      LAYER Metal4 ;
        RECT 5174.66 0 5177.47 30.425 ;
    END
    PORT
      LAYER Metal4 ;
        RECT 5185.9 0 5188.71 30.425 ;
    END
    PORT
      LAYER Metal4 ;
        RECT 5197.14 0 5199.95 30.425 ;
    END
    PORT
      LAYER Metal4 ;
        RECT 5208.38 0 5211.19 30.425 ;
    END
    PORT
      LAYER Metal4 ;
        RECT 5219.62 0 5222.43 30.425 ;
    END
    PORT
      LAYER Metal4 ;
        RECT 5230.86 0 5233.67 30.425 ;
    END
    PORT
      LAYER Metal4 ;
        RECT 5242.1 0 5244.91 30.425 ;
    END
    PORT
      LAYER Metal4 ;
        RECT 5253.34 0 5256.15 30.425 ;
    END
    PORT
      LAYER Metal4 ;
        RECT 5264.58 0 5267.39 30.425 ;
    END
    PORT
      LAYER Metal4 ;
        RECT 5275.82 0 5278.63 30.425 ;
    END
    PORT
      LAYER Metal4 ;
        RECT 5287.06 0 5289.87 30.425 ;
    END
    PORT
      LAYER Metal4 ;
        RECT 5298.3 0 5301.11 30.425 ;
    END
    PORT
      LAYER Metal4 ;
        RECT 5309.54 0 5312.35 30.425 ;
    END
    PORT
      LAYER Metal4 ;
        RECT 5320.78 0 5323.59 30.425 ;
    END
    PORT
      LAYER Metal4 ;
        RECT 5332.02 0 5334.83 30.425 ;
    END
    PORT
      LAYER Metal4 ;
        RECT 5343.26 0 5346.07 30.425 ;
    END
    PORT
      LAYER Metal4 ;
        RECT 5354.5 0 5357.31 30.425 ;
    END
    PORT
      LAYER Metal4 ;
        RECT 5365.74 0 5368.55 30.425 ;
    END
    PORT
      LAYER Metal4 ;
        RECT 5376.98 0 5379.79 30.425 ;
    END
    PORT
      LAYER Metal4 ;
        RECT 5388.22 0 5391.03 30.425 ;
    END
    PORT
      LAYER Metal4 ;
        RECT 5399.46 0 5402.27 30.425 ;
    END
    PORT
      LAYER Metal4 ;
        RECT 5410.7 0 5413.51 30.425 ;
    END
    PORT
      LAYER Metal4 ;
        RECT 5421.94 0 5424.75 30.425 ;
    END
    PORT
      LAYER Metal4 ;
        RECT 5433.18 0 5435.99 30.425 ;
    END
    PORT
      LAYER Metal4 ;
        RECT 5444.42 0 5447.23 30.425 ;
    END
    PORT
      LAYER Metal4 ;
        RECT 5455.66 0 5458.47 30.425 ;
    END
    PORT
      LAYER Metal4 ;
        RECT 5466.9 0 5469.71 30.425 ;
    END
    PORT
      LAYER Metal4 ;
        RECT 5478.14 0 5480.95 30.425 ;
    END
    PORT
      LAYER Metal4 ;
        RECT 5489.38 0 5492.19 30.425 ;
    END
    PORT
      LAYER Metal4 ;
        RECT 5500.62 0 5503.43 30.425 ;
    END
    PORT
      LAYER Metal4 ;
        RECT 5511.86 0 5514.67 30.425 ;
    END
    PORT
      LAYER Metal4 ;
        RECT 5523.1 0 5525.91 30.425 ;
    END
    PORT
      LAYER Metal4 ;
        RECT 5534.34 0 5537.15 30.425 ;
    END
    PORT
      LAYER Metal4 ;
        RECT 5545.58 0 5548.39 30.425 ;
    END
    PORT
      LAYER Metal4 ;
        RECT 5556.82 0 5559.63 30.425 ;
    END
    PORT
      LAYER Metal4 ;
        RECT 5568.06 0 5570.87 30.425 ;
    END
    PORT
      LAYER Metal4 ;
        RECT 5579.3 0 5582.11 30.425 ;
    END
    PORT
      LAYER Metal4 ;
        RECT 5590.54 0 5593.35 30.425 ;
    END
    PORT
      LAYER Metal4 ;
        RECT 5601.78 0 5604.59 30.425 ;
    END
    PORT
      LAYER Metal4 ;
        RECT 5613.02 0 5615.83 30.425 ;
    END
    PORT
      LAYER Metal4 ;
        RECT 5624.26 0 5627.07 30.425 ;
    END
    PORT
      LAYER Metal4 ;
        RECT 5635.5 0 5638.31 30.425 ;
    END
    PORT
      LAYER Metal4 ;
        RECT 5646.74 0 5649.55 30.425 ;
    END
    PORT
      LAYER Metal4 ;
        RECT 5657.98 0 5660.79 30.425 ;
    END
    PORT
      LAYER Metal4 ;
        RECT 5669.22 0 5672.03 30.425 ;
    END
    PORT
      LAYER Metal4 ;
        RECT 5680.46 0 5683.27 30.425 ;
    END
    PORT
      LAYER Metal4 ;
        RECT 5691.7 0 5694.51 30.425 ;
    END
    PORT
      LAYER Metal4 ;
        RECT 5702.94 0 5705.75 30.425 ;
    END
    PORT
      LAYER Metal4 ;
        RECT 5714.18 0 5716.99 30.425 ;
    END
    PORT
      LAYER Metal4 ;
        RECT 5725.42 0 5728.23 30.425 ;
    END
    PORT
      LAYER Metal4 ;
        RECT 5736.66 0 5739.47 30.425 ;
    END
    PORT
      LAYER Metal4 ;
        RECT 5747.9 0 5750.71 30.425 ;
    END
    PORT
      LAYER Metal4 ;
        RECT 5759.14 0 5761.95 30.425 ;
    END
    PORT
      LAYER Metal4 ;
        RECT 5770.38 0 5773.19 30.425 ;
    END
    PORT
      LAYER Metal4 ;
        RECT 5781.62 0 5784.43 30.425 ;
    END
    PORT
      LAYER Metal4 ;
        RECT 5792.86 0 5795.67 30.425 ;
    END
    PORT
      LAYER Metal4 ;
        RECT 5804.1 0 5806.91 30.425 ;
    END
    PORT
      LAYER Metal4 ;
        RECT 5815.34 0 5818.15 30.425 ;
    END
    PORT
      LAYER Metal4 ;
        RECT 5826.58 0 5829.39 30.425 ;
    END
    PORT
      LAYER Metal4 ;
        RECT 5837.82 0 5840.63 30.425 ;
    END
    PORT
      LAYER Metal4 ;
        RECT 5849.06 0 5851.87 30.425 ;
    END
    PORT
      LAYER Metal4 ;
        RECT 5860.3 0 5863.11 30.425 ;
    END
    PORT
      LAYER Metal4 ;
        RECT 5871.54 0 5874.35 30.425 ;
    END
    PORT
      LAYER Metal4 ;
        RECT 5882.78 0 5885.59 30.425 ;
    END
    PORT
      LAYER Metal4 ;
        RECT 5894.02 0 5896.83 30.425 ;
    END
    PORT
      LAYER Metal4 ;
        RECT 5905.26 0 5908.07 30.425 ;
    END
    PORT
      LAYER Metal4 ;
        RECT 5916.5 0 5919.31 30.425 ;
    END
    PORT
      LAYER Metal4 ;
        RECT 5927.74 0 5930.55 30.425 ;
    END
    PORT
      LAYER Metal4 ;
        RECT 5938.98 0 5941.79 30.425 ;
    END
    PORT
      LAYER Metal4 ;
        RECT 5950.22 0 5953.03 30.425 ;
    END
    PORT
      LAYER Metal4 ;
        RECT 5961.46 0 5964.27 30.425 ;
    END
    PORT
      LAYER Metal4 ;
        RECT 5972.7 0 5975.51 30.425 ;
    END
    PORT
      LAYER Metal4 ;
        RECT 5983.94 0 5986.75 30.425 ;
    END
    PORT
      LAYER Metal4 ;
        RECT 5995.18 0 5997.99 30.425 ;
    END
    PORT
      LAYER Metal4 ;
        RECT 6006.42 0 6009.23 30.425 ;
    END
    PORT
      LAYER Metal4 ;
        RECT 6017.66 0 6020.47 30.425 ;
    END
    PORT
      LAYER Metal4 ;
        RECT 6028.9 0 6031.71 30.425 ;
    END
    PORT
      LAYER Metal4 ;
        RECT 6040.14 0 6042.95 30.425 ;
    END
    PORT
      LAYER Metal4 ;
        RECT 6051.38 0 6054.19 30.425 ;
    END
    PORT
      LAYER Metal4 ;
        RECT 6062.62 0 6065.43 30.425 ;
    END
    PORT
      LAYER Metal4 ;
        RECT 6073.86 0 6076.67 30.425 ;
    END
    PORT
      LAYER Metal4 ;
        RECT 6085.1 0 6087.91 30.425 ;
    END
    PORT
      LAYER Metal4 ;
        RECT 6096.34 0 6099.15 30.425 ;
    END
    PORT
      LAYER Metal4 ;
        RECT 6107.58 0 6110.39 30.425 ;
    END
    PORT
      LAYER Metal4 ;
        RECT 6118.82 0 6121.63 30.425 ;
    END
    PORT
      LAYER Metal4 ;
        RECT 6130.06 0 6132.87 30.425 ;
    END
    PORT
      LAYER Metal4 ;
        RECT 6141.3 0 6144.11 30.425 ;
    END
    PORT
      LAYER Metal4 ;
        RECT 6152.54 0 6155.35 30.425 ;
    END
    PORT
      LAYER Metal4 ;
        RECT 6163.78 0 6166.59 30.425 ;
    END
    PORT
      LAYER Metal4 ;
        RECT 6175.02 0 6177.83 30.425 ;
    END
    PORT
      LAYER Metal4 ;
        RECT 6186.26 0 6189.07 30.425 ;
    END
    PORT
      LAYER Metal4 ;
        RECT 6197.5 0 6200.31 30.425 ;
    END
    PORT
      LAYER Metal4 ;
        RECT 6208.74 0 6211.55 30.425 ;
    END
    PORT
      LAYER Metal4 ;
        RECT 6219.98 0 6222.79 30.425 ;
    END
    PORT
      LAYER Metal4 ;
        RECT 6231.22 0 6234.03 30.425 ;
    END
    PORT
      LAYER Metal4 ;
        RECT 6242.46 0 6245.27 30.425 ;
    END
    PORT
      LAYER Metal4 ;
        RECT 6253.7 0 6256.51 30.425 ;
    END
    PORT
      LAYER Metal4 ;
        RECT 6264.94 0 6267.75 30.425 ;
    END
    PORT
      LAYER Metal4 ;
        RECT 6276.18 0 6278.99 30.425 ;
    END
    PORT
      LAYER Metal4 ;
        RECT 6287.42 0 6290.23 30.425 ;
    END
    PORT
      LAYER Metal4 ;
        RECT 6298.66 0 6301.47 30.425 ;
    END
    PORT
      LAYER Metal4 ;
        RECT 6309.9 0 6312.71 30.425 ;
    END
    PORT
      LAYER Metal4 ;
        RECT 6321.14 0 6323.95 30.425 ;
    END
    PORT
      LAYER Metal4 ;
        RECT 6332.38 0 6335.19 30.425 ;
    END
    PORT
      LAYER Metal4 ;
        RECT 6343.62 0 6346.43 30.425 ;
    END
  END VDD
  PIN VDDARRAY
    DIRECTION INOUT ;
    USE POWER ;
    PORT
      LAYER Metal4 ;
        RECT 15.5 37.065 18.31 6373.08 ;
    END
    PORT
      LAYER Metal4 ;
        RECT 26.74 37.065 29.55 6373.08 ;
    END
    PORT
      LAYER Metal4 ;
        RECT 37.98 37.065 40.79 6373.08 ;
    END
    PORT
      LAYER Metal4 ;
        RECT 49.22 37.065 52.03 6373.08 ;
    END
    PORT
      LAYER Metal4 ;
        RECT 60.46 37.065 63.27 6373.08 ;
    END
    PORT
      LAYER Metal4 ;
        RECT 71.7 37.065 74.51 6373.08 ;
    END
    PORT
      LAYER Metal4 ;
        RECT 82.94 37.065 85.75 6373.08 ;
    END
    PORT
      LAYER Metal4 ;
        RECT 94.18 37.065 96.99 6373.08 ;
    END
    PORT
      LAYER Metal4 ;
        RECT 105.42 37.065 108.23 6373.08 ;
    END
    PORT
      LAYER Metal4 ;
        RECT 116.66 37.065 119.47 6373.08 ;
    END
    PORT
      LAYER Metal4 ;
        RECT 127.9 37.065 130.71 6373.08 ;
    END
    PORT
      LAYER Metal4 ;
        RECT 139.14 37.065 141.95 6373.08 ;
    END
    PORT
      LAYER Metal4 ;
        RECT 150.38 37.065 153.19 6373.08 ;
    END
    PORT
      LAYER Metal4 ;
        RECT 161.62 37.065 164.43 6373.08 ;
    END
    PORT
      LAYER Metal4 ;
        RECT 172.86 37.065 175.67 6373.08 ;
    END
    PORT
      LAYER Metal4 ;
        RECT 184.1 37.065 186.91 6373.08 ;
    END
    PORT
      LAYER Metal4 ;
        RECT 195.34 37.065 198.15 6373.08 ;
    END
    PORT
      LAYER Metal4 ;
        RECT 206.58 37.065 209.39 6373.08 ;
    END
    PORT
      LAYER Metal4 ;
        RECT 217.82 37.065 220.63 6373.08 ;
    END
    PORT
      LAYER Metal4 ;
        RECT 229.06 37.065 231.87 6373.08 ;
    END
    PORT
      LAYER Metal4 ;
        RECT 240.3 37.065 243.11 6373.08 ;
    END
    PORT
      LAYER Metal4 ;
        RECT 251.54 37.065 254.35 6373.08 ;
    END
    PORT
      LAYER Metal4 ;
        RECT 262.78 37.065 265.59 6373.08 ;
    END
    PORT
      LAYER Metal4 ;
        RECT 274.02 37.065 276.83 6373.08 ;
    END
    PORT
      LAYER Metal4 ;
        RECT 285.26 37.065 288.07 6373.08 ;
    END
    PORT
      LAYER Metal4 ;
        RECT 296.5 37.065 299.31 6373.08 ;
    END
    PORT
      LAYER Metal4 ;
        RECT 307.74 37.065 310.55 6373.08 ;
    END
    PORT
      LAYER Metal4 ;
        RECT 318.98 37.065 321.79 6373.08 ;
    END
    PORT
      LAYER Metal4 ;
        RECT 330.22 37.065 333.03 6373.08 ;
    END
    PORT
      LAYER Metal4 ;
        RECT 341.46 37.065 344.27 6373.08 ;
    END
    PORT
      LAYER Metal4 ;
        RECT 352.7 37.065 355.51 6373.08 ;
    END
    PORT
      LAYER Metal4 ;
        RECT 363.94 37.065 366.75 6373.08 ;
    END
    PORT
      LAYER Metal4 ;
        RECT 375.18 37.065 377.99 6373.08 ;
    END
    PORT
      LAYER Metal4 ;
        RECT 386.42 37.065 389.23 6373.08 ;
    END
    PORT
      LAYER Metal4 ;
        RECT 397.66 37.065 400.47 6373.08 ;
    END
    PORT
      LAYER Metal4 ;
        RECT 408.9 37.065 411.71 6373.08 ;
    END
    PORT
      LAYER Metal4 ;
        RECT 420.14 37.065 422.95 6373.08 ;
    END
    PORT
      LAYER Metal4 ;
        RECT 431.38 37.065 434.19 6373.08 ;
    END
    PORT
      LAYER Metal4 ;
        RECT 442.62 37.065 445.43 6373.08 ;
    END
    PORT
      LAYER Metal4 ;
        RECT 453.86 37.065 456.67 6373.08 ;
    END
    PORT
      LAYER Metal4 ;
        RECT 465.1 37.065 467.91 6373.08 ;
    END
    PORT
      LAYER Metal4 ;
        RECT 476.34 37.065 479.15 6373.08 ;
    END
    PORT
      LAYER Metal4 ;
        RECT 487.58 37.065 490.39 6373.08 ;
    END
    PORT
      LAYER Metal4 ;
        RECT 498.82 37.065 501.63 6373.08 ;
    END
    PORT
      LAYER Metal4 ;
        RECT 510.06 37.065 512.87 6373.08 ;
    END
    PORT
      LAYER Metal4 ;
        RECT 521.3 37.065 524.11 6373.08 ;
    END
    PORT
      LAYER Metal4 ;
        RECT 532.54 37.065 535.35 6373.08 ;
    END
    PORT
      LAYER Metal4 ;
        RECT 543.78 37.065 546.59 6373.08 ;
    END
    PORT
      LAYER Metal4 ;
        RECT 555.02 37.065 557.83 6373.08 ;
    END
    PORT
      LAYER Metal4 ;
        RECT 566.26 37.065 569.07 6373.08 ;
    END
    PORT
      LAYER Metal4 ;
        RECT 577.5 37.065 580.31 6373.08 ;
    END
    PORT
      LAYER Metal4 ;
        RECT 588.74 37.065 591.55 6373.08 ;
    END
    PORT
      LAYER Metal4 ;
        RECT 599.98 37.065 602.79 6373.08 ;
    END
    PORT
      LAYER Metal4 ;
        RECT 611.22 37.065 614.03 6373.08 ;
    END
    PORT
      LAYER Metal4 ;
        RECT 622.46 37.065 625.27 6373.08 ;
    END
    PORT
      LAYER Metal4 ;
        RECT 633.7 37.065 636.51 6373.08 ;
    END
    PORT
      LAYER Metal4 ;
        RECT 644.94 37.065 647.75 6373.08 ;
    END
    PORT
      LAYER Metal4 ;
        RECT 656.18 37.065 658.99 6373.08 ;
    END
    PORT
      LAYER Metal4 ;
        RECT 667.42 37.065 670.23 6373.08 ;
    END
    PORT
      LAYER Metal4 ;
        RECT 678.66 37.065 681.47 6373.08 ;
    END
    PORT
      LAYER Metal4 ;
        RECT 689.9 37.065 692.71 6373.08 ;
    END
    PORT
      LAYER Metal4 ;
        RECT 701.14 37.065 703.95 6373.08 ;
    END
    PORT
      LAYER Metal4 ;
        RECT 712.38 37.065 715.19 6373.08 ;
    END
    PORT
      LAYER Metal4 ;
        RECT 723.62 37.065 726.43 6373.08 ;
    END
    PORT
      LAYER Metal4 ;
        RECT 734.86 37.065 737.67 6373.08 ;
    END
    PORT
      LAYER Metal4 ;
        RECT 746.1 37.065 748.91 6373.08 ;
    END
    PORT
      LAYER Metal4 ;
        RECT 757.34 37.065 760.15 6373.08 ;
    END
    PORT
      LAYER Metal4 ;
        RECT 768.58 37.065 771.39 6373.08 ;
    END
    PORT
      LAYER Metal4 ;
        RECT 779.82 37.065 782.63 6373.08 ;
    END
    PORT
      LAYER Metal4 ;
        RECT 791.06 37.065 793.87 6373.08 ;
    END
    PORT
      LAYER Metal4 ;
        RECT 802.3 37.065 805.11 6373.08 ;
    END
    PORT
      LAYER Metal4 ;
        RECT 813.54 37.065 816.35 6373.08 ;
    END
    PORT
      LAYER Metal4 ;
        RECT 824.78 37.065 827.59 6373.08 ;
    END
    PORT
      LAYER Metal4 ;
        RECT 836.02 37.065 838.83 6373.08 ;
    END
    PORT
      LAYER Metal4 ;
        RECT 847.26 37.065 850.07 6373.08 ;
    END
    PORT
      LAYER Metal4 ;
        RECT 858.5 37.065 861.31 6373.08 ;
    END
    PORT
      LAYER Metal4 ;
        RECT 869.74 37.065 872.55 6373.08 ;
    END
    PORT
      LAYER Metal4 ;
        RECT 880.98 37.065 883.79 6373.08 ;
    END
    PORT
      LAYER Metal4 ;
        RECT 892.22 37.065 895.03 6373.08 ;
    END
    PORT
      LAYER Metal4 ;
        RECT 903.46 37.065 906.27 6373.08 ;
    END
    PORT
      LAYER Metal4 ;
        RECT 914.7 37.065 917.51 6373.08 ;
    END
    PORT
      LAYER Metal4 ;
        RECT 925.94 37.065 928.75 6373.08 ;
    END
    PORT
      LAYER Metal4 ;
        RECT 937.18 37.065 939.99 6373.08 ;
    END
    PORT
      LAYER Metal4 ;
        RECT 948.42 37.065 951.23 6373.08 ;
    END
    PORT
      LAYER Metal4 ;
        RECT 959.66 37.065 962.47 6373.08 ;
    END
    PORT
      LAYER Metal4 ;
        RECT 970.9 37.065 973.71 6373.08 ;
    END
    PORT
      LAYER Metal4 ;
        RECT 982.14 37.065 984.95 6373.08 ;
    END
    PORT
      LAYER Metal4 ;
        RECT 993.38 37.065 996.19 6373.08 ;
    END
    PORT
      LAYER Metal4 ;
        RECT 1004.62 37.065 1007.43 6373.08 ;
    END
    PORT
      LAYER Metal4 ;
        RECT 1015.86 37.065 1018.67 6373.08 ;
    END
    PORT
      LAYER Metal4 ;
        RECT 1027.1 37.065 1029.91 6373.08 ;
    END
    PORT
      LAYER Metal4 ;
        RECT 1038.34 37.065 1041.15 6373.08 ;
    END
    PORT
      LAYER Metal4 ;
        RECT 1049.58 37.065 1052.39 6373.08 ;
    END
    PORT
      LAYER Metal4 ;
        RECT 1060.82 37.065 1063.63 6373.08 ;
    END
    PORT
      LAYER Metal4 ;
        RECT 1072.06 37.065 1074.87 6373.08 ;
    END
    PORT
      LAYER Metal4 ;
        RECT 1083.3 37.065 1086.11 6373.08 ;
    END
    PORT
      LAYER Metal4 ;
        RECT 1094.54 37.065 1097.35 6373.08 ;
    END
    PORT
      LAYER Metal4 ;
        RECT 1105.78 37.065 1108.59 6373.08 ;
    END
    PORT
      LAYER Metal4 ;
        RECT 1117.02 37.065 1119.83 6373.08 ;
    END
    PORT
      LAYER Metal4 ;
        RECT 1128.26 37.065 1131.07 6373.08 ;
    END
    PORT
      LAYER Metal4 ;
        RECT 1139.5 37.065 1142.31 6373.08 ;
    END
    PORT
      LAYER Metal4 ;
        RECT 1150.74 37.065 1153.55 6373.08 ;
    END
    PORT
      LAYER Metal4 ;
        RECT 1161.98 37.065 1164.79 6373.08 ;
    END
    PORT
      LAYER Metal4 ;
        RECT 1173.22 37.065 1176.03 6373.08 ;
    END
    PORT
      LAYER Metal4 ;
        RECT 1184.46 37.065 1187.27 6373.08 ;
    END
    PORT
      LAYER Metal4 ;
        RECT 1195.7 37.065 1198.51 6373.08 ;
    END
    PORT
      LAYER Metal4 ;
        RECT 1206.94 37.065 1209.75 6373.08 ;
    END
    PORT
      LAYER Metal4 ;
        RECT 1218.18 37.065 1220.99 6373.08 ;
    END
    PORT
      LAYER Metal4 ;
        RECT 1229.42 37.065 1232.23 6373.08 ;
    END
    PORT
      LAYER Metal4 ;
        RECT 1240.66 37.065 1243.47 6373.08 ;
    END
    PORT
      LAYER Metal4 ;
        RECT 1251.9 37.065 1254.71 6373.08 ;
    END
    PORT
      LAYER Metal4 ;
        RECT 1263.14 37.065 1265.95 6373.08 ;
    END
    PORT
      LAYER Metal4 ;
        RECT 1274.38 37.065 1277.19 6373.08 ;
    END
    PORT
      LAYER Metal4 ;
        RECT 1285.62 37.065 1288.43 6373.08 ;
    END
    PORT
      LAYER Metal4 ;
        RECT 1296.86 37.065 1299.67 6373.08 ;
    END
    PORT
      LAYER Metal4 ;
        RECT 1308.1 37.065 1310.91 6373.08 ;
    END
    PORT
      LAYER Metal4 ;
        RECT 1319.34 37.065 1322.15 6373.08 ;
    END
    PORT
      LAYER Metal4 ;
        RECT 1330.58 37.065 1333.39 6373.08 ;
    END
    PORT
      LAYER Metal4 ;
        RECT 1341.82 37.065 1344.63 6373.08 ;
    END
    PORT
      LAYER Metal4 ;
        RECT 1353.06 37.065 1355.87 6373.08 ;
    END
    PORT
      LAYER Metal4 ;
        RECT 1364.3 37.065 1367.11 6373.08 ;
    END
    PORT
      LAYER Metal4 ;
        RECT 1375.54 37.065 1378.35 6373.08 ;
    END
    PORT
      LAYER Metal4 ;
        RECT 1386.78 37.065 1389.59 6373.08 ;
    END
    PORT
      LAYER Metal4 ;
        RECT 1398.02 37.065 1400.83 6373.08 ;
    END
    PORT
      LAYER Metal4 ;
        RECT 1409.26 37.065 1412.07 6373.08 ;
    END
    PORT
      LAYER Metal4 ;
        RECT 1420.5 37.065 1423.31 6373.08 ;
    END
    PORT
      LAYER Metal4 ;
        RECT 1431.74 37.065 1434.55 6373.08 ;
    END
    PORT
      LAYER Metal4 ;
        RECT 1442.98 37.065 1445.79 6373.08 ;
    END
    PORT
      LAYER Metal4 ;
        RECT 1454.22 37.065 1457.03 6373.08 ;
    END
    PORT
      LAYER Metal4 ;
        RECT 1465.46 37.065 1468.27 6373.08 ;
    END
    PORT
      LAYER Metal4 ;
        RECT 1476.7 37.065 1479.51 6373.08 ;
    END
    PORT
      LAYER Metal4 ;
        RECT 1487.94 37.065 1490.75 6373.08 ;
    END
    PORT
      LAYER Metal4 ;
        RECT 1499.18 37.065 1501.99 6373.08 ;
    END
    PORT
      LAYER Metal4 ;
        RECT 1510.42 37.065 1513.23 6373.08 ;
    END
    PORT
      LAYER Metal4 ;
        RECT 1521.66 37.065 1524.47 6373.08 ;
    END
    PORT
      LAYER Metal4 ;
        RECT 1532.9 37.065 1535.71 6373.08 ;
    END
    PORT
      LAYER Metal4 ;
        RECT 1544.14 37.065 1546.95 6373.08 ;
    END
    PORT
      LAYER Metal4 ;
        RECT 1555.38 37.065 1558.19 6373.08 ;
    END
    PORT
      LAYER Metal4 ;
        RECT 1566.62 37.065 1569.43 6373.08 ;
    END
    PORT
      LAYER Metal4 ;
        RECT 1577.86 37.065 1580.67 6373.08 ;
    END
    PORT
      LAYER Metal4 ;
        RECT 1589.1 37.065 1591.91 6373.08 ;
    END
    PORT
      LAYER Metal4 ;
        RECT 1600.34 37.065 1603.15 6373.08 ;
    END
    PORT
      LAYER Metal4 ;
        RECT 1611.58 37.065 1614.39 6373.08 ;
    END
    PORT
      LAYER Metal4 ;
        RECT 1622.82 37.065 1625.63 6373.08 ;
    END
    PORT
      LAYER Metal4 ;
        RECT 1634.06 37.065 1636.87 6373.08 ;
    END
    PORT
      LAYER Metal4 ;
        RECT 1645.3 37.065 1648.11 6373.08 ;
    END
    PORT
      LAYER Metal4 ;
        RECT 1656.54 37.065 1659.35 6373.08 ;
    END
    PORT
      LAYER Metal4 ;
        RECT 1667.78 37.065 1670.59 6373.08 ;
    END
    PORT
      LAYER Metal4 ;
        RECT 1679.02 37.065 1681.83 6373.08 ;
    END
    PORT
      LAYER Metal4 ;
        RECT 1690.26 37.065 1693.07 6373.08 ;
    END
    PORT
      LAYER Metal4 ;
        RECT 1701.5 37.065 1704.31 6373.08 ;
    END
    PORT
      LAYER Metal4 ;
        RECT 1712.74 37.065 1715.55 6373.08 ;
    END
    PORT
      LAYER Metal4 ;
        RECT 1723.98 37.065 1726.79 6373.08 ;
    END
    PORT
      LAYER Metal4 ;
        RECT 1735.22 37.065 1738.03 6373.08 ;
    END
    PORT
      LAYER Metal4 ;
        RECT 1746.46 37.065 1749.27 6373.08 ;
    END
    PORT
      LAYER Metal4 ;
        RECT 1757.7 37.065 1760.51 6373.08 ;
    END
    PORT
      LAYER Metal4 ;
        RECT 1768.94 37.065 1771.75 6373.08 ;
    END
    PORT
      LAYER Metal4 ;
        RECT 1780.18 37.065 1782.99 6373.08 ;
    END
    PORT
      LAYER Metal4 ;
        RECT 1791.42 37.065 1794.23 6373.08 ;
    END
    PORT
      LAYER Metal4 ;
        RECT 1802.66 37.065 1805.47 6373.08 ;
    END
    PORT
      LAYER Metal4 ;
        RECT 1813.9 37.065 1816.71 6373.08 ;
    END
    PORT
      LAYER Metal4 ;
        RECT 1825.14 37.065 1827.95 6373.08 ;
    END
    PORT
      LAYER Metal4 ;
        RECT 1836.38 37.065 1839.19 6373.08 ;
    END
    PORT
      LAYER Metal4 ;
        RECT 1847.62 37.065 1850.43 6373.08 ;
    END
    PORT
      LAYER Metal4 ;
        RECT 1858.86 37.065 1861.67 6373.08 ;
    END
    PORT
      LAYER Metal4 ;
        RECT 1870.1 37.065 1872.91 6373.08 ;
    END
    PORT
      LAYER Metal4 ;
        RECT 1881.34 37.065 1884.15 6373.08 ;
    END
    PORT
      LAYER Metal4 ;
        RECT 1892.58 37.065 1895.39 6373.08 ;
    END
    PORT
      LAYER Metal4 ;
        RECT 1903.82 37.065 1906.63 6373.08 ;
    END
    PORT
      LAYER Metal4 ;
        RECT 1915.06 37.065 1917.87 6373.08 ;
    END
    PORT
      LAYER Metal4 ;
        RECT 1926.3 37.065 1929.11 6373.08 ;
    END
    PORT
      LAYER Metal4 ;
        RECT 1937.54 37.065 1940.35 6373.08 ;
    END
    PORT
      LAYER Metal4 ;
        RECT 1948.78 37.065 1951.59 6373.08 ;
    END
    PORT
      LAYER Metal4 ;
        RECT 1960.02 37.065 1962.83 6373.08 ;
    END
    PORT
      LAYER Metal4 ;
        RECT 1971.26 37.065 1974.07 6373.08 ;
    END
    PORT
      LAYER Metal4 ;
        RECT 1982.5 37.065 1985.31 6373.08 ;
    END
    PORT
      LAYER Metal4 ;
        RECT 1993.74 37.065 1996.55 6373.08 ;
    END
    PORT
      LAYER Metal4 ;
        RECT 2004.98 37.065 2007.79 6373.08 ;
    END
    PORT
      LAYER Metal4 ;
        RECT 2016.22 37.065 2019.03 6373.08 ;
    END
    PORT
      LAYER Metal4 ;
        RECT 2027.46 37.065 2030.27 6373.08 ;
    END
    PORT
      LAYER Metal4 ;
        RECT 2038.7 37.065 2041.51 6373.08 ;
    END
    PORT
      LAYER Metal4 ;
        RECT 2049.94 37.065 2052.75 6373.08 ;
    END
    PORT
      LAYER Metal4 ;
        RECT 2061.18 37.065 2063.99 6373.08 ;
    END
    PORT
      LAYER Metal4 ;
        RECT 2072.42 37.065 2075.23 6373.08 ;
    END
    PORT
      LAYER Metal4 ;
        RECT 2083.66 37.065 2086.47 6373.08 ;
    END
    PORT
      LAYER Metal4 ;
        RECT 2094.9 37.065 2097.71 6373.08 ;
    END
    PORT
      LAYER Metal4 ;
        RECT 2106.14 37.065 2108.95 6373.08 ;
    END
    PORT
      LAYER Metal4 ;
        RECT 2117.38 37.065 2120.19 6373.08 ;
    END
    PORT
      LAYER Metal4 ;
        RECT 2128.62 37.065 2131.43 6373.08 ;
    END
    PORT
      LAYER Metal4 ;
        RECT 2139.86 37.065 2142.67 6373.08 ;
    END
    PORT
      LAYER Metal4 ;
        RECT 2151.1 37.065 2153.91 6373.08 ;
    END
    PORT
      LAYER Metal4 ;
        RECT 2162.34 37.065 2165.15 6373.08 ;
    END
    PORT
      LAYER Metal4 ;
        RECT 2173.58 37.065 2176.39 6373.08 ;
    END
    PORT
      LAYER Metal4 ;
        RECT 2184.82 37.065 2187.63 6373.08 ;
    END
    PORT
      LAYER Metal4 ;
        RECT 2196.06 37.065 2198.87 6373.08 ;
    END
    PORT
      LAYER Metal4 ;
        RECT 2207.3 37.065 2210.11 6373.08 ;
    END
    PORT
      LAYER Metal4 ;
        RECT 2218.54 37.065 2221.35 6373.08 ;
    END
    PORT
      LAYER Metal4 ;
        RECT 2229.78 37.065 2232.59 6373.08 ;
    END
    PORT
      LAYER Metal4 ;
        RECT 2241.02 37.065 2243.83 6373.08 ;
    END
    PORT
      LAYER Metal4 ;
        RECT 2252.26 37.065 2255.07 6373.08 ;
    END
    PORT
      LAYER Metal4 ;
        RECT 2263.5 37.065 2266.31 6373.08 ;
    END
    PORT
      LAYER Metal4 ;
        RECT 2274.74 37.065 2277.55 6373.08 ;
    END
    PORT
      LAYER Metal4 ;
        RECT 2285.98 37.065 2288.79 6373.08 ;
    END
    PORT
      LAYER Metal4 ;
        RECT 2297.22 37.065 2300.03 6373.08 ;
    END
    PORT
      LAYER Metal4 ;
        RECT 2308.46 37.065 2311.27 6373.08 ;
    END
    PORT
      LAYER Metal4 ;
        RECT 2319.7 37.065 2322.51 6373.08 ;
    END
    PORT
      LAYER Metal4 ;
        RECT 2330.94 37.065 2333.75 6373.08 ;
    END
    PORT
      LAYER Metal4 ;
        RECT 2342.18 37.065 2344.99 6373.08 ;
    END
    PORT
      LAYER Metal4 ;
        RECT 2353.42 37.065 2356.23 6373.08 ;
    END
    PORT
      LAYER Metal4 ;
        RECT 2364.66 37.065 2367.47 6373.08 ;
    END
    PORT
      LAYER Metal4 ;
        RECT 2375.9 37.065 2378.71 6373.08 ;
    END
    PORT
      LAYER Metal4 ;
        RECT 2387.14 37.065 2389.95 6373.08 ;
    END
    PORT
      LAYER Metal4 ;
        RECT 2398.38 37.065 2401.19 6373.08 ;
    END
    PORT
      LAYER Metal4 ;
        RECT 2409.62 37.065 2412.43 6373.08 ;
    END
    PORT
      LAYER Metal4 ;
        RECT 2420.86 37.065 2423.67 6373.08 ;
    END
    PORT
      LAYER Metal4 ;
        RECT 2432.1 37.065 2434.91 6373.08 ;
    END
    PORT
      LAYER Metal4 ;
        RECT 2443.34 37.065 2446.15 6373.08 ;
    END
    PORT
      LAYER Metal4 ;
        RECT 2454.58 37.065 2457.39 6373.08 ;
    END
    PORT
      LAYER Metal4 ;
        RECT 2465.82 37.065 2468.63 6373.08 ;
    END
    PORT
      LAYER Metal4 ;
        RECT 2477.06 37.065 2479.87 6373.08 ;
    END
    PORT
      LAYER Metal4 ;
        RECT 2488.3 37.065 2491.11 6373.08 ;
    END
    PORT
      LAYER Metal4 ;
        RECT 2499.54 37.065 2502.35 6373.08 ;
    END
    PORT
      LAYER Metal4 ;
        RECT 2510.78 37.065 2513.59 6373.08 ;
    END
    PORT
      LAYER Metal4 ;
        RECT 2522.02 37.065 2524.83 6373.08 ;
    END
    PORT
      LAYER Metal4 ;
        RECT 2533.26 37.065 2536.07 6373.08 ;
    END
    PORT
      LAYER Metal4 ;
        RECT 2544.5 37.065 2547.31 6373.08 ;
    END
    PORT
      LAYER Metal4 ;
        RECT 2555.74 37.065 2558.55 6373.08 ;
    END
    PORT
      LAYER Metal4 ;
        RECT 2566.98 37.065 2569.79 6373.08 ;
    END
    PORT
      LAYER Metal4 ;
        RECT 2578.22 37.065 2581.03 6373.08 ;
    END
    PORT
      LAYER Metal4 ;
        RECT 2589.46 37.065 2592.27 6373.08 ;
    END
    PORT
      LAYER Metal4 ;
        RECT 2600.7 37.065 2603.51 6373.08 ;
    END
    PORT
      LAYER Metal4 ;
        RECT 2611.94 37.065 2614.75 6373.08 ;
    END
    PORT
      LAYER Metal4 ;
        RECT 2623.18 37.065 2625.99 6373.08 ;
    END
    PORT
      LAYER Metal4 ;
        RECT 2634.42 37.065 2637.23 6373.08 ;
    END
    PORT
      LAYER Metal4 ;
        RECT 2645.66 37.065 2648.47 6373.08 ;
    END
    PORT
      LAYER Metal4 ;
        RECT 2656.9 37.065 2659.71 6373.08 ;
    END
    PORT
      LAYER Metal4 ;
        RECT 2668.14 37.065 2670.95 6373.08 ;
    END
    PORT
      LAYER Metal4 ;
        RECT 2679.38 37.065 2682.19 6373.08 ;
    END
    PORT
      LAYER Metal4 ;
        RECT 2690.62 37.065 2693.43 6373.08 ;
    END
    PORT
      LAYER Metal4 ;
        RECT 2701.86 37.065 2704.67 6373.08 ;
    END
    PORT
      LAYER Metal4 ;
        RECT 2713.1 37.065 2715.91 6373.08 ;
    END
    PORT
      LAYER Metal4 ;
        RECT 2724.34 37.065 2727.15 6373.08 ;
    END
    PORT
      LAYER Metal4 ;
        RECT 2735.58 37.065 2738.39 6373.08 ;
    END
    PORT
      LAYER Metal4 ;
        RECT 2746.82 37.065 2749.63 6373.08 ;
    END
    PORT
      LAYER Metal4 ;
        RECT 2758.06 37.065 2760.87 6373.08 ;
    END
    PORT
      LAYER Metal4 ;
        RECT 2769.3 37.065 2772.11 6373.08 ;
    END
    PORT
      LAYER Metal4 ;
        RECT 2780.54 37.065 2783.35 6373.08 ;
    END
    PORT
      LAYER Metal4 ;
        RECT 2791.78 37.065 2794.59 6373.08 ;
    END
    PORT
      LAYER Metal4 ;
        RECT 2803.02 37.065 2805.83 6373.08 ;
    END
    PORT
      LAYER Metal4 ;
        RECT 2814.26 37.065 2817.07 6373.08 ;
    END
    PORT
      LAYER Metal4 ;
        RECT 2825.5 37.065 2828.31 6373.08 ;
    END
    PORT
      LAYER Metal4 ;
        RECT 2836.74 37.065 2839.55 6373.08 ;
    END
    PORT
      LAYER Metal4 ;
        RECT 2847.98 37.065 2850.79 6373.08 ;
    END
    PORT
      LAYER Metal4 ;
        RECT 2859.22 37.065 2862.03 6373.08 ;
    END
    PORT
      LAYER Metal4 ;
        RECT 2870.46 37.065 2873.27 6373.08 ;
    END
    PORT
      LAYER Metal4 ;
        RECT 2881.7 37.065 2884.51 6373.08 ;
    END
    PORT
      LAYER Metal4 ;
        RECT 2892.94 37.065 2895.75 6373.08 ;
    END
    PORT
      LAYER Metal4 ;
        RECT 2904.18 37.065 2906.99 6373.08 ;
    END
    PORT
      LAYER Metal4 ;
        RECT 2915.42 37.065 2918.23 6373.08 ;
    END
    PORT
      LAYER Metal4 ;
        RECT 2926.66 37.065 2929.47 6373.08 ;
    END
    PORT
      LAYER Metal4 ;
        RECT 2937.9 37.065 2940.71 6373.08 ;
    END
    PORT
      LAYER Metal4 ;
        RECT 2949.14 37.065 2951.95 6373.08 ;
    END
    PORT
      LAYER Metal4 ;
        RECT 2960.38 37.065 2963.19 6373.08 ;
    END
    PORT
      LAYER Metal4 ;
        RECT 2971.62 37.065 2974.43 6373.08 ;
    END
    PORT
      LAYER Metal4 ;
        RECT 2982.86 37.065 2985.67 6373.08 ;
    END
    PORT
      LAYER Metal4 ;
        RECT 2994.1 37.065 2996.91 6373.08 ;
    END
    PORT
      LAYER Metal4 ;
        RECT 3005.34 37.065 3008.15 6373.08 ;
    END
    PORT
      LAYER Metal4 ;
        RECT 3016.58 37.065 3019.39 6373.08 ;
    END
    PORT
      LAYER Metal4 ;
        RECT 3027.82 37.065 3030.63 6373.08 ;
    END
    PORT
      LAYER Metal4 ;
        RECT 3039.06 37.065 3041.87 6373.08 ;
    END
    PORT
      LAYER Metal4 ;
        RECT 3050.3 37.065 3053.11 6373.08 ;
    END
    PORT
      LAYER Metal4 ;
        RECT 3061.54 37.065 3064.35 6373.08 ;
    END
    PORT
      LAYER Metal4 ;
        RECT 3072.78 37.065 3075.59 6373.08 ;
    END
    PORT
      LAYER Metal4 ;
        RECT 3084.02 37.065 3086.83 6373.08 ;
    END
    PORT
      LAYER Metal4 ;
        RECT 3095.26 37.065 3098.07 6373.08 ;
    END
    PORT
      LAYER Metal4 ;
        RECT 3106.5 37.065 3109.31 6373.08 ;
    END
    PORT
      LAYER Metal4 ;
        RECT 3117.74 37.065 3120.55 6373.08 ;
    END
    PORT
      LAYER Metal4 ;
        RECT 3128.98 37.065 3131.79 6373.08 ;
    END
    PORT
      LAYER Metal4 ;
        RECT 3140.22 37.065 3143.03 6373.08 ;
    END
    PORT
      LAYER Metal4 ;
        RECT 3151.46 37.065 3154.27 6373.08 ;
    END
    PORT
      LAYER Metal4 ;
        RECT 3162.7 37.065 3165.51 6373.08 ;
    END
    PORT
      LAYER Metal4 ;
        RECT 3173.94 37.065 3176.75 6373.08 ;
    END
    PORT
      LAYER Metal4 ;
        RECT 3185.18 37.065 3187.99 6373.08 ;
    END
    PORT
      LAYER Metal4 ;
        RECT 3196.42 37.065 3199.23 6373.08 ;
    END
    PORT
      LAYER Metal4 ;
        RECT 3207.66 37.065 3210.47 6373.08 ;
    END
    PORT
      LAYER Metal4 ;
        RECT 3218.9 37.065 3221.71 6373.08 ;
    END
    PORT
      LAYER Metal4 ;
        RECT 3230.14 37.065 3232.95 6373.08 ;
    END
    PORT
      LAYER Metal4 ;
        RECT 3241.38 37.065 3244.19 6373.08 ;
    END
    PORT
      LAYER Metal4 ;
        RECT 3252.62 37.065 3255.43 6373.08 ;
    END
    PORT
      LAYER Metal4 ;
        RECT 3263.86 37.065 3266.67 6373.08 ;
    END
    PORT
      LAYER Metal4 ;
        RECT 3275.1 37.065 3277.91 6373.08 ;
    END
    PORT
      LAYER Metal4 ;
        RECT 3286.34 37.065 3289.15 6373.08 ;
    END
    PORT
      LAYER Metal4 ;
        RECT 3297.58 37.065 3300.39 6373.08 ;
    END
    PORT
      LAYER Metal4 ;
        RECT 3308.82 37.065 3311.63 6373.08 ;
    END
    PORT
      LAYER Metal4 ;
        RECT 3320.06 37.065 3322.87 6373.08 ;
    END
    PORT
      LAYER Metal4 ;
        RECT 3331.3 37.065 3334.11 6373.08 ;
    END
    PORT
      LAYER Metal4 ;
        RECT 3342.54 37.065 3345.35 6373.08 ;
    END
    PORT
      LAYER Metal4 ;
        RECT 3353.78 37.065 3356.59 6373.08 ;
    END
    PORT
      LAYER Metal4 ;
        RECT 3365.02 37.065 3367.83 6373.08 ;
    END
    PORT
      LAYER Metal4 ;
        RECT 3376.26 37.065 3379.07 6373.08 ;
    END
    PORT
      LAYER Metal4 ;
        RECT 3387.5 37.065 3390.31 6373.08 ;
    END
    PORT
      LAYER Metal4 ;
        RECT 3398.74 37.065 3401.55 6373.08 ;
    END
    PORT
      LAYER Metal4 ;
        RECT 3409.98 37.065 3412.79 6373.08 ;
    END
    PORT
      LAYER Metal4 ;
        RECT 3421.22 37.065 3424.03 6373.08 ;
    END
    PORT
      LAYER Metal4 ;
        RECT 3432.46 37.065 3435.27 6373.08 ;
    END
    PORT
      LAYER Metal4 ;
        RECT 3443.7 37.065 3446.51 6373.08 ;
    END
    PORT
      LAYER Metal4 ;
        RECT 3454.94 37.065 3457.75 6373.08 ;
    END
    PORT
      LAYER Metal4 ;
        RECT 3466.18 37.065 3468.99 6373.08 ;
    END
    PORT
      LAYER Metal4 ;
        RECT 3477.42 37.065 3480.23 6373.08 ;
    END
    PORT
      LAYER Metal4 ;
        RECT 3488.66 37.065 3491.47 6373.08 ;
    END
    PORT
      LAYER Metal4 ;
        RECT 3499.9 37.065 3502.71 6373.08 ;
    END
    PORT
      LAYER Metal4 ;
        RECT 3511.14 37.065 3513.95 6373.08 ;
    END
    PORT
      LAYER Metal4 ;
        RECT 3522.38 37.065 3525.19 6373.08 ;
    END
    PORT
      LAYER Metal4 ;
        RECT 3533.62 37.065 3536.43 6373.08 ;
    END
    PORT
      LAYER Metal4 ;
        RECT 3544.86 37.065 3547.67 6373.08 ;
    END
    PORT
      LAYER Metal4 ;
        RECT 3556.1 37.065 3558.91 6373.08 ;
    END
    PORT
      LAYER Metal4 ;
        RECT 3567.34 37.065 3570.15 6373.08 ;
    END
    PORT
      LAYER Metal4 ;
        RECT 3578.58 37.065 3581.39 6373.08 ;
    END
    PORT
      LAYER Metal4 ;
        RECT 3589.82 37.065 3592.63 6373.08 ;
    END
    PORT
      LAYER Metal4 ;
        RECT 3601.06 37.065 3603.87 6373.08 ;
    END
    PORT
      LAYER Metal4 ;
        RECT 3612.3 37.065 3615.11 6373.08 ;
    END
    PORT
      LAYER Metal4 ;
        RECT 3623.54 37.065 3626.35 6373.08 ;
    END
    PORT
      LAYER Metal4 ;
        RECT 3634.78 37.065 3637.59 6373.08 ;
    END
    PORT
      LAYER Metal4 ;
        RECT 3646.02 37.065 3648.83 6373.08 ;
    END
    PORT
      LAYER Metal4 ;
        RECT 3657.26 37.065 3660.07 6373.08 ;
    END
    PORT
      LAYER Metal4 ;
        RECT 3668.5 37.065 3671.31 6373.08 ;
    END
    PORT
      LAYER Metal4 ;
        RECT 3679.74 37.065 3682.55 6373.08 ;
    END
    PORT
      LAYER Metal4 ;
        RECT 3690.98 37.065 3693.79 6373.08 ;
    END
    PORT
      LAYER Metal4 ;
        RECT 3702.22 37.065 3705.03 6373.08 ;
    END
    PORT
      LAYER Metal4 ;
        RECT 3713.46 37.065 3716.27 6373.08 ;
    END
    PORT
      LAYER Metal4 ;
        RECT 3724.7 37.065 3727.51 6373.08 ;
    END
    PORT
      LAYER Metal4 ;
        RECT 3735.94 37.065 3738.75 6373.08 ;
    END
    PORT
      LAYER Metal4 ;
        RECT 3747.18 37.065 3749.99 6373.08 ;
    END
    PORT
      LAYER Metal4 ;
        RECT 3758.42 37.065 3761.23 6373.08 ;
    END
    PORT
      LAYER Metal4 ;
        RECT 3769.66 37.065 3772.47 6373.08 ;
    END
    PORT
      LAYER Metal4 ;
        RECT 3780.9 37.065 3783.71 6373.08 ;
    END
    PORT
      LAYER Metal4 ;
        RECT 3792.14 37.065 3794.95 6373.08 ;
    END
    PORT
      LAYER Metal4 ;
        RECT 3803.38 37.065 3806.19 6373.08 ;
    END
    PORT
      LAYER Metal4 ;
        RECT 3814.62 37.065 3817.43 6373.08 ;
    END
    PORT
      LAYER Metal4 ;
        RECT 3825.86 37.065 3828.67 6373.08 ;
    END
    PORT
      LAYER Metal4 ;
        RECT 3837.1 37.065 3839.91 6373.08 ;
    END
    PORT
      LAYER Metal4 ;
        RECT 3848.34 37.065 3851.15 6373.08 ;
    END
    PORT
      LAYER Metal4 ;
        RECT 3859.58 37.065 3862.39 6373.08 ;
    END
    PORT
      LAYER Metal4 ;
        RECT 3870.82 37.065 3873.63 6373.08 ;
    END
    PORT
      LAYER Metal4 ;
        RECT 3882.06 37.065 3884.87 6373.08 ;
    END
    PORT
      LAYER Metal4 ;
        RECT 3893.3 37.065 3896.11 6373.08 ;
    END
    PORT
      LAYER Metal4 ;
        RECT 3904.54 37.065 3907.35 6373.08 ;
    END
    PORT
      LAYER Metal4 ;
        RECT 3915.78 37.065 3918.59 6373.08 ;
    END
    PORT
      LAYER Metal4 ;
        RECT 3927.02 37.065 3929.83 6373.08 ;
    END
    PORT
      LAYER Metal4 ;
        RECT 3938.26 37.065 3941.07 6373.08 ;
    END
    PORT
      LAYER Metal4 ;
        RECT 3949.5 37.065 3952.31 6373.08 ;
    END
    PORT
      LAYER Metal4 ;
        RECT 3960.74 37.065 3963.55 6373.08 ;
    END
    PORT
      LAYER Metal4 ;
        RECT 3971.98 37.065 3974.79 6373.08 ;
    END
    PORT
      LAYER Metal4 ;
        RECT 3983.22 37.065 3986.03 6373.08 ;
    END
    PORT
      LAYER Metal4 ;
        RECT 3994.46 37.065 3997.27 6373.08 ;
    END
    PORT
      LAYER Metal4 ;
        RECT 4005.7 37.065 4008.51 6373.08 ;
    END
    PORT
      LAYER Metal4 ;
        RECT 4016.94 37.065 4019.75 6373.08 ;
    END
    PORT
      LAYER Metal4 ;
        RECT 4028.18 37.065 4030.99 6373.08 ;
    END
    PORT
      LAYER Metal4 ;
        RECT 4039.42 37.065 4042.23 6373.08 ;
    END
    PORT
      LAYER Metal4 ;
        RECT 4050.66 37.065 4053.47 6373.08 ;
    END
    PORT
      LAYER Metal4 ;
        RECT 4061.9 37.065 4064.71 6373.08 ;
    END
    PORT
      LAYER Metal4 ;
        RECT 4073.14 37.065 4075.95 6373.08 ;
    END
    PORT
      LAYER Metal4 ;
        RECT 4084.38 37.065 4087.19 6373.08 ;
    END
    PORT
      LAYER Metal4 ;
        RECT 4095.62 37.065 4098.43 6373.08 ;
    END
    PORT
      LAYER Metal4 ;
        RECT 4106.86 37.065 4109.67 6373.08 ;
    END
    PORT
      LAYER Metal4 ;
        RECT 4118.1 37.065 4120.91 6373.08 ;
    END
    PORT
      LAYER Metal4 ;
        RECT 4129.34 37.065 4132.15 6373.08 ;
    END
    PORT
      LAYER Metal4 ;
        RECT 4140.58 37.065 4143.39 6373.08 ;
    END
    PORT
      LAYER Metal4 ;
        RECT 4151.82 37.065 4154.63 6373.08 ;
    END
    PORT
      LAYER Metal4 ;
        RECT 4163.06 37.065 4165.87 6373.08 ;
    END
    PORT
      LAYER Metal4 ;
        RECT 4174.3 37.065 4177.11 6373.08 ;
    END
    PORT
      LAYER Metal4 ;
        RECT 4185.54 37.065 4188.35 6373.08 ;
    END
    PORT
      LAYER Metal4 ;
        RECT 4196.78 37.065 4199.59 6373.08 ;
    END
    PORT
      LAYER Metal4 ;
        RECT 4208.02 37.065 4210.83 6373.08 ;
    END
    PORT
      LAYER Metal4 ;
        RECT 4219.26 37.065 4222.07 6373.08 ;
    END
    PORT
      LAYER Metal4 ;
        RECT 4230.5 37.065 4233.31 6373.08 ;
    END
    PORT
      LAYER Metal4 ;
        RECT 4241.74 37.065 4244.55 6373.08 ;
    END
    PORT
      LAYER Metal4 ;
        RECT 4252.98 37.065 4255.79 6373.08 ;
    END
    PORT
      LAYER Metal4 ;
        RECT 4264.22 37.065 4267.03 6373.08 ;
    END
    PORT
      LAYER Metal4 ;
        RECT 4275.46 37.065 4278.27 6373.08 ;
    END
    PORT
      LAYER Metal4 ;
        RECT 4286.7 37.065 4289.51 6373.08 ;
    END
    PORT
      LAYER Metal4 ;
        RECT 4297.94 37.065 4300.75 6373.08 ;
    END
    PORT
      LAYER Metal4 ;
        RECT 4309.18 37.065 4311.99 6373.08 ;
    END
    PORT
      LAYER Metal4 ;
        RECT 4320.42 37.065 4323.23 6373.08 ;
    END
    PORT
      LAYER Metal4 ;
        RECT 4331.66 37.065 4334.47 6373.08 ;
    END
    PORT
      LAYER Metal4 ;
        RECT 4342.9 37.065 4345.71 6373.08 ;
    END
    PORT
      LAYER Metal4 ;
        RECT 4354.14 37.065 4356.95 6373.08 ;
    END
    PORT
      LAYER Metal4 ;
        RECT 4365.38 37.065 4368.19 6373.08 ;
    END
    PORT
      LAYER Metal4 ;
        RECT 4376.62 37.065 4379.43 6373.08 ;
    END
    PORT
      LAYER Metal4 ;
        RECT 4387.86 37.065 4390.67 6373.08 ;
    END
    PORT
      LAYER Metal4 ;
        RECT 4399.1 37.065 4401.91 6373.08 ;
    END
    PORT
      LAYER Metal4 ;
        RECT 4410.34 37.065 4413.15 6373.08 ;
    END
    PORT
      LAYER Metal4 ;
        RECT 4421.58 37.065 4424.39 6373.08 ;
    END
    PORT
      LAYER Metal4 ;
        RECT 4432.82 37.065 4435.63 6373.08 ;
    END
    PORT
      LAYER Metal4 ;
        RECT 4444.06 37.065 4446.87 6373.08 ;
    END
    PORT
      LAYER Metal4 ;
        RECT 4455.3 37.065 4458.11 6373.08 ;
    END
    PORT
      LAYER Metal4 ;
        RECT 4466.54 37.065 4469.35 6373.08 ;
    END
    PORT
      LAYER Metal4 ;
        RECT 4477.78 37.065 4480.59 6373.08 ;
    END
    PORT
      LAYER Metal4 ;
        RECT 4489.02 37.065 4491.83 6373.08 ;
    END
    PORT
      LAYER Metal4 ;
        RECT 4500.26 37.065 4503.07 6373.08 ;
    END
    PORT
      LAYER Metal4 ;
        RECT 4511.5 37.065 4514.31 6373.08 ;
    END
    PORT
      LAYER Metal4 ;
        RECT 4522.74 37.065 4525.55 6373.08 ;
    END
    PORT
      LAYER Metal4 ;
        RECT 4533.98 37.065 4536.79 6373.08 ;
    END
    PORT
      LAYER Metal4 ;
        RECT 4545.22 37.065 4548.03 6373.08 ;
    END
    PORT
      LAYER Metal4 ;
        RECT 4556.46 37.065 4559.27 6373.08 ;
    END
    PORT
      LAYER Metal4 ;
        RECT 4567.7 37.065 4570.51 6373.08 ;
    END
    PORT
      LAYER Metal4 ;
        RECT 4578.94 37.065 4581.75 6373.08 ;
    END
    PORT
      LAYER Metal4 ;
        RECT 4590.18 37.065 4592.99 6373.08 ;
    END
    PORT
      LAYER Metal4 ;
        RECT 4601.42 37.065 4604.23 6373.08 ;
    END
    PORT
      LAYER Metal4 ;
        RECT 4612.66 37.065 4615.47 6373.08 ;
    END
    PORT
      LAYER Metal4 ;
        RECT 4623.9 37.065 4626.71 6373.08 ;
    END
    PORT
      LAYER Metal4 ;
        RECT 4635.14 37.065 4637.95 6373.08 ;
    END
    PORT
      LAYER Metal4 ;
        RECT 4646.38 37.065 4649.19 6373.08 ;
    END
    PORT
      LAYER Metal4 ;
        RECT 4657.62 37.065 4660.43 6373.08 ;
    END
    PORT
      LAYER Metal4 ;
        RECT 4668.86 37.065 4671.67 6373.08 ;
    END
    PORT
      LAYER Metal4 ;
        RECT 4680.1 37.065 4682.91 6373.08 ;
    END
    PORT
      LAYER Metal4 ;
        RECT 4691.34 37.065 4694.15 6373.08 ;
    END
    PORT
      LAYER Metal4 ;
        RECT 4702.58 37.065 4705.39 6373.08 ;
    END
    PORT
      LAYER Metal4 ;
        RECT 4713.82 37.065 4716.63 6373.08 ;
    END
    PORT
      LAYER Metal4 ;
        RECT 4725.06 37.065 4727.87 6373.08 ;
    END
    PORT
      LAYER Metal4 ;
        RECT 4736.3 37.065 4739.11 6373.08 ;
    END
    PORT
      LAYER Metal4 ;
        RECT 4747.54 37.065 4750.35 6373.08 ;
    END
    PORT
      LAYER Metal4 ;
        RECT 4758.78 37.065 4761.59 6373.08 ;
    END
    PORT
      LAYER Metal4 ;
        RECT 4770.02 37.065 4772.83 6373.08 ;
    END
    PORT
      LAYER Metal4 ;
        RECT 4781.26 37.065 4784.07 6373.08 ;
    END
    PORT
      LAYER Metal4 ;
        RECT 4792.5 37.065 4795.31 6373.08 ;
    END
    PORT
      LAYER Metal4 ;
        RECT 4803.74 37.065 4806.55 6373.08 ;
    END
    PORT
      LAYER Metal4 ;
        RECT 4814.98 37.065 4817.79 6373.08 ;
    END
    PORT
      LAYER Metal4 ;
        RECT 4826.22 37.065 4829.03 6373.08 ;
    END
    PORT
      LAYER Metal4 ;
        RECT 4837.46 37.065 4840.27 6373.08 ;
    END
    PORT
      LAYER Metal4 ;
        RECT 4848.7 37.065 4851.51 6373.08 ;
    END
    PORT
      LAYER Metal4 ;
        RECT 4859.94 37.065 4862.75 6373.08 ;
    END
    PORT
      LAYER Metal4 ;
        RECT 4871.18 37.065 4873.99 6373.08 ;
    END
    PORT
      LAYER Metal4 ;
        RECT 4882.42 37.065 4885.23 6373.08 ;
    END
    PORT
      LAYER Metal4 ;
        RECT 4893.66 37.065 4896.47 6373.08 ;
    END
    PORT
      LAYER Metal4 ;
        RECT 4904.9 37.065 4907.71 6373.08 ;
    END
    PORT
      LAYER Metal4 ;
        RECT 4916.14 37.065 4918.95 6373.08 ;
    END
    PORT
      LAYER Metal4 ;
        RECT 4927.38 37.065 4930.19 6373.08 ;
    END
    PORT
      LAYER Metal4 ;
        RECT 4938.62 37.065 4941.43 6373.08 ;
    END
    PORT
      LAYER Metal4 ;
        RECT 4949.86 37.065 4952.67 6373.08 ;
    END
    PORT
      LAYER Metal4 ;
        RECT 4961.1 37.065 4963.91 6373.08 ;
    END
    PORT
      LAYER Metal4 ;
        RECT 4972.34 37.065 4975.15 6373.08 ;
    END
    PORT
      LAYER Metal4 ;
        RECT 4983.58 37.065 4986.39 6373.08 ;
    END
    PORT
      LAYER Metal4 ;
        RECT 4994.82 37.065 4997.63 6373.08 ;
    END
    PORT
      LAYER Metal4 ;
        RECT 5006.06 37.065 5008.87 6373.08 ;
    END
    PORT
      LAYER Metal4 ;
        RECT 5017.3 37.065 5020.11 6373.08 ;
    END
    PORT
      LAYER Metal4 ;
        RECT 5028.54 37.065 5031.35 6373.08 ;
    END
    PORT
      LAYER Metal4 ;
        RECT 5039.78 37.065 5042.59 6373.08 ;
    END
    PORT
      LAYER Metal4 ;
        RECT 5051.02 37.065 5053.83 6373.08 ;
    END
    PORT
      LAYER Metal4 ;
        RECT 5062.26 37.065 5065.07 6373.08 ;
    END
    PORT
      LAYER Metal4 ;
        RECT 5073.5 37.065 5076.31 6373.08 ;
    END
    PORT
      LAYER Metal4 ;
        RECT 5084.74 37.065 5087.55 6373.08 ;
    END
    PORT
      LAYER Metal4 ;
        RECT 5095.98 37.065 5098.79 6373.08 ;
    END
    PORT
      LAYER Metal4 ;
        RECT 5107.22 37.065 5110.03 6373.08 ;
    END
    PORT
      LAYER Metal4 ;
        RECT 5118.46 37.065 5121.27 6373.08 ;
    END
    PORT
      LAYER Metal4 ;
        RECT 5129.7 37.065 5132.51 6373.08 ;
    END
    PORT
      LAYER Metal4 ;
        RECT 5140.94 37.065 5143.75 6373.08 ;
    END
    PORT
      LAYER Metal4 ;
        RECT 5152.18 37.065 5154.99 6373.08 ;
    END
    PORT
      LAYER Metal4 ;
        RECT 5163.42 37.065 5166.23 6373.08 ;
    END
    PORT
      LAYER Metal4 ;
        RECT 5174.66 37.065 5177.47 6373.08 ;
    END
    PORT
      LAYER Metal4 ;
        RECT 5185.9 37.065 5188.71 6373.08 ;
    END
    PORT
      LAYER Metal4 ;
        RECT 5197.14 37.065 5199.95 6373.08 ;
    END
    PORT
      LAYER Metal4 ;
        RECT 5208.38 37.065 5211.19 6373.08 ;
    END
    PORT
      LAYER Metal4 ;
        RECT 5219.62 37.065 5222.43 6373.08 ;
    END
    PORT
      LAYER Metal4 ;
        RECT 5230.86 37.065 5233.67 6373.08 ;
    END
    PORT
      LAYER Metal4 ;
        RECT 5242.1 37.065 5244.91 6373.08 ;
    END
    PORT
      LAYER Metal4 ;
        RECT 5253.34 37.065 5256.15 6373.08 ;
    END
    PORT
      LAYER Metal4 ;
        RECT 5264.58 37.065 5267.39 6373.08 ;
    END
    PORT
      LAYER Metal4 ;
        RECT 5275.82 37.065 5278.63 6373.08 ;
    END
    PORT
      LAYER Metal4 ;
        RECT 5287.06 37.065 5289.87 6373.08 ;
    END
    PORT
      LAYER Metal4 ;
        RECT 5298.3 37.065 5301.11 6373.08 ;
    END
    PORT
      LAYER Metal4 ;
        RECT 5309.54 37.065 5312.35 6373.08 ;
    END
    PORT
      LAYER Metal4 ;
        RECT 5320.78 37.065 5323.59 6373.08 ;
    END
    PORT
      LAYER Metal4 ;
        RECT 5332.02 37.065 5334.83 6373.08 ;
    END
    PORT
      LAYER Metal4 ;
        RECT 5343.26 37.065 5346.07 6373.08 ;
    END
    PORT
      LAYER Metal4 ;
        RECT 5354.5 37.065 5357.31 6373.08 ;
    END
    PORT
      LAYER Metal4 ;
        RECT 5365.74 37.065 5368.55 6373.08 ;
    END
    PORT
      LAYER Metal4 ;
        RECT 5376.98 37.065 5379.79 6373.08 ;
    END
    PORT
      LAYER Metal4 ;
        RECT 5388.22 37.065 5391.03 6373.08 ;
    END
    PORT
      LAYER Metal4 ;
        RECT 5399.46 37.065 5402.27 6373.08 ;
    END
    PORT
      LAYER Metal4 ;
        RECT 5410.7 37.065 5413.51 6373.08 ;
    END
    PORT
      LAYER Metal4 ;
        RECT 5421.94 37.065 5424.75 6373.08 ;
    END
    PORT
      LAYER Metal4 ;
        RECT 5433.18 37.065 5435.99 6373.08 ;
    END
    PORT
      LAYER Metal4 ;
        RECT 5444.42 37.065 5447.23 6373.08 ;
    END
    PORT
      LAYER Metal4 ;
        RECT 5455.66 37.065 5458.47 6373.08 ;
    END
    PORT
      LAYER Metal4 ;
        RECT 5466.9 37.065 5469.71 6373.08 ;
    END
    PORT
      LAYER Metal4 ;
        RECT 5478.14 37.065 5480.95 6373.08 ;
    END
    PORT
      LAYER Metal4 ;
        RECT 5489.38 37.065 5492.19 6373.08 ;
    END
    PORT
      LAYER Metal4 ;
        RECT 5500.62 37.065 5503.43 6373.08 ;
    END
    PORT
      LAYER Metal4 ;
        RECT 5511.86 37.065 5514.67 6373.08 ;
    END
    PORT
      LAYER Metal4 ;
        RECT 5523.1 37.065 5525.91 6373.08 ;
    END
    PORT
      LAYER Metal4 ;
        RECT 5534.34 37.065 5537.15 6373.08 ;
    END
    PORT
      LAYER Metal4 ;
        RECT 5545.58 37.065 5548.39 6373.08 ;
    END
    PORT
      LAYER Metal4 ;
        RECT 5556.82 37.065 5559.63 6373.08 ;
    END
    PORT
      LAYER Metal4 ;
        RECT 5568.06 37.065 5570.87 6373.08 ;
    END
    PORT
      LAYER Metal4 ;
        RECT 5579.3 37.065 5582.11 6373.08 ;
    END
    PORT
      LAYER Metal4 ;
        RECT 5590.54 37.065 5593.35 6373.08 ;
    END
    PORT
      LAYER Metal4 ;
        RECT 5601.78 37.065 5604.59 6373.08 ;
    END
    PORT
      LAYER Metal4 ;
        RECT 5613.02 37.065 5615.83 6373.08 ;
    END
    PORT
      LAYER Metal4 ;
        RECT 5624.26 37.065 5627.07 6373.08 ;
    END
    PORT
      LAYER Metal4 ;
        RECT 5635.5 37.065 5638.31 6373.08 ;
    END
    PORT
      LAYER Metal4 ;
        RECT 5646.74 37.065 5649.55 6373.08 ;
    END
    PORT
      LAYER Metal4 ;
        RECT 5657.98 37.065 5660.79 6373.08 ;
    END
    PORT
      LAYER Metal4 ;
        RECT 5669.22 37.065 5672.03 6373.08 ;
    END
    PORT
      LAYER Metal4 ;
        RECT 5680.46 37.065 5683.27 6373.08 ;
    END
    PORT
      LAYER Metal4 ;
        RECT 5691.7 37.065 5694.51 6373.08 ;
    END
    PORT
      LAYER Metal4 ;
        RECT 5702.94 37.065 5705.75 6373.08 ;
    END
    PORT
      LAYER Metal4 ;
        RECT 5714.18 37.065 5716.99 6373.08 ;
    END
    PORT
      LAYER Metal4 ;
        RECT 5725.42 37.065 5728.23 6373.08 ;
    END
    PORT
      LAYER Metal4 ;
        RECT 5736.66 37.065 5739.47 6373.08 ;
    END
    PORT
      LAYER Metal4 ;
        RECT 5747.9 37.065 5750.71 6373.08 ;
    END
    PORT
      LAYER Metal4 ;
        RECT 5759.14 37.065 5761.95 6373.08 ;
    END
    PORT
      LAYER Metal4 ;
        RECT 5770.38 37.065 5773.19 6373.08 ;
    END
    PORT
      LAYER Metal4 ;
        RECT 5781.62 37.065 5784.43 6373.08 ;
    END
    PORT
      LAYER Metal4 ;
        RECT 5792.86 37.065 5795.67 6373.08 ;
    END
    PORT
      LAYER Metal4 ;
        RECT 5804.1 37.065 5806.91 6373.08 ;
    END
    PORT
      LAYER Metal4 ;
        RECT 5815.34 37.065 5818.15 6373.08 ;
    END
    PORT
      LAYER Metal4 ;
        RECT 5826.58 37.065 5829.39 6373.08 ;
    END
    PORT
      LAYER Metal4 ;
        RECT 5837.82 37.065 5840.63 6373.08 ;
    END
    PORT
      LAYER Metal4 ;
        RECT 5849.06 37.065 5851.87 6373.08 ;
    END
    PORT
      LAYER Metal4 ;
        RECT 5860.3 37.065 5863.11 6373.08 ;
    END
    PORT
      LAYER Metal4 ;
        RECT 5871.54 37.065 5874.35 6373.08 ;
    END
    PORT
      LAYER Metal4 ;
        RECT 5882.78 37.065 5885.59 6373.08 ;
    END
    PORT
      LAYER Metal4 ;
        RECT 5894.02 37.065 5896.83 6373.08 ;
    END
    PORT
      LAYER Metal4 ;
        RECT 5905.26 37.065 5908.07 6373.08 ;
    END
    PORT
      LAYER Metal4 ;
        RECT 5916.5 37.065 5919.31 6373.08 ;
    END
    PORT
      LAYER Metal4 ;
        RECT 5927.74 37.065 5930.55 6373.08 ;
    END
    PORT
      LAYER Metal4 ;
        RECT 5938.98 37.065 5941.79 6373.08 ;
    END
    PORT
      LAYER Metal4 ;
        RECT 5950.22 37.065 5953.03 6373.08 ;
    END
    PORT
      LAYER Metal4 ;
        RECT 5961.46 37.065 5964.27 6373.08 ;
    END
    PORT
      LAYER Metal4 ;
        RECT 5972.7 37.065 5975.51 6373.08 ;
    END
    PORT
      LAYER Metal4 ;
        RECT 5983.94 37.065 5986.75 6373.08 ;
    END
    PORT
      LAYER Metal4 ;
        RECT 5995.18 37.065 5997.99 6373.08 ;
    END
    PORT
      LAYER Metal4 ;
        RECT 6006.42 37.065 6009.23 6373.08 ;
    END
    PORT
      LAYER Metal4 ;
        RECT 6017.66 37.065 6020.47 6373.08 ;
    END
    PORT
      LAYER Metal4 ;
        RECT 6028.9 37.065 6031.71 6373.08 ;
    END
    PORT
      LAYER Metal4 ;
        RECT 6040.14 37.065 6042.95 6373.08 ;
    END
    PORT
      LAYER Metal4 ;
        RECT 6051.38 37.065 6054.19 6373.08 ;
    END
    PORT
      LAYER Metal4 ;
        RECT 6062.62 37.065 6065.43 6373.08 ;
    END
    PORT
      LAYER Metal4 ;
        RECT 6073.86 37.065 6076.67 6373.08 ;
    END
    PORT
      LAYER Metal4 ;
        RECT 6085.1 37.065 6087.91 6373.08 ;
    END
    PORT
      LAYER Metal4 ;
        RECT 6096.34 37.065 6099.15 6373.08 ;
    END
    PORT
      LAYER Metal4 ;
        RECT 6107.58 37.065 6110.39 6373.08 ;
    END
    PORT
      LAYER Metal4 ;
        RECT 6118.82 37.065 6121.63 6373.08 ;
    END
    PORT
      LAYER Metal4 ;
        RECT 6130.06 37.065 6132.87 6373.08 ;
    END
    PORT
      LAYER Metal4 ;
        RECT 6141.3 37.065 6144.11 6373.08 ;
    END
    PORT
      LAYER Metal4 ;
        RECT 6152.54 37.065 6155.35 6373.08 ;
    END
    PORT
      LAYER Metal4 ;
        RECT 6163.78 37.065 6166.59 6373.08 ;
    END
    PORT
      LAYER Metal4 ;
        RECT 6175.02 37.065 6177.83 6373.08 ;
    END
    PORT
      LAYER Metal4 ;
        RECT 6186.26 37.065 6189.07 6373.08 ;
    END
    PORT
      LAYER Metal4 ;
        RECT 6197.5 37.065 6200.31 6373.08 ;
    END
    PORT
      LAYER Metal4 ;
        RECT 6208.74 37.065 6211.55 6373.08 ;
    END
    PORT
      LAYER Metal4 ;
        RECT 6219.98 37.065 6222.79 6373.08 ;
    END
    PORT
      LAYER Metal4 ;
        RECT 6231.22 37.065 6234.03 6373.08 ;
    END
    PORT
      LAYER Metal4 ;
        RECT 6242.46 37.065 6245.27 6373.08 ;
    END
    PORT
      LAYER Metal4 ;
        RECT 6253.7 37.065 6256.51 6373.08 ;
    END
    PORT
      LAYER Metal4 ;
        RECT 6264.94 37.065 6267.75 6373.08 ;
    END
    PORT
      LAYER Metal4 ;
        RECT 6276.18 37.065 6278.99 6373.08 ;
    END
    PORT
      LAYER Metal4 ;
        RECT 6287.42 37.065 6290.23 6373.08 ;
    END
    PORT
      LAYER Metal4 ;
        RECT 6298.66 37.065 6301.47 6373.08 ;
    END
    PORT
      LAYER Metal4 ;
        RECT 6309.9 37.065 6312.71 6373.08 ;
    END
    PORT
      LAYER Metal4 ;
        RECT 6321.14 37.065 6323.95 6373.08 ;
    END
    PORT
      LAYER Metal4 ;
        RECT 6332.38 37.065 6335.19 6373.08 ;
    END
    PORT
      LAYER Metal4 ;
        RECT 6343.62 37.065 6346.43 6373.08 ;
    END
  END VDDARRAY
  PIN VSS
    DIRECTION INOUT ;
    USE GROUND ;
    PORT
      LAYER Metal4 ;
        RECT 21.12 0 23.93 6373.08 ;
    END
    PORT
      LAYER Metal4 ;
        RECT 32.36 0 35.17 6373.08 ;
    END
    PORT
      LAYER Metal4 ;
        RECT 43.6 0 46.41 6373.08 ;
    END
    PORT
      LAYER Metal4 ;
        RECT 54.84 0 57.65 6373.08 ;
    END
    PORT
      LAYER Metal4 ;
        RECT 66.08 0 68.89 6373.08 ;
    END
    PORT
      LAYER Metal4 ;
        RECT 77.32 0 80.13 6373.08 ;
    END
    PORT
      LAYER Metal4 ;
        RECT 88.56 0 91.37 6373.08 ;
    END
    PORT
      LAYER Metal4 ;
        RECT 99.8 0 102.61 6373.08 ;
    END
    PORT
      LAYER Metal4 ;
        RECT 111.04 0 113.85 6373.08 ;
    END
    PORT
      LAYER Metal4 ;
        RECT 122.28 0 125.09 6373.08 ;
    END
    PORT
      LAYER Metal4 ;
        RECT 133.52 0 136.33 6373.08 ;
    END
    PORT
      LAYER Metal4 ;
        RECT 144.76 0 147.57 6373.08 ;
    END
    PORT
      LAYER Metal4 ;
        RECT 156 0 158.81 6373.08 ;
    END
    PORT
      LAYER Metal4 ;
        RECT 167.24 0 170.05 6373.08 ;
    END
    PORT
      LAYER Metal4 ;
        RECT 178.48 0 181.29 6373.08 ;
    END
    PORT
      LAYER Metal4 ;
        RECT 189.72 0 192.53 6373.08 ;
    END
    PORT
      LAYER Metal4 ;
        RECT 200.96 0 203.77 6373.08 ;
    END
    PORT
      LAYER Metal4 ;
        RECT 212.2 0 215.01 6373.08 ;
    END
    PORT
      LAYER Metal4 ;
        RECT 223.44 0 226.25 6373.08 ;
    END
    PORT
      LAYER Metal4 ;
        RECT 234.68 0 237.49 6373.08 ;
    END
    PORT
      LAYER Metal4 ;
        RECT 245.92 0 248.73 6373.08 ;
    END
    PORT
      LAYER Metal4 ;
        RECT 257.16 0 259.97 6373.08 ;
    END
    PORT
      LAYER Metal4 ;
        RECT 268.4 0 271.21 6373.08 ;
    END
    PORT
      LAYER Metal4 ;
        RECT 279.64 0 282.45 6373.08 ;
    END
    PORT
      LAYER Metal4 ;
        RECT 290.88 0 293.69 6373.08 ;
    END
    PORT
      LAYER Metal4 ;
        RECT 302.12 0 304.93 6373.08 ;
    END
    PORT
      LAYER Metal4 ;
        RECT 313.36 0 316.17 6373.08 ;
    END
    PORT
      LAYER Metal4 ;
        RECT 324.6 0 327.41 6373.08 ;
    END
    PORT
      LAYER Metal4 ;
        RECT 335.84 0 338.65 6373.08 ;
    END
    PORT
      LAYER Metal4 ;
        RECT 347.08 0 349.89 6373.08 ;
    END
    PORT
      LAYER Metal4 ;
        RECT 358.32 0 361.13 6373.08 ;
    END
    PORT
      LAYER Metal4 ;
        RECT 369.56 0 372.37 6373.08 ;
    END
    PORT
      LAYER Metal4 ;
        RECT 380.8 0 383.61 6373.08 ;
    END
    PORT
      LAYER Metal4 ;
        RECT 392.04 0 394.85 6373.08 ;
    END
    PORT
      LAYER Metal4 ;
        RECT 403.28 0 406.09 6373.08 ;
    END
    PORT
      LAYER Metal4 ;
        RECT 414.52 0 417.33 6373.08 ;
    END
    PORT
      LAYER Metal4 ;
        RECT 425.76 0 428.57 6373.08 ;
    END
    PORT
      LAYER Metal4 ;
        RECT 437 0 439.81 6373.08 ;
    END
    PORT
      LAYER Metal4 ;
        RECT 448.24 0 451.05 6373.08 ;
    END
    PORT
      LAYER Metal4 ;
        RECT 459.48 0 462.29 6373.08 ;
    END
    PORT
      LAYER Metal4 ;
        RECT 470.72 0 473.53 6373.08 ;
    END
    PORT
      LAYER Metal4 ;
        RECT 481.96 0 484.77 6373.08 ;
    END
    PORT
      LAYER Metal4 ;
        RECT 493.2 0 496.01 6373.08 ;
    END
    PORT
      LAYER Metal4 ;
        RECT 504.44 0 507.25 6373.08 ;
    END
    PORT
      LAYER Metal4 ;
        RECT 515.68 0 518.49 6373.08 ;
    END
    PORT
      LAYER Metal4 ;
        RECT 526.92 0 529.73 6373.08 ;
    END
    PORT
      LAYER Metal4 ;
        RECT 538.16 0 540.97 6373.08 ;
    END
    PORT
      LAYER Metal4 ;
        RECT 549.4 0 552.21 6373.08 ;
    END
    PORT
      LAYER Metal4 ;
        RECT 560.64 0 563.45 6373.08 ;
    END
    PORT
      LAYER Metal4 ;
        RECT 571.88 0 574.69 6373.08 ;
    END
    PORT
      LAYER Metal4 ;
        RECT 583.12 0 585.93 6373.08 ;
    END
    PORT
      LAYER Metal4 ;
        RECT 594.36 0 597.17 6373.08 ;
    END
    PORT
      LAYER Metal4 ;
        RECT 605.6 0 608.41 6373.08 ;
    END
    PORT
      LAYER Metal4 ;
        RECT 616.84 0 619.65 6373.08 ;
    END
    PORT
      LAYER Metal4 ;
        RECT 628.08 0 630.89 6373.08 ;
    END
    PORT
      LAYER Metal4 ;
        RECT 639.32 0 642.13 6373.08 ;
    END
    PORT
      LAYER Metal4 ;
        RECT 650.56 0 653.37 6373.08 ;
    END
    PORT
      LAYER Metal4 ;
        RECT 661.8 0 664.61 6373.08 ;
    END
    PORT
      LAYER Metal4 ;
        RECT 673.04 0 675.85 6373.08 ;
    END
    PORT
      LAYER Metal4 ;
        RECT 684.28 0 687.09 6373.08 ;
    END
    PORT
      LAYER Metal4 ;
        RECT 695.52 0 698.33 6373.08 ;
    END
    PORT
      LAYER Metal4 ;
        RECT 706.76 0 709.57 6373.08 ;
    END
    PORT
      LAYER Metal4 ;
        RECT 718 0 720.81 6373.08 ;
    END
    PORT
      LAYER Metal4 ;
        RECT 729.24 0 732.05 6373.08 ;
    END
    PORT
      LAYER Metal4 ;
        RECT 740.48 0 743.29 6373.08 ;
    END
    PORT
      LAYER Metal4 ;
        RECT 751.72 0 754.53 6373.08 ;
    END
    PORT
      LAYER Metal4 ;
        RECT 762.96 0 765.77 6373.08 ;
    END
    PORT
      LAYER Metal4 ;
        RECT 774.2 0 777.01 6373.08 ;
    END
    PORT
      LAYER Metal4 ;
        RECT 785.44 0 788.25 6373.08 ;
    END
    PORT
      LAYER Metal4 ;
        RECT 796.68 0 799.49 6373.08 ;
    END
    PORT
      LAYER Metal4 ;
        RECT 807.92 0 810.73 6373.08 ;
    END
    PORT
      LAYER Metal4 ;
        RECT 819.16 0 821.97 6373.08 ;
    END
    PORT
      LAYER Metal4 ;
        RECT 830.4 0 833.21 6373.08 ;
    END
    PORT
      LAYER Metal4 ;
        RECT 841.64 0 844.45 6373.08 ;
    END
    PORT
      LAYER Metal4 ;
        RECT 852.88 0 855.69 6373.08 ;
    END
    PORT
      LAYER Metal4 ;
        RECT 864.12 0 866.93 6373.08 ;
    END
    PORT
      LAYER Metal4 ;
        RECT 875.36 0 878.17 6373.08 ;
    END
    PORT
      LAYER Metal4 ;
        RECT 886.6 0 889.41 6373.08 ;
    END
    PORT
      LAYER Metal4 ;
        RECT 897.84 0 900.65 6373.08 ;
    END
    PORT
      LAYER Metal4 ;
        RECT 909.08 0 911.89 6373.08 ;
    END
    PORT
      LAYER Metal4 ;
        RECT 920.32 0 923.13 6373.08 ;
    END
    PORT
      LAYER Metal4 ;
        RECT 931.56 0 934.37 6373.08 ;
    END
    PORT
      LAYER Metal4 ;
        RECT 942.8 0 945.61 6373.08 ;
    END
    PORT
      LAYER Metal4 ;
        RECT 954.04 0 956.85 6373.08 ;
    END
    PORT
      LAYER Metal4 ;
        RECT 965.28 0 968.09 6373.08 ;
    END
    PORT
      LAYER Metal4 ;
        RECT 976.52 0 979.33 6373.08 ;
    END
    PORT
      LAYER Metal4 ;
        RECT 987.76 0 990.57 6373.08 ;
    END
    PORT
      LAYER Metal4 ;
        RECT 999 0 1001.81 6373.08 ;
    END
    PORT
      LAYER Metal4 ;
        RECT 1010.24 0 1013.05 6373.08 ;
    END
    PORT
      LAYER Metal4 ;
        RECT 1021.48 0 1024.29 6373.08 ;
    END
    PORT
      LAYER Metal4 ;
        RECT 1032.72 0 1035.53 6373.08 ;
    END
    PORT
      LAYER Metal4 ;
        RECT 1043.96 0 1046.77 6373.08 ;
    END
    PORT
      LAYER Metal4 ;
        RECT 1055.2 0 1058.01 6373.08 ;
    END
    PORT
      LAYER Metal4 ;
        RECT 1066.44 0 1069.25 6373.08 ;
    END
    PORT
      LAYER Metal4 ;
        RECT 1077.68 0 1080.49 6373.08 ;
    END
    PORT
      LAYER Metal4 ;
        RECT 1088.92 0 1091.73 6373.08 ;
    END
    PORT
      LAYER Metal4 ;
        RECT 1100.16 0 1102.97 6373.08 ;
    END
    PORT
      LAYER Metal4 ;
        RECT 1111.4 0 1114.21 6373.08 ;
    END
    PORT
      LAYER Metal4 ;
        RECT 1122.64 0 1125.45 6373.08 ;
    END
    PORT
      LAYER Metal4 ;
        RECT 1133.88 0 1136.69 6373.08 ;
    END
    PORT
      LAYER Metal4 ;
        RECT 1145.12 0 1147.93 6373.08 ;
    END
    PORT
      LAYER Metal4 ;
        RECT 1156.36 0 1159.17 6373.08 ;
    END
    PORT
      LAYER Metal4 ;
        RECT 1167.6 0 1170.41 6373.08 ;
    END
    PORT
      LAYER Metal4 ;
        RECT 1178.84 0 1181.65 6373.08 ;
    END
    PORT
      LAYER Metal4 ;
        RECT 1190.08 0 1192.89 6373.08 ;
    END
    PORT
      LAYER Metal4 ;
        RECT 1201.32 0 1204.13 6373.08 ;
    END
    PORT
      LAYER Metal4 ;
        RECT 1212.56 0 1215.37 6373.08 ;
    END
    PORT
      LAYER Metal4 ;
        RECT 1223.8 0 1226.61 6373.08 ;
    END
    PORT
      LAYER Metal4 ;
        RECT 1235.04 0 1237.85 6373.08 ;
    END
    PORT
      LAYER Metal4 ;
        RECT 1246.28 0 1249.09 6373.08 ;
    END
    PORT
      LAYER Metal4 ;
        RECT 1257.52 0 1260.33 6373.08 ;
    END
    PORT
      LAYER Metal4 ;
        RECT 1268.76 0 1271.57 6373.08 ;
    END
    PORT
      LAYER Metal4 ;
        RECT 1280 0 1282.81 6373.08 ;
    END
    PORT
      LAYER Metal4 ;
        RECT 1291.24 0 1294.05 6373.08 ;
    END
    PORT
      LAYER Metal4 ;
        RECT 1302.48 0 1305.29 6373.08 ;
    END
    PORT
      LAYER Metal4 ;
        RECT 1313.72 0 1316.53 6373.08 ;
    END
    PORT
      LAYER Metal4 ;
        RECT 1324.96 0 1327.77 6373.08 ;
    END
    PORT
      LAYER Metal4 ;
        RECT 1336.2 0 1339.01 6373.08 ;
    END
    PORT
      LAYER Metal4 ;
        RECT 1347.44 0 1350.25 6373.08 ;
    END
    PORT
      LAYER Metal4 ;
        RECT 1358.68 0 1361.49 6373.08 ;
    END
    PORT
      LAYER Metal4 ;
        RECT 1369.92 0 1372.73 6373.08 ;
    END
    PORT
      LAYER Metal4 ;
        RECT 1381.16 0 1383.97 6373.08 ;
    END
    PORT
      LAYER Metal4 ;
        RECT 1392.4 0 1395.21 6373.08 ;
    END
    PORT
      LAYER Metal4 ;
        RECT 1403.64 0 1406.45 6373.08 ;
    END
    PORT
      LAYER Metal4 ;
        RECT 1414.88 0 1417.69 6373.08 ;
    END
    PORT
      LAYER Metal4 ;
        RECT 1426.12 0 1428.93 6373.08 ;
    END
    PORT
      LAYER Metal4 ;
        RECT 1437.36 0 1440.17 6373.08 ;
    END
    PORT
      LAYER Metal4 ;
        RECT 1448.6 0 1451.41 6373.08 ;
    END
    PORT
      LAYER Metal4 ;
        RECT 1459.84 0 1462.65 6373.08 ;
    END
    PORT
      LAYER Metal4 ;
        RECT 1471.08 0 1473.89 6373.08 ;
    END
    PORT
      LAYER Metal4 ;
        RECT 1482.32 0 1485.13 6373.08 ;
    END
    PORT
      LAYER Metal4 ;
        RECT 1493.56 0 1496.37 6373.08 ;
    END
    PORT
      LAYER Metal4 ;
        RECT 1504.8 0 1507.61 6373.08 ;
    END
    PORT
      LAYER Metal4 ;
        RECT 1516.04 0 1518.85 6373.08 ;
    END
    PORT
      LAYER Metal4 ;
        RECT 1527.28 0 1530.09 6373.08 ;
    END
    PORT
      LAYER Metal4 ;
        RECT 1538.52 0 1541.33 6373.08 ;
    END
    PORT
      LAYER Metal4 ;
        RECT 1549.76 0 1552.57 6373.08 ;
    END
    PORT
      LAYER Metal4 ;
        RECT 1561 0 1563.81 6373.08 ;
    END
    PORT
      LAYER Metal4 ;
        RECT 1572.24 0 1575.05 6373.08 ;
    END
    PORT
      LAYER Metal4 ;
        RECT 1583.48 0 1586.29 6373.08 ;
    END
    PORT
      LAYER Metal4 ;
        RECT 1594.72 0 1597.53 6373.08 ;
    END
    PORT
      LAYER Metal4 ;
        RECT 1605.96 0 1608.77 6373.08 ;
    END
    PORT
      LAYER Metal4 ;
        RECT 1617.2 0 1620.01 6373.08 ;
    END
    PORT
      LAYER Metal4 ;
        RECT 1628.44 0 1631.25 6373.08 ;
    END
    PORT
      LAYER Metal4 ;
        RECT 1639.68 0 1642.49 6373.08 ;
    END
    PORT
      LAYER Metal4 ;
        RECT 1650.92 0 1653.73 6373.08 ;
    END
    PORT
      LAYER Metal4 ;
        RECT 1662.16 0 1664.97 6373.08 ;
    END
    PORT
      LAYER Metal4 ;
        RECT 1673.4 0 1676.21 6373.08 ;
    END
    PORT
      LAYER Metal4 ;
        RECT 1684.64 0 1687.45 6373.08 ;
    END
    PORT
      LAYER Metal4 ;
        RECT 1695.88 0 1698.69 6373.08 ;
    END
    PORT
      LAYER Metal4 ;
        RECT 1707.12 0 1709.93 6373.08 ;
    END
    PORT
      LAYER Metal4 ;
        RECT 1718.36 0 1721.17 6373.08 ;
    END
    PORT
      LAYER Metal4 ;
        RECT 1729.6 0 1732.41 6373.08 ;
    END
    PORT
      LAYER Metal4 ;
        RECT 1740.84 0 1743.65 6373.08 ;
    END
    PORT
      LAYER Metal4 ;
        RECT 1752.08 0 1754.89 6373.08 ;
    END
    PORT
      LAYER Metal4 ;
        RECT 1763.32 0 1766.13 6373.08 ;
    END
    PORT
      LAYER Metal4 ;
        RECT 1774.56 0 1777.37 6373.08 ;
    END
    PORT
      LAYER Metal4 ;
        RECT 1785.8 0 1788.61 6373.08 ;
    END
    PORT
      LAYER Metal4 ;
        RECT 1797.04 0 1799.85 6373.08 ;
    END
    PORT
      LAYER Metal4 ;
        RECT 1808.28 0 1811.09 6373.08 ;
    END
    PORT
      LAYER Metal4 ;
        RECT 1819.52 0 1822.33 6373.08 ;
    END
    PORT
      LAYER Metal4 ;
        RECT 1830.76 0 1833.57 6373.08 ;
    END
    PORT
      LAYER Metal4 ;
        RECT 1842 0 1844.81 6373.08 ;
    END
    PORT
      LAYER Metal4 ;
        RECT 1853.24 0 1856.05 6373.08 ;
    END
    PORT
      LAYER Metal4 ;
        RECT 1864.48 0 1867.29 6373.08 ;
    END
    PORT
      LAYER Metal4 ;
        RECT 1875.72 0 1878.53 6373.08 ;
    END
    PORT
      LAYER Metal4 ;
        RECT 1886.96 0 1889.77 6373.08 ;
    END
    PORT
      LAYER Metal4 ;
        RECT 1898.2 0 1901.01 6373.08 ;
    END
    PORT
      LAYER Metal4 ;
        RECT 1909.44 0 1912.25 6373.08 ;
    END
    PORT
      LAYER Metal4 ;
        RECT 1920.68 0 1923.49 6373.08 ;
    END
    PORT
      LAYER Metal4 ;
        RECT 1931.92 0 1934.73 6373.08 ;
    END
    PORT
      LAYER Metal4 ;
        RECT 1943.16 0 1945.97 6373.08 ;
    END
    PORT
      LAYER Metal4 ;
        RECT 1954.4 0 1957.21 6373.08 ;
    END
    PORT
      LAYER Metal4 ;
        RECT 1965.64 0 1968.45 6373.08 ;
    END
    PORT
      LAYER Metal4 ;
        RECT 1976.88 0 1979.69 6373.08 ;
    END
    PORT
      LAYER Metal4 ;
        RECT 1988.12 0 1990.93 6373.08 ;
    END
    PORT
      LAYER Metal4 ;
        RECT 1999.36 0 2002.17 6373.08 ;
    END
    PORT
      LAYER Metal4 ;
        RECT 2010.6 0 2013.41 6373.08 ;
    END
    PORT
      LAYER Metal4 ;
        RECT 2021.84 0 2024.65 6373.08 ;
    END
    PORT
      LAYER Metal4 ;
        RECT 2033.08 0 2035.89 6373.08 ;
    END
    PORT
      LAYER Metal4 ;
        RECT 2044.32 0 2047.13 6373.08 ;
    END
    PORT
      LAYER Metal4 ;
        RECT 2055.56 0 2058.37 6373.08 ;
    END
    PORT
      LAYER Metal4 ;
        RECT 2066.8 0 2069.61 6373.08 ;
    END
    PORT
      LAYER Metal4 ;
        RECT 2078.04 0 2080.85 6373.08 ;
    END
    PORT
      LAYER Metal4 ;
        RECT 2089.28 0 2092.09 6373.08 ;
    END
    PORT
      LAYER Metal4 ;
        RECT 2100.52 0 2103.33 6373.08 ;
    END
    PORT
      LAYER Metal4 ;
        RECT 2111.76 0 2114.57 6373.08 ;
    END
    PORT
      LAYER Metal4 ;
        RECT 2123 0 2125.81 6373.08 ;
    END
    PORT
      LAYER Metal4 ;
        RECT 2134.24 0 2137.05 6373.08 ;
    END
    PORT
      LAYER Metal4 ;
        RECT 2145.48 0 2148.29 6373.08 ;
    END
    PORT
      LAYER Metal4 ;
        RECT 2156.72 0 2159.53 6373.08 ;
    END
    PORT
      LAYER Metal4 ;
        RECT 2167.96 0 2170.77 6373.08 ;
    END
    PORT
      LAYER Metal4 ;
        RECT 2179.2 0 2182.01 6373.08 ;
    END
    PORT
      LAYER Metal4 ;
        RECT 2190.44 0 2193.25 6373.08 ;
    END
    PORT
      LAYER Metal4 ;
        RECT 2201.68 0 2204.49 6373.08 ;
    END
    PORT
      LAYER Metal4 ;
        RECT 2212.92 0 2215.73 6373.08 ;
    END
    PORT
      LAYER Metal4 ;
        RECT 2224.16 0 2226.97 6373.08 ;
    END
    PORT
      LAYER Metal4 ;
        RECT 2235.4 0 2238.21 6373.08 ;
    END
    PORT
      LAYER Metal4 ;
        RECT 2246.64 0 2249.45 6373.08 ;
    END
    PORT
      LAYER Metal4 ;
        RECT 2257.88 0 2260.69 6373.08 ;
    END
    PORT
      LAYER Metal4 ;
        RECT 2269.12 0 2271.93 6373.08 ;
    END
    PORT
      LAYER Metal4 ;
        RECT 2280.36 0 2283.17 6373.08 ;
    END
    PORT
      LAYER Metal4 ;
        RECT 2291.6 0 2294.41 6373.08 ;
    END
    PORT
      LAYER Metal4 ;
        RECT 2302.84 0 2305.65 6373.08 ;
    END
    PORT
      LAYER Metal4 ;
        RECT 2314.08 0 2316.89 6373.08 ;
    END
    PORT
      LAYER Metal4 ;
        RECT 2325.32 0 2328.13 6373.08 ;
    END
    PORT
      LAYER Metal4 ;
        RECT 2336.56 0 2339.37 6373.08 ;
    END
    PORT
      LAYER Metal4 ;
        RECT 2347.8 0 2350.61 6373.08 ;
    END
    PORT
      LAYER Metal4 ;
        RECT 2359.04 0 2361.85 6373.08 ;
    END
    PORT
      LAYER Metal4 ;
        RECT 2370.28 0 2373.09 6373.08 ;
    END
    PORT
      LAYER Metal4 ;
        RECT 2381.52 0 2384.33 6373.08 ;
    END
    PORT
      LAYER Metal4 ;
        RECT 2392.76 0 2395.57 6373.08 ;
    END
    PORT
      LAYER Metal4 ;
        RECT 2404 0 2406.81 6373.08 ;
    END
    PORT
      LAYER Metal4 ;
        RECT 2415.24 0 2418.05 6373.08 ;
    END
    PORT
      LAYER Metal4 ;
        RECT 2426.48 0 2429.29 6373.08 ;
    END
    PORT
      LAYER Metal4 ;
        RECT 2437.72 0 2440.53 6373.08 ;
    END
    PORT
      LAYER Metal4 ;
        RECT 2448.96 0 2451.77 6373.08 ;
    END
    PORT
      LAYER Metal4 ;
        RECT 2460.2 0 2463.01 6373.08 ;
    END
    PORT
      LAYER Metal4 ;
        RECT 2471.44 0 2474.25 6373.08 ;
    END
    PORT
      LAYER Metal4 ;
        RECT 2482.68 0 2485.49 6373.08 ;
    END
    PORT
      LAYER Metal4 ;
        RECT 2493.92 0 2496.73 6373.08 ;
    END
    PORT
      LAYER Metal4 ;
        RECT 2505.16 0 2507.97 6373.08 ;
    END
    PORT
      LAYER Metal4 ;
        RECT 2516.4 0 2519.21 6373.08 ;
    END
    PORT
      LAYER Metal4 ;
        RECT 2527.64 0 2530.45 6373.08 ;
    END
    PORT
      LAYER Metal4 ;
        RECT 2538.88 0 2541.69 6373.08 ;
    END
    PORT
      LAYER Metal4 ;
        RECT 2550.12 0 2552.93 6373.08 ;
    END
    PORT
      LAYER Metal4 ;
        RECT 2561.36 0 2564.17 6373.08 ;
    END
    PORT
      LAYER Metal4 ;
        RECT 2572.6 0 2575.41 6373.08 ;
    END
    PORT
      LAYER Metal4 ;
        RECT 2583.84 0 2586.65 6373.08 ;
    END
    PORT
      LAYER Metal4 ;
        RECT 2595.08 0 2597.89 6373.08 ;
    END
    PORT
      LAYER Metal4 ;
        RECT 2606.32 0 2609.13 6373.08 ;
    END
    PORT
      LAYER Metal4 ;
        RECT 2617.56 0 2620.37 6373.08 ;
    END
    PORT
      LAYER Metal4 ;
        RECT 2628.8 0 2631.61 6373.08 ;
    END
    PORT
      LAYER Metal4 ;
        RECT 2640.04 0 2642.85 6373.08 ;
    END
    PORT
      LAYER Metal4 ;
        RECT 2651.28 0 2654.09 6373.08 ;
    END
    PORT
      LAYER Metal4 ;
        RECT 2662.52 0 2665.33 6373.08 ;
    END
    PORT
      LAYER Metal4 ;
        RECT 2673.76 0 2676.57 6373.08 ;
    END
    PORT
      LAYER Metal4 ;
        RECT 2685 0 2687.81 6373.08 ;
    END
    PORT
      LAYER Metal4 ;
        RECT 2696.24 0 2699.05 6373.08 ;
    END
    PORT
      LAYER Metal4 ;
        RECT 2707.48 0 2710.29 6373.08 ;
    END
    PORT
      LAYER Metal4 ;
        RECT 2718.72 0 2721.53 6373.08 ;
    END
    PORT
      LAYER Metal4 ;
        RECT 2729.96 0 2732.77 6373.08 ;
    END
    PORT
      LAYER Metal4 ;
        RECT 2741.2 0 2744.01 6373.08 ;
    END
    PORT
      LAYER Metal4 ;
        RECT 2752.44 0 2755.25 6373.08 ;
    END
    PORT
      LAYER Metal4 ;
        RECT 2763.68 0 2766.49 6373.08 ;
    END
    PORT
      LAYER Metal4 ;
        RECT 2774.92 0 2777.73 6373.08 ;
    END
    PORT
      LAYER Metal4 ;
        RECT 2786.16 0 2788.97 6373.08 ;
    END
    PORT
      LAYER Metal4 ;
        RECT 2797.4 0 2800.21 6373.08 ;
    END
    PORT
      LAYER Metal4 ;
        RECT 2808.64 0 2811.45 6373.08 ;
    END
    PORT
      LAYER Metal4 ;
        RECT 2819.88 0 2822.69 6373.08 ;
    END
    PORT
      LAYER Metal4 ;
        RECT 2831.12 0 2833.93 6373.08 ;
    END
    PORT
      LAYER Metal4 ;
        RECT 2842.36 0 2845.17 6373.08 ;
    END
    PORT
      LAYER Metal4 ;
        RECT 2853.6 0 2856.41 6373.08 ;
    END
    PORT
      LAYER Metal4 ;
        RECT 2864.84 0 2867.65 6373.08 ;
    END
    PORT
      LAYER Metal4 ;
        RECT 2876.08 0 2878.89 6373.08 ;
    END
    PORT
      LAYER Metal4 ;
        RECT 2887.32 0 2890.13 6373.08 ;
    END
    PORT
      LAYER Metal4 ;
        RECT 2898.56 0 2901.37 6373.08 ;
    END
    PORT
      LAYER Metal4 ;
        RECT 2909.8 0 2912.61 6373.08 ;
    END
    PORT
      LAYER Metal4 ;
        RECT 2921.04 0 2923.85 6373.08 ;
    END
    PORT
      LAYER Metal4 ;
        RECT 2932.28 0 2935.09 6373.08 ;
    END
    PORT
      LAYER Metal4 ;
        RECT 2943.52 0 2946.33 6373.08 ;
    END
    PORT
      LAYER Metal4 ;
        RECT 2954.76 0 2957.57 6373.08 ;
    END
    PORT
      LAYER Metal4 ;
        RECT 2966 0 2968.81 6373.08 ;
    END
    PORT
      LAYER Metal4 ;
        RECT 2977.24 0 2980.05 6373.08 ;
    END
    PORT
      LAYER Metal4 ;
        RECT 2988.48 0 2991.29 6373.08 ;
    END
    PORT
      LAYER Metal4 ;
        RECT 2999.72 0 3002.53 6373.08 ;
    END
    PORT
      LAYER Metal4 ;
        RECT 3010.96 0 3013.77 6373.08 ;
    END
    PORT
      LAYER Metal4 ;
        RECT 3022.2 0 3025.01 6373.08 ;
    END
    PORT
      LAYER Metal4 ;
        RECT 3033.44 0 3036.25 6373.08 ;
    END
    PORT
      LAYER Metal4 ;
        RECT 3044.68 0 3047.49 6373.08 ;
    END
    PORT
      LAYER Metal4 ;
        RECT 3055.92 0 3058.73 6373.08 ;
    END
    PORT
      LAYER Metal4 ;
        RECT 3067.16 0 3069.97 6373.08 ;
    END
    PORT
      LAYER Metal4 ;
        RECT 3078.4 0 3081.21 6373.08 ;
    END
    PORT
      LAYER Metal4 ;
        RECT 3089.64 0 3092.45 6373.08 ;
    END
    PORT
      LAYER Metal4 ;
        RECT 3100.88 0 3103.69 6373.08 ;
    END
    PORT
      LAYER Metal4 ;
        RECT 3112.12 0 3114.93 6373.08 ;
    END
    PORT
      LAYER Metal4 ;
        RECT 3123.36 0 3126.17 6373.08 ;
    END
    PORT
      LAYER Metal4 ;
        RECT 3134.6 0 3137.41 6373.08 ;
    END
    PORT
      LAYER Metal4 ;
        RECT 3145.84 0 3148.65 6373.08 ;
    END
    PORT
      LAYER Metal4 ;
        RECT 3157.08 0 3159.89 6373.08 ;
    END
    PORT
      LAYER Metal4 ;
        RECT 3168.32 0 3171.13 6373.08 ;
    END
    PORT
      LAYER Metal4 ;
        RECT 3179.56 0 3182.37 6373.08 ;
    END
    PORT
      LAYER Metal4 ;
        RECT 3190.8 0 3193.61 6373.08 ;
    END
    PORT
      LAYER Metal4 ;
        RECT 3202.04 0 3204.85 6373.08 ;
    END
    PORT
      LAYER Metal4 ;
        RECT 3213.28 0 3216.09 6373.08 ;
    END
    PORT
      LAYER Metal4 ;
        RECT 3224.52 0 3227.33 6373.08 ;
    END
    PORT
      LAYER Metal4 ;
        RECT 3235.76 0 3238.57 6373.08 ;
    END
    PORT
      LAYER Metal4 ;
        RECT 3247 0 3249.81 6373.08 ;
    END
    PORT
      LAYER Metal4 ;
        RECT 3258.24 0 3261.05 6373.08 ;
    END
    PORT
      LAYER Metal4 ;
        RECT 3269.48 0 3272.29 6373.08 ;
    END
    PORT
      LAYER Metal4 ;
        RECT 3280.72 0 3283.53 6373.08 ;
    END
    PORT
      LAYER Metal4 ;
        RECT 3291.96 0 3294.77 6373.08 ;
    END
    PORT
      LAYER Metal4 ;
        RECT 3303.2 0 3306.01 6373.08 ;
    END
    PORT
      LAYER Metal4 ;
        RECT 3314.44 0 3317.25 6373.08 ;
    END
    PORT
      LAYER Metal4 ;
        RECT 3325.68 0 3328.49 6373.08 ;
    END
    PORT
      LAYER Metal4 ;
        RECT 3336.92 0 3339.73 6373.08 ;
    END
    PORT
      LAYER Metal4 ;
        RECT 3348.16 0 3350.97 6373.08 ;
    END
    PORT
      LAYER Metal4 ;
        RECT 3359.4 0 3362.21 6373.08 ;
    END
    PORT
      LAYER Metal4 ;
        RECT 3370.64 0 3373.45 6373.08 ;
    END
    PORT
      LAYER Metal4 ;
        RECT 3381.88 0 3384.69 6373.08 ;
    END
    PORT
      LAYER Metal4 ;
        RECT 3393.12 0 3395.93 6373.08 ;
    END
    PORT
      LAYER Metal4 ;
        RECT 3404.36 0 3407.17 6373.08 ;
    END
    PORT
      LAYER Metal4 ;
        RECT 3415.6 0 3418.41 6373.08 ;
    END
    PORT
      LAYER Metal4 ;
        RECT 3426.84 0 3429.65 6373.08 ;
    END
    PORT
      LAYER Metal4 ;
        RECT 3438.08 0 3440.89 6373.08 ;
    END
    PORT
      LAYER Metal4 ;
        RECT 3449.32 0 3452.13 6373.08 ;
    END
    PORT
      LAYER Metal4 ;
        RECT 3460.56 0 3463.37 6373.08 ;
    END
    PORT
      LAYER Metal4 ;
        RECT 3471.8 0 3474.61 6373.08 ;
    END
    PORT
      LAYER Metal4 ;
        RECT 3483.04 0 3485.85 6373.08 ;
    END
    PORT
      LAYER Metal4 ;
        RECT 3494.28 0 3497.09 6373.08 ;
    END
    PORT
      LAYER Metal4 ;
        RECT 3505.52 0 3508.33 6373.08 ;
    END
    PORT
      LAYER Metal4 ;
        RECT 3516.76 0 3519.57 6373.08 ;
    END
    PORT
      LAYER Metal4 ;
        RECT 3528 0 3530.81 6373.08 ;
    END
    PORT
      LAYER Metal4 ;
        RECT 3539.24 0 3542.05 6373.08 ;
    END
    PORT
      LAYER Metal4 ;
        RECT 3550.48 0 3553.29 6373.08 ;
    END
    PORT
      LAYER Metal4 ;
        RECT 3561.72 0 3564.53 6373.08 ;
    END
    PORT
      LAYER Metal4 ;
        RECT 3572.96 0 3575.77 6373.08 ;
    END
    PORT
      LAYER Metal4 ;
        RECT 3584.2 0 3587.01 6373.08 ;
    END
    PORT
      LAYER Metal4 ;
        RECT 3595.44 0 3598.25 6373.08 ;
    END
    PORT
      LAYER Metal4 ;
        RECT 3606.68 0 3609.49 6373.08 ;
    END
    PORT
      LAYER Metal4 ;
        RECT 3617.92 0 3620.73 6373.08 ;
    END
    PORT
      LAYER Metal4 ;
        RECT 3629.16 0 3631.97 6373.08 ;
    END
    PORT
      LAYER Metal4 ;
        RECT 3640.4 0 3643.21 6373.08 ;
    END
    PORT
      LAYER Metal4 ;
        RECT 3651.64 0 3654.45 6373.08 ;
    END
    PORT
      LAYER Metal4 ;
        RECT 3662.88 0 3665.69 6373.08 ;
    END
    PORT
      LAYER Metal4 ;
        RECT 3674.12 0 3676.93 6373.08 ;
    END
    PORT
      LAYER Metal4 ;
        RECT 3685.36 0 3688.17 6373.08 ;
    END
    PORT
      LAYER Metal4 ;
        RECT 3696.6 0 3699.41 6373.08 ;
    END
    PORT
      LAYER Metal4 ;
        RECT 3707.84 0 3710.65 6373.08 ;
    END
    PORT
      LAYER Metal4 ;
        RECT 3719.08 0 3721.89 6373.08 ;
    END
    PORT
      LAYER Metal4 ;
        RECT 3730.32 0 3733.13 6373.08 ;
    END
    PORT
      LAYER Metal4 ;
        RECT 3741.56 0 3744.37 6373.08 ;
    END
    PORT
      LAYER Metal4 ;
        RECT 3752.8 0 3755.61 6373.08 ;
    END
    PORT
      LAYER Metal4 ;
        RECT 3764.04 0 3766.85 6373.08 ;
    END
    PORT
      LAYER Metal4 ;
        RECT 3775.28 0 3778.09 6373.08 ;
    END
    PORT
      LAYER Metal4 ;
        RECT 3786.52 0 3789.33 6373.08 ;
    END
    PORT
      LAYER Metal4 ;
        RECT 3797.76 0 3800.57 6373.08 ;
    END
    PORT
      LAYER Metal4 ;
        RECT 3809 0 3811.81 6373.08 ;
    END
    PORT
      LAYER Metal4 ;
        RECT 3820.24 0 3823.05 6373.08 ;
    END
    PORT
      LAYER Metal4 ;
        RECT 3831.48 0 3834.29 6373.08 ;
    END
    PORT
      LAYER Metal4 ;
        RECT 3842.72 0 3845.53 6373.08 ;
    END
    PORT
      LAYER Metal4 ;
        RECT 3853.96 0 3856.77 6373.08 ;
    END
    PORT
      LAYER Metal4 ;
        RECT 3865.2 0 3868.01 6373.08 ;
    END
    PORT
      LAYER Metal4 ;
        RECT 3876.44 0 3879.25 6373.08 ;
    END
    PORT
      LAYER Metal4 ;
        RECT 3887.68 0 3890.49 6373.08 ;
    END
    PORT
      LAYER Metal4 ;
        RECT 3898.92 0 3901.73 6373.08 ;
    END
    PORT
      LAYER Metal4 ;
        RECT 3910.16 0 3912.97 6373.08 ;
    END
    PORT
      LAYER Metal4 ;
        RECT 3921.4 0 3924.21 6373.08 ;
    END
    PORT
      LAYER Metal4 ;
        RECT 3932.64 0 3935.45 6373.08 ;
    END
    PORT
      LAYER Metal4 ;
        RECT 3943.88 0 3946.69 6373.08 ;
    END
    PORT
      LAYER Metal4 ;
        RECT 3955.12 0 3957.93 6373.08 ;
    END
    PORT
      LAYER Metal4 ;
        RECT 3966.36 0 3969.17 6373.08 ;
    END
    PORT
      LAYER Metal4 ;
        RECT 3977.6 0 3980.41 6373.08 ;
    END
    PORT
      LAYER Metal4 ;
        RECT 3988.84 0 3991.65 6373.08 ;
    END
    PORT
      LAYER Metal4 ;
        RECT 4000.08 0 4002.89 6373.08 ;
    END
    PORT
      LAYER Metal4 ;
        RECT 4011.32 0 4014.13 6373.08 ;
    END
    PORT
      LAYER Metal4 ;
        RECT 4022.56 0 4025.37 6373.08 ;
    END
    PORT
      LAYER Metal4 ;
        RECT 4033.8 0 4036.61 6373.08 ;
    END
    PORT
      LAYER Metal4 ;
        RECT 4045.04 0 4047.85 6373.08 ;
    END
    PORT
      LAYER Metal4 ;
        RECT 4056.28 0 4059.09 6373.08 ;
    END
    PORT
      LAYER Metal4 ;
        RECT 4067.52 0 4070.33 6373.08 ;
    END
    PORT
      LAYER Metal4 ;
        RECT 4078.76 0 4081.57 6373.08 ;
    END
    PORT
      LAYER Metal4 ;
        RECT 4090 0 4092.81 6373.08 ;
    END
    PORT
      LAYER Metal4 ;
        RECT 4101.24 0 4104.05 6373.08 ;
    END
    PORT
      LAYER Metal4 ;
        RECT 4112.48 0 4115.29 6373.08 ;
    END
    PORT
      LAYER Metal4 ;
        RECT 4123.72 0 4126.53 6373.08 ;
    END
    PORT
      LAYER Metal4 ;
        RECT 4134.96 0 4137.77 6373.08 ;
    END
    PORT
      LAYER Metal4 ;
        RECT 4146.2 0 4149.01 6373.08 ;
    END
    PORT
      LAYER Metal4 ;
        RECT 4157.44 0 4160.25 6373.08 ;
    END
    PORT
      LAYER Metal4 ;
        RECT 4168.68 0 4171.49 6373.08 ;
    END
    PORT
      LAYER Metal4 ;
        RECT 4179.92 0 4182.73 6373.08 ;
    END
    PORT
      LAYER Metal4 ;
        RECT 4191.16 0 4193.97 6373.08 ;
    END
    PORT
      LAYER Metal4 ;
        RECT 4202.4 0 4205.21 6373.08 ;
    END
    PORT
      LAYER Metal4 ;
        RECT 4213.64 0 4216.45 6373.08 ;
    END
    PORT
      LAYER Metal4 ;
        RECT 4224.88 0 4227.69 6373.08 ;
    END
    PORT
      LAYER Metal4 ;
        RECT 4236.12 0 4238.93 6373.08 ;
    END
    PORT
      LAYER Metal4 ;
        RECT 4247.36 0 4250.17 6373.08 ;
    END
    PORT
      LAYER Metal4 ;
        RECT 4258.6 0 4261.41 6373.08 ;
    END
    PORT
      LAYER Metal4 ;
        RECT 4269.84 0 4272.65 6373.08 ;
    END
    PORT
      LAYER Metal4 ;
        RECT 4281.08 0 4283.89 6373.08 ;
    END
    PORT
      LAYER Metal4 ;
        RECT 4292.32 0 4295.13 6373.08 ;
    END
    PORT
      LAYER Metal4 ;
        RECT 4303.56 0 4306.37 6373.08 ;
    END
    PORT
      LAYER Metal4 ;
        RECT 4314.8 0 4317.61 6373.08 ;
    END
    PORT
      LAYER Metal4 ;
        RECT 4326.04 0 4328.85 6373.08 ;
    END
    PORT
      LAYER Metal4 ;
        RECT 4337.28 0 4340.09 6373.08 ;
    END
    PORT
      LAYER Metal4 ;
        RECT 4348.52 0 4351.33 6373.08 ;
    END
    PORT
      LAYER Metal4 ;
        RECT 4359.76 0 4362.57 6373.08 ;
    END
    PORT
      LAYER Metal4 ;
        RECT 4371 0 4373.81 6373.08 ;
    END
    PORT
      LAYER Metal4 ;
        RECT 4382.24 0 4385.05 6373.08 ;
    END
    PORT
      LAYER Metal4 ;
        RECT 4393.48 0 4396.29 6373.08 ;
    END
    PORT
      LAYER Metal4 ;
        RECT 4404.72 0 4407.53 6373.08 ;
    END
    PORT
      LAYER Metal4 ;
        RECT 4415.96 0 4418.77 6373.08 ;
    END
    PORT
      LAYER Metal4 ;
        RECT 4427.2 0 4430.01 6373.08 ;
    END
    PORT
      LAYER Metal4 ;
        RECT 4438.44 0 4441.25 6373.08 ;
    END
    PORT
      LAYER Metal4 ;
        RECT 4449.68 0 4452.49 6373.08 ;
    END
    PORT
      LAYER Metal4 ;
        RECT 4460.92 0 4463.73 6373.08 ;
    END
    PORT
      LAYER Metal4 ;
        RECT 4472.16 0 4474.97 6373.08 ;
    END
    PORT
      LAYER Metal4 ;
        RECT 4483.4 0 4486.21 6373.08 ;
    END
    PORT
      LAYER Metal4 ;
        RECT 4494.64 0 4497.45 6373.08 ;
    END
    PORT
      LAYER Metal4 ;
        RECT 4505.88 0 4508.69 6373.08 ;
    END
    PORT
      LAYER Metal4 ;
        RECT 4517.12 0 4519.93 6373.08 ;
    END
    PORT
      LAYER Metal4 ;
        RECT 4528.36 0 4531.17 6373.08 ;
    END
    PORT
      LAYER Metal4 ;
        RECT 4539.6 0 4542.41 6373.08 ;
    END
    PORT
      LAYER Metal4 ;
        RECT 4550.84 0 4553.65 6373.08 ;
    END
    PORT
      LAYER Metal4 ;
        RECT 4562.08 0 4564.89 6373.08 ;
    END
    PORT
      LAYER Metal4 ;
        RECT 4573.32 0 4576.13 6373.08 ;
    END
    PORT
      LAYER Metal4 ;
        RECT 4584.56 0 4587.37 6373.08 ;
    END
    PORT
      LAYER Metal4 ;
        RECT 4595.8 0 4598.61 6373.08 ;
    END
    PORT
      LAYER Metal4 ;
        RECT 4607.04 0 4609.85 6373.08 ;
    END
    PORT
      LAYER Metal4 ;
        RECT 4618.28 0 4621.09 6373.08 ;
    END
    PORT
      LAYER Metal4 ;
        RECT 4629.52 0 4632.33 6373.08 ;
    END
    PORT
      LAYER Metal4 ;
        RECT 4640.76 0 4643.57 6373.08 ;
    END
    PORT
      LAYER Metal4 ;
        RECT 4652 0 4654.81 6373.08 ;
    END
    PORT
      LAYER Metal4 ;
        RECT 4663.24 0 4666.05 6373.08 ;
    END
    PORT
      LAYER Metal4 ;
        RECT 4674.48 0 4677.29 6373.08 ;
    END
    PORT
      LAYER Metal4 ;
        RECT 4685.72 0 4688.53 6373.08 ;
    END
    PORT
      LAYER Metal4 ;
        RECT 4696.96 0 4699.77 6373.08 ;
    END
    PORT
      LAYER Metal4 ;
        RECT 4708.2 0 4711.01 6373.08 ;
    END
    PORT
      LAYER Metal4 ;
        RECT 4719.44 0 4722.25 6373.08 ;
    END
    PORT
      LAYER Metal4 ;
        RECT 4730.68 0 4733.49 6373.08 ;
    END
    PORT
      LAYER Metal4 ;
        RECT 4741.92 0 4744.73 6373.08 ;
    END
    PORT
      LAYER Metal4 ;
        RECT 4753.16 0 4755.97 6373.08 ;
    END
    PORT
      LAYER Metal4 ;
        RECT 4764.4 0 4767.21 6373.08 ;
    END
    PORT
      LAYER Metal4 ;
        RECT 4775.64 0 4778.45 6373.08 ;
    END
    PORT
      LAYER Metal4 ;
        RECT 4786.88 0 4789.69 6373.08 ;
    END
    PORT
      LAYER Metal4 ;
        RECT 4798.12 0 4800.93 6373.08 ;
    END
    PORT
      LAYER Metal4 ;
        RECT 4809.36 0 4812.17 6373.08 ;
    END
    PORT
      LAYER Metal4 ;
        RECT 4820.6 0 4823.41 6373.08 ;
    END
    PORT
      LAYER Metal4 ;
        RECT 4831.84 0 4834.65 6373.08 ;
    END
    PORT
      LAYER Metal4 ;
        RECT 4843.08 0 4845.89 6373.08 ;
    END
    PORT
      LAYER Metal4 ;
        RECT 4854.32 0 4857.13 6373.08 ;
    END
    PORT
      LAYER Metal4 ;
        RECT 4865.56 0 4868.37 6373.08 ;
    END
    PORT
      LAYER Metal4 ;
        RECT 4876.8 0 4879.61 6373.08 ;
    END
    PORT
      LAYER Metal4 ;
        RECT 4888.04 0 4890.85 6373.08 ;
    END
    PORT
      LAYER Metal4 ;
        RECT 4899.28 0 4902.09 6373.08 ;
    END
    PORT
      LAYER Metal4 ;
        RECT 4910.52 0 4913.33 6373.08 ;
    END
    PORT
      LAYER Metal4 ;
        RECT 4921.76 0 4924.57 6373.08 ;
    END
    PORT
      LAYER Metal4 ;
        RECT 4933 0 4935.81 6373.08 ;
    END
    PORT
      LAYER Metal4 ;
        RECT 4944.24 0 4947.05 6373.08 ;
    END
    PORT
      LAYER Metal4 ;
        RECT 4955.48 0 4958.29 6373.08 ;
    END
    PORT
      LAYER Metal4 ;
        RECT 4966.72 0 4969.53 6373.08 ;
    END
    PORT
      LAYER Metal4 ;
        RECT 4977.96 0 4980.77 6373.08 ;
    END
    PORT
      LAYER Metal4 ;
        RECT 4989.2 0 4992.01 6373.08 ;
    END
    PORT
      LAYER Metal4 ;
        RECT 5000.44 0 5003.25 6373.08 ;
    END
    PORT
      LAYER Metal4 ;
        RECT 5011.68 0 5014.49 6373.08 ;
    END
    PORT
      LAYER Metal4 ;
        RECT 5022.92 0 5025.73 6373.08 ;
    END
    PORT
      LAYER Metal4 ;
        RECT 5034.16 0 5036.97 6373.08 ;
    END
    PORT
      LAYER Metal4 ;
        RECT 5045.4 0 5048.21 6373.08 ;
    END
    PORT
      LAYER Metal4 ;
        RECT 5056.64 0 5059.45 6373.08 ;
    END
    PORT
      LAYER Metal4 ;
        RECT 5067.88 0 5070.69 6373.08 ;
    END
    PORT
      LAYER Metal4 ;
        RECT 5079.12 0 5081.93 6373.08 ;
    END
    PORT
      LAYER Metal4 ;
        RECT 5090.36 0 5093.17 6373.08 ;
    END
    PORT
      LAYER Metal4 ;
        RECT 5101.6 0 5104.41 6373.08 ;
    END
    PORT
      LAYER Metal4 ;
        RECT 5112.84 0 5115.65 6373.08 ;
    END
    PORT
      LAYER Metal4 ;
        RECT 5124.08 0 5126.89 6373.08 ;
    END
    PORT
      LAYER Metal4 ;
        RECT 5135.32 0 5138.13 6373.08 ;
    END
    PORT
      LAYER Metal4 ;
        RECT 5146.56 0 5149.37 6373.08 ;
    END
    PORT
      LAYER Metal4 ;
        RECT 5157.8 0 5160.61 6373.08 ;
    END
    PORT
      LAYER Metal4 ;
        RECT 5169.04 0 5171.85 6373.08 ;
    END
    PORT
      LAYER Metal4 ;
        RECT 5180.28 0 5183.09 6373.08 ;
    END
    PORT
      LAYER Metal4 ;
        RECT 5191.52 0 5194.33 6373.08 ;
    END
    PORT
      LAYER Metal4 ;
        RECT 5202.76 0 5205.57 6373.08 ;
    END
    PORT
      LAYER Metal4 ;
        RECT 5214 0 5216.81 6373.08 ;
    END
    PORT
      LAYER Metal4 ;
        RECT 5225.24 0 5228.05 6373.08 ;
    END
    PORT
      LAYER Metal4 ;
        RECT 5236.48 0 5239.29 6373.08 ;
    END
    PORT
      LAYER Metal4 ;
        RECT 5247.72 0 5250.53 6373.08 ;
    END
    PORT
      LAYER Metal4 ;
        RECT 5258.96 0 5261.77 6373.08 ;
    END
    PORT
      LAYER Metal4 ;
        RECT 5270.2 0 5273.01 6373.08 ;
    END
    PORT
      LAYER Metal4 ;
        RECT 5281.44 0 5284.25 6373.08 ;
    END
    PORT
      LAYER Metal4 ;
        RECT 5292.68 0 5295.49 6373.08 ;
    END
    PORT
      LAYER Metal4 ;
        RECT 5303.92 0 5306.73 6373.08 ;
    END
    PORT
      LAYER Metal4 ;
        RECT 5315.16 0 5317.97 6373.08 ;
    END
    PORT
      LAYER Metal4 ;
        RECT 5326.4 0 5329.21 6373.08 ;
    END
    PORT
      LAYER Metal4 ;
        RECT 5337.64 0 5340.45 6373.08 ;
    END
    PORT
      LAYER Metal4 ;
        RECT 5348.88 0 5351.69 6373.08 ;
    END
    PORT
      LAYER Metal4 ;
        RECT 5360.12 0 5362.93 6373.08 ;
    END
    PORT
      LAYER Metal4 ;
        RECT 5371.36 0 5374.17 6373.08 ;
    END
    PORT
      LAYER Metal4 ;
        RECT 5382.6 0 5385.41 6373.08 ;
    END
    PORT
      LAYER Metal4 ;
        RECT 5393.84 0 5396.65 6373.08 ;
    END
    PORT
      LAYER Metal4 ;
        RECT 5405.08 0 5407.89 6373.08 ;
    END
    PORT
      LAYER Metal4 ;
        RECT 5416.32 0 5419.13 6373.08 ;
    END
    PORT
      LAYER Metal4 ;
        RECT 5427.56 0 5430.37 6373.08 ;
    END
    PORT
      LAYER Metal4 ;
        RECT 5438.8 0 5441.61 6373.08 ;
    END
    PORT
      LAYER Metal4 ;
        RECT 5450.04 0 5452.85 6373.08 ;
    END
    PORT
      LAYER Metal4 ;
        RECT 5461.28 0 5464.09 6373.08 ;
    END
    PORT
      LAYER Metal4 ;
        RECT 5472.52 0 5475.33 6373.08 ;
    END
    PORT
      LAYER Metal4 ;
        RECT 5483.76 0 5486.57 6373.08 ;
    END
    PORT
      LAYER Metal4 ;
        RECT 5495 0 5497.81 6373.08 ;
    END
    PORT
      LAYER Metal4 ;
        RECT 5506.24 0 5509.05 6373.08 ;
    END
    PORT
      LAYER Metal4 ;
        RECT 5517.48 0 5520.29 6373.08 ;
    END
    PORT
      LAYER Metal4 ;
        RECT 5528.72 0 5531.53 6373.08 ;
    END
    PORT
      LAYER Metal4 ;
        RECT 5539.96 0 5542.77 6373.08 ;
    END
    PORT
      LAYER Metal4 ;
        RECT 5551.2 0 5554.01 6373.08 ;
    END
    PORT
      LAYER Metal4 ;
        RECT 5562.44 0 5565.25 6373.08 ;
    END
    PORT
      LAYER Metal4 ;
        RECT 5573.68 0 5576.49 6373.08 ;
    END
    PORT
      LAYER Metal4 ;
        RECT 5584.92 0 5587.73 6373.08 ;
    END
    PORT
      LAYER Metal4 ;
        RECT 5596.16 0 5598.97 6373.08 ;
    END
    PORT
      LAYER Metal4 ;
        RECT 5607.4 0 5610.21 6373.08 ;
    END
    PORT
      LAYER Metal4 ;
        RECT 5618.64 0 5621.45 6373.08 ;
    END
    PORT
      LAYER Metal4 ;
        RECT 5629.88 0 5632.69 6373.08 ;
    END
    PORT
      LAYER Metal4 ;
        RECT 5641.12 0 5643.93 6373.08 ;
    END
    PORT
      LAYER Metal4 ;
        RECT 5652.36 0 5655.17 6373.08 ;
    END
    PORT
      LAYER Metal4 ;
        RECT 5663.6 0 5666.41 6373.08 ;
    END
    PORT
      LAYER Metal4 ;
        RECT 5674.84 0 5677.65 6373.08 ;
    END
    PORT
      LAYER Metal4 ;
        RECT 5686.08 0 5688.89 6373.08 ;
    END
    PORT
      LAYER Metal4 ;
        RECT 5697.32 0 5700.13 6373.08 ;
    END
    PORT
      LAYER Metal4 ;
        RECT 5708.56 0 5711.37 6373.08 ;
    END
    PORT
      LAYER Metal4 ;
        RECT 5719.8 0 5722.61 6373.08 ;
    END
    PORT
      LAYER Metal4 ;
        RECT 5731.04 0 5733.85 6373.08 ;
    END
    PORT
      LAYER Metal4 ;
        RECT 5742.28 0 5745.09 6373.08 ;
    END
    PORT
      LAYER Metal4 ;
        RECT 5753.52 0 5756.33 6373.08 ;
    END
    PORT
      LAYER Metal4 ;
        RECT 5764.76 0 5767.57 6373.08 ;
    END
    PORT
      LAYER Metal4 ;
        RECT 5776 0 5778.81 6373.08 ;
    END
    PORT
      LAYER Metal4 ;
        RECT 5787.24 0 5790.05 6373.08 ;
    END
    PORT
      LAYER Metal4 ;
        RECT 5798.48 0 5801.29 6373.08 ;
    END
    PORT
      LAYER Metal4 ;
        RECT 5809.72 0 5812.53 6373.08 ;
    END
    PORT
      LAYER Metal4 ;
        RECT 5820.96 0 5823.77 6373.08 ;
    END
    PORT
      LAYER Metal4 ;
        RECT 5832.2 0 5835.01 6373.08 ;
    END
    PORT
      LAYER Metal4 ;
        RECT 5843.44 0 5846.25 6373.08 ;
    END
    PORT
      LAYER Metal4 ;
        RECT 5854.68 0 5857.49 6373.08 ;
    END
    PORT
      LAYER Metal4 ;
        RECT 5865.92 0 5868.73 6373.08 ;
    END
    PORT
      LAYER Metal4 ;
        RECT 5877.16 0 5879.97 6373.08 ;
    END
    PORT
      LAYER Metal4 ;
        RECT 5888.4 0 5891.21 6373.08 ;
    END
    PORT
      LAYER Metal4 ;
        RECT 5899.64 0 5902.45 6373.08 ;
    END
    PORT
      LAYER Metal4 ;
        RECT 5910.88 0 5913.69 6373.08 ;
    END
    PORT
      LAYER Metal4 ;
        RECT 5922.12 0 5924.93 6373.08 ;
    END
    PORT
      LAYER Metal4 ;
        RECT 5933.36 0 5936.17 6373.08 ;
    END
    PORT
      LAYER Metal4 ;
        RECT 5944.6 0 5947.41 6373.08 ;
    END
    PORT
      LAYER Metal4 ;
        RECT 5955.84 0 5958.65 6373.08 ;
    END
    PORT
      LAYER Metal4 ;
        RECT 5967.08 0 5969.89 6373.08 ;
    END
    PORT
      LAYER Metal4 ;
        RECT 5978.32 0 5981.13 6373.08 ;
    END
    PORT
      LAYER Metal4 ;
        RECT 5989.56 0 5992.37 6373.08 ;
    END
    PORT
      LAYER Metal4 ;
        RECT 6000.8 0 6003.61 6373.08 ;
    END
    PORT
      LAYER Metal4 ;
        RECT 6012.04 0 6014.85 6373.08 ;
    END
    PORT
      LAYER Metal4 ;
        RECT 6023.28 0 6026.09 6373.08 ;
    END
    PORT
      LAYER Metal4 ;
        RECT 6034.52 0 6037.33 6373.08 ;
    END
    PORT
      LAYER Metal4 ;
        RECT 6045.76 0 6048.57 6373.08 ;
    END
    PORT
      LAYER Metal4 ;
        RECT 6057 0 6059.81 6373.08 ;
    END
    PORT
      LAYER Metal4 ;
        RECT 6068.24 0 6071.05 6373.08 ;
    END
    PORT
      LAYER Metal4 ;
        RECT 6079.48 0 6082.29 6373.08 ;
    END
    PORT
      LAYER Metal4 ;
        RECT 6090.72 0 6093.53 6373.08 ;
    END
    PORT
      LAYER Metal4 ;
        RECT 6101.96 0 6104.77 6373.08 ;
    END
    PORT
      LAYER Metal4 ;
        RECT 6113.2 0 6116.01 6373.08 ;
    END
    PORT
      LAYER Metal4 ;
        RECT 6124.44 0 6127.25 6373.08 ;
    END
    PORT
      LAYER Metal4 ;
        RECT 6135.68 0 6138.49 6373.08 ;
    END
    PORT
      LAYER Metal4 ;
        RECT 6146.92 0 6149.73 6373.08 ;
    END
    PORT
      LAYER Metal4 ;
        RECT 6158.16 0 6160.97 6373.08 ;
    END
    PORT
      LAYER Metal4 ;
        RECT 6169.4 0 6172.21 6373.08 ;
    END
    PORT
      LAYER Metal4 ;
        RECT 6180.64 0 6183.45 6373.08 ;
    END
    PORT
      LAYER Metal4 ;
        RECT 6191.88 0 6194.69 6373.08 ;
    END
    PORT
      LAYER Metal4 ;
        RECT 6203.12 0 6205.93 6373.08 ;
    END
    PORT
      LAYER Metal4 ;
        RECT 6214.36 0 6217.17 6373.08 ;
    END
    PORT
      LAYER Metal4 ;
        RECT 6225.6 0 6228.41 6373.08 ;
    END
    PORT
      LAYER Metal4 ;
        RECT 6236.84 0 6239.65 6373.08 ;
    END
    PORT
      LAYER Metal4 ;
        RECT 6248.08 0 6250.89 6373.08 ;
    END
    PORT
      LAYER Metal4 ;
        RECT 6259.32 0 6262.13 6373.08 ;
    END
    PORT
      LAYER Metal4 ;
        RECT 6270.56 0 6273.37 6373.08 ;
    END
    PORT
      LAYER Metal4 ;
        RECT 6281.8 0 6284.61 6373.08 ;
    END
    PORT
      LAYER Metal4 ;
        RECT 6293.04 0 6295.85 6373.08 ;
    END
    PORT
      LAYER Metal4 ;
        RECT 6304.28 0 6307.09 6373.08 ;
    END
    PORT
      LAYER Metal4 ;
        RECT 6315.52 0 6318.33 6373.08 ;
    END
    PORT
      LAYER Metal4 ;
        RECT 6326.76 0 6329.57 6373.08 ;
    END
    PORT
      LAYER Metal4 ;
        RECT 6338 0 6340.81 6373.08 ;
    END
    PORT
      LAYER Metal4 ;
        RECT 6349.24 0 6352.05 6373.08 ;
    END
  END VSS
  OBS
    LAYER Metal1 ;
      RECT 0 0 6372 6373.08 ;
    LAYER Metal2 ;
      RECT 0 1 6372 6373.08 ;
    LAYER Metal3 ;
      RECT 0 1 6372 6373.08 ;
  END
END IHPSG13_SYNTHETIC_RRAM_1P_131072x144

END LIBRARY
